# OpenTallas memory compiler (tools/mem_compiler), ASAP7 abstract view
VERSION 5.7 ;
BUSBITCHARS "[]" ;
DIVIDERCHAR "/" ;
PROPERTYDEFINITIONS
  MACRO width INTEGER ;
  MACRO depth INTEGER ;
  MACRO banks INTEGER ;
END PROPERTYDEFINITIONS
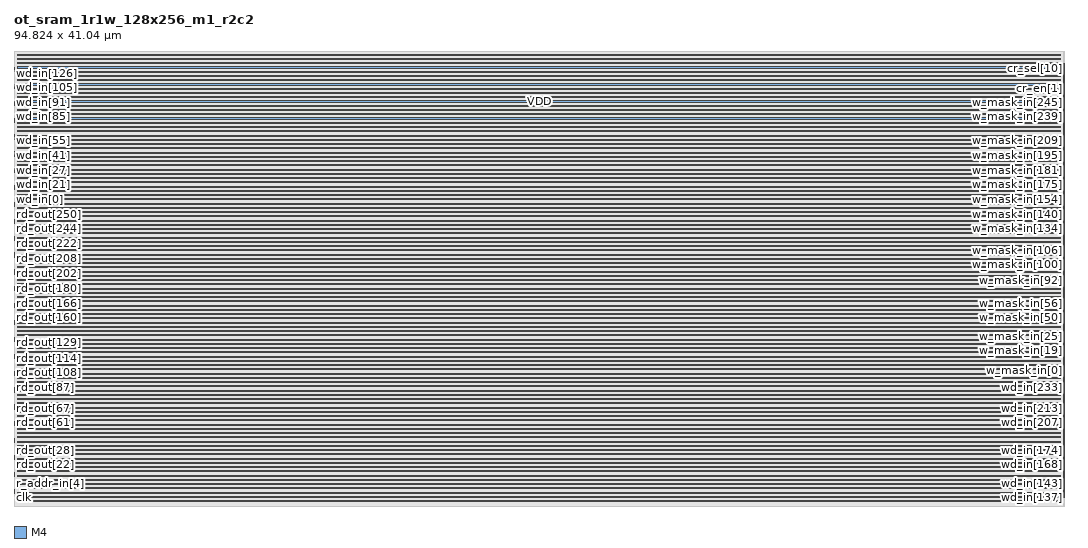
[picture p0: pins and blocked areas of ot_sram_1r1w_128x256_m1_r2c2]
MACRO ot_sram_1r1w_128x256_m1_r2c2
  PROPERTY width 256 ;
  PROPERTY depth 128 ;
  PROPERTY banks 1 ;
  FOREIGN ot_sram_1r1w_128x256_m1_r2c2 0 0 ;
  SYMMETRY X Y R90 ;
  SIZE 94.824 BY 41.040 ;
  CLASS BLOCK ;
  PIN clk
    DIRECTION INPUT ;
    USE CLOCK ;
    SHAPE ABUTMENT ;
    PORT
      LAYER M4 ;
      RECT 0.000 0.768 0.024 0.792 ;
    END
  END clk
  PIN r_ce_in
    DIRECTION INPUT ;
    USE SIGNAL ;
    SHAPE ABUTMENT ;
    PORT
      LAYER M4 ;
      RECT 0.000 0.864 0.024 0.888 ;
    END
  END r_ce_in
  PIN r_addr_in[0]
    DIRECTION INPUT ;
    USE SIGNAL ;
    SHAPE ABUTMENT ;
    PORT
      LAYER M4 ;
      RECT 0.000 0.960 0.024 0.984 ;
    END
  END r_addr_in[0]
  PIN r_addr_in[1]
    DIRECTION INPUT ;
    USE SIGNAL ;
    SHAPE ABUTMENT ;
    PORT
      LAYER M4 ;
      RECT 0.000 1.056 0.024 1.080 ;
    END
  END r_addr_in[1]
  PIN r_addr_in[2]
    DIRECTION INPUT ;
    USE SIGNAL ;
    SHAPE ABUTMENT ;
    PORT
      LAYER M4 ;
      RECT 0.000 1.152 0.024 1.176 ;
    END
  END r_addr_in[2]
  PIN r_addr_in[3]
    DIRECTION INPUT ;
    USE SIGNAL ;
    SHAPE ABUTMENT ;
    PORT
      LAYER M4 ;
      RECT 0.000 1.248 0.024 1.272 ;
    END
  END r_addr_in[3]
  PIN r_addr_in[4]
    DIRECTION INPUT ;
    USE SIGNAL ;
    SHAPE ABUTMENT ;
    PORT
      LAYER M4 ;
      RECT 0.000 1.344 0.024 1.368 ;
    END
  END r_addr_in[4]
  PIN r_addr_in[5]
    DIRECTION INPUT ;
    USE SIGNAL ;
    SHAPE ABUTMENT ;
    PORT
      LAYER M4 ;
      RECT 0.000 1.440 0.024 1.464 ;
    END
  END r_addr_in[5]
  PIN r_addr_in[6]
    DIRECTION INPUT ;
    USE SIGNAL ;
    SHAPE ABUTMENT ;
    PORT
      LAYER M4 ;
      RECT 0.000 1.536 0.024 1.560 ;
    END
  END r_addr_in[6]
  PIN rd_out[0]
    DIRECTION OUTPUT ;
    USE SIGNAL ;
    SHAPE ABUTMENT ;
    PORT
      LAYER M4 ;
      RECT 0.000 1.632 0.024 1.656 ;
    END
  END rd_out[0]
  PIN rd_out[1]
    DIRECTION OUTPUT ;
    USE SIGNAL ;
    SHAPE ABUTMENT ;
    PORT
      LAYER M4 ;
      RECT 0.000 1.728 0.024 1.752 ;
    END
  END rd_out[1]
  PIN rd_out[2]
    DIRECTION OUTPUT ;
    USE SIGNAL ;
    SHAPE ABUTMENT ;
    PORT
      LAYER M4 ;
      RECT 0.000 1.824 0.024 1.848 ;
    END
  END rd_out[2]
  PIN rd_out[3]
    DIRECTION OUTPUT ;
    USE SIGNAL ;
    SHAPE ABUTMENT ;
    PORT
      LAYER M4 ;
      RECT 0.000 1.920 0.024 1.944 ;
    END
  END rd_out[3]
  PIN rd_out[4]
    DIRECTION OUTPUT ;
    USE SIGNAL ;
    SHAPE ABUTMENT ;
    PORT
      LAYER M4 ;
      RECT 0.000 2.016 0.024 2.040 ;
    END
  END rd_out[4]
  PIN rd_out[5]
    DIRECTION OUTPUT ;
    USE SIGNAL ;
    SHAPE ABUTMENT ;
    PORT
      LAYER M4 ;
      RECT 0.000 2.112 0.024 2.136 ;
    END
  END rd_out[5]
  PIN rd_out[6]
    DIRECTION OUTPUT ;
    USE SIGNAL ;
    SHAPE ABUTMENT ;
    PORT
      LAYER M4 ;
      RECT 0.000 2.208 0.024 2.232 ;
    END
  END rd_out[6]
  PIN rd_out[7]
    DIRECTION OUTPUT ;
    USE SIGNAL ;
    SHAPE ABUTMENT ;
    PORT
      LAYER M4 ;
      RECT 0.000 2.304 0.024 2.328 ;
    END
  END rd_out[7]
  PIN rd_out[8]
    DIRECTION OUTPUT ;
    USE SIGNAL ;
    SHAPE ABUTMENT ;
    PORT
      LAYER M4 ;
      RECT 0.000 2.400 0.024 2.424 ;
    END
  END rd_out[8]
  PIN rd_out[9]
    DIRECTION OUTPUT ;
    USE SIGNAL ;
    SHAPE ABUTMENT ;
    PORT
      LAYER M4 ;
      RECT 0.000 2.496 0.024 2.520 ;
    END
  END rd_out[9]
  PIN rd_out[10]
    DIRECTION OUTPUT ;
    USE SIGNAL ;
    SHAPE ABUTMENT ;
    PORT
      LAYER M4 ;
      RECT 0.000 2.592 0.024 2.616 ;
    END
  END rd_out[10]
  PIN rd_out[11]
    DIRECTION OUTPUT ;
    USE SIGNAL ;
    SHAPE ABUTMENT ;
    PORT
      LAYER M4 ;
      RECT 0.000 2.688 0.024 2.712 ;
    END
  END rd_out[11]
  PIN rd_out[12]
    DIRECTION OUTPUT ;
    USE SIGNAL ;
    SHAPE ABUTMENT ;
    PORT
      LAYER M4 ;
      RECT 0.000 2.784 0.024 2.808 ;
    END
  END rd_out[12]
  PIN rd_out[13]
    DIRECTION OUTPUT ;
    USE SIGNAL ;
    SHAPE ABUTMENT ;
    PORT
      LAYER M4 ;
      RECT 0.000 2.880 0.024 2.904 ;
    END
  END rd_out[13]
  PIN rd_out[14]
    DIRECTION OUTPUT ;
    USE SIGNAL ;
    SHAPE ABUTMENT ;
    PORT
      LAYER M4 ;
      RECT 0.000 2.976 0.024 3.000 ;
    END
  END rd_out[14]
  PIN rd_out[15]
    DIRECTION OUTPUT ;
    USE SIGNAL ;
    SHAPE ABUTMENT ;
    PORT
      LAYER M4 ;
      RECT 0.000 3.072 0.024 3.096 ;
    END
  END rd_out[15]
  PIN rd_out[16]
    DIRECTION OUTPUT ;
    USE SIGNAL ;
    SHAPE ABUTMENT ;
    PORT
      LAYER M4 ;
      RECT 0.000 3.168 0.024 3.192 ;
    END
  END rd_out[16]
  PIN rd_out[17]
    DIRECTION OUTPUT ;
    USE SIGNAL ;
    SHAPE ABUTMENT ;
    PORT
      LAYER M4 ;
      RECT 0.000 3.264 0.024 3.288 ;
    END
  END rd_out[17]
  PIN rd_out[18]
    DIRECTION OUTPUT ;
    USE SIGNAL ;
    SHAPE ABUTMENT ;
    PORT
      LAYER M4 ;
      RECT 0.000 3.360 0.024 3.384 ;
    END
  END rd_out[18]
  PIN rd_out[19]
    DIRECTION OUTPUT ;
    USE SIGNAL ;
    SHAPE ABUTMENT ;
    PORT
      LAYER M4 ;
      RECT 0.000 3.456 0.024 3.480 ;
    END
  END rd_out[19]
  PIN rd_out[20]
    DIRECTION OUTPUT ;
    USE SIGNAL ;
    SHAPE ABUTMENT ;
    PORT
      LAYER M4 ;
      RECT 0.000 3.552 0.024 3.576 ;
    END
  END rd_out[20]
  PIN rd_out[21]
    DIRECTION OUTPUT ;
    USE SIGNAL ;
    SHAPE ABUTMENT ;
    PORT
      LAYER M4 ;
      RECT 0.000 3.648 0.024 3.672 ;
    END
  END rd_out[21]
  PIN rd_out[22]
    DIRECTION OUTPUT ;
    USE SIGNAL ;
    SHAPE ABUTMENT ;
    PORT
      LAYER M4 ;
      RECT 0.000 3.744 0.024 3.768 ;
    END
  END rd_out[22]
  PIN rd_out[23]
    DIRECTION OUTPUT ;
    USE SIGNAL ;
    SHAPE ABUTMENT ;
    PORT
      LAYER M4 ;
      RECT 0.000 3.840 0.024 3.864 ;
    END
  END rd_out[23]
  PIN rd_out[24]
    DIRECTION OUTPUT ;
    USE SIGNAL ;
    SHAPE ABUTMENT ;
    PORT
      LAYER M4 ;
      RECT 0.000 3.936 0.024 3.960 ;
    END
  END rd_out[24]
  PIN rd_out[25]
    DIRECTION OUTPUT ;
    USE SIGNAL ;
    SHAPE ABUTMENT ;
    PORT
      LAYER M4 ;
      RECT 0.000 4.032 0.024 4.056 ;
    END
  END rd_out[25]
  PIN rd_out[26]
    DIRECTION OUTPUT ;
    USE SIGNAL ;
    SHAPE ABUTMENT ;
    PORT
      LAYER M4 ;
      RECT 0.000 4.128 0.024 4.152 ;
    END
  END rd_out[26]
  PIN rd_out[27]
    DIRECTION OUTPUT ;
    USE SIGNAL ;
    SHAPE ABUTMENT ;
    PORT
      LAYER M4 ;
      RECT 0.000 4.224 0.024 4.248 ;
    END
  END rd_out[27]
  PIN rd_out[28]
    DIRECTION OUTPUT ;
    USE SIGNAL ;
    SHAPE ABUTMENT ;
    PORT
      LAYER M4 ;
      RECT 0.000 4.320 0.024 4.344 ;
    END
  END rd_out[28]
  PIN rd_out[29]
    DIRECTION OUTPUT ;
    USE SIGNAL ;
    SHAPE ABUTMENT ;
    PORT
      LAYER M4 ;
      RECT 0.000 4.416 0.024 4.440 ;
    END
  END rd_out[29]
  PIN rd_out[30]
    DIRECTION OUTPUT ;
    USE SIGNAL ;
    SHAPE ABUTMENT ;
    PORT
      LAYER M4 ;
      RECT 0.000 4.512 0.024 4.536 ;
    END
  END rd_out[30]
  PIN rd_out[31]
    DIRECTION OUTPUT ;
    USE SIGNAL ;
    SHAPE ABUTMENT ;
    PORT
      LAYER M4 ;
      RECT 0.000 4.608 0.024 4.632 ;
    END
  END rd_out[31]
  PIN rd_out[32]
    DIRECTION OUTPUT ;
    USE SIGNAL ;
    SHAPE ABUTMENT ;
    PORT
      LAYER M4 ;
      RECT 0.000 4.704 0.024 4.728 ;
    END
  END rd_out[32]
  PIN rd_out[33]
    DIRECTION OUTPUT ;
    USE SIGNAL ;
    SHAPE ABUTMENT ;
    PORT
      LAYER M4 ;
      RECT 0.000 4.800 0.024 4.824 ;
    END
  END rd_out[33]
  PIN rd_out[34]
    DIRECTION OUTPUT ;
    USE SIGNAL ;
    SHAPE ABUTMENT ;
    PORT
      LAYER M4 ;
      RECT 0.000 4.896 0.024 4.920 ;
    END
  END rd_out[34]
  PIN rd_out[35]
    DIRECTION OUTPUT ;
    USE SIGNAL ;
    SHAPE ABUTMENT ;
    PORT
      LAYER M4 ;
      RECT 0.000 4.992 0.024 5.016 ;
    END
  END rd_out[35]
  PIN rd_out[36]
    DIRECTION OUTPUT ;
    USE SIGNAL ;
    SHAPE ABUTMENT ;
    PORT
      LAYER M4 ;
      RECT 0.000 5.088 0.024 5.112 ;
    END
  END rd_out[36]
  PIN rd_out[37]
    DIRECTION OUTPUT ;
    USE SIGNAL ;
    SHAPE ABUTMENT ;
    PORT
      LAYER M4 ;
      RECT 0.000 5.184 0.024 5.208 ;
    END
  END rd_out[37]
  PIN rd_out[38]
    DIRECTION OUTPUT ;
    USE SIGNAL ;
    SHAPE ABUTMENT ;
    PORT
      LAYER M4 ;
      RECT 0.000 5.280 0.024 5.304 ;
    END
  END rd_out[38]
  PIN rd_out[39]
    DIRECTION OUTPUT ;
    USE SIGNAL ;
    SHAPE ABUTMENT ;
    PORT
      LAYER M4 ;
      RECT 0.000 5.376 0.024 5.400 ;
    END
  END rd_out[39]
  PIN rd_out[40]
    DIRECTION OUTPUT ;
    USE SIGNAL ;
    SHAPE ABUTMENT ;
    PORT
      LAYER M4 ;
      RECT 0.000 5.472 0.024 5.496 ;
    END
  END rd_out[40]
  PIN rd_out[41]
    DIRECTION OUTPUT ;
    USE SIGNAL ;
    SHAPE ABUTMENT ;
    PORT
      LAYER M4 ;
      RECT 0.000 5.568 0.024 5.592 ;
    END
  END rd_out[41]
  PIN rd_out[42]
    DIRECTION OUTPUT ;
    USE SIGNAL ;
    SHAPE ABUTMENT ;
    PORT
      LAYER M4 ;
      RECT 0.000 5.664 0.024 5.688 ;
    END
  END rd_out[42]
  PIN rd_out[43]
    DIRECTION OUTPUT ;
    USE SIGNAL ;
    SHAPE ABUTMENT ;
    PORT
      LAYER M4 ;
      RECT 0.000 5.760 0.024 5.784 ;
    END
  END rd_out[43]
  PIN rd_out[44]
    DIRECTION OUTPUT ;
    USE SIGNAL ;
    SHAPE ABUTMENT ;
    PORT
      LAYER M4 ;
      RECT 0.000 5.856 0.024 5.880 ;
    END
  END rd_out[44]
  PIN rd_out[45]
    DIRECTION OUTPUT ;
    USE SIGNAL ;
    SHAPE ABUTMENT ;
    PORT
      LAYER M4 ;
      RECT 0.000 5.952 0.024 5.976 ;
    END
  END rd_out[45]
  PIN rd_out[46]
    DIRECTION OUTPUT ;
    USE SIGNAL ;
    SHAPE ABUTMENT ;
    PORT
      LAYER M4 ;
      RECT 0.000 6.048 0.024 6.072 ;
    END
  END rd_out[46]
  PIN rd_out[47]
    DIRECTION OUTPUT ;
    USE SIGNAL ;
    SHAPE ABUTMENT ;
    PORT
      LAYER M4 ;
      RECT 0.000 6.144 0.024 6.168 ;
    END
  END rd_out[47]
  PIN rd_out[48]
    DIRECTION OUTPUT ;
    USE SIGNAL ;
    SHAPE ABUTMENT ;
    PORT
      LAYER M4 ;
      RECT 0.000 6.240 0.024 6.264 ;
    END
  END rd_out[48]
  PIN rd_out[49]
    DIRECTION OUTPUT ;
    USE SIGNAL ;
    SHAPE ABUTMENT ;
    PORT
      LAYER M4 ;
      RECT 0.000 6.336 0.024 6.360 ;
    END
  END rd_out[49]
  PIN rd_out[50]
    DIRECTION OUTPUT ;
    USE SIGNAL ;
    SHAPE ABUTMENT ;
    PORT
      LAYER M4 ;
      RECT 0.000 6.432 0.024 6.456 ;
    END
  END rd_out[50]
  PIN rd_out[51]
    DIRECTION OUTPUT ;
    USE SIGNAL ;
    SHAPE ABUTMENT ;
    PORT
      LAYER M4 ;
      RECT 0.000 6.528 0.024 6.552 ;
    END
  END rd_out[51]
  PIN rd_out[52]
    DIRECTION OUTPUT ;
    USE SIGNAL ;
    SHAPE ABUTMENT ;
    PORT
      LAYER M4 ;
      RECT 0.000 6.624 0.024 6.648 ;
    END
  END rd_out[52]
  PIN rd_out[53]
    DIRECTION OUTPUT ;
    USE SIGNAL ;
    SHAPE ABUTMENT ;
    PORT
      LAYER M4 ;
      RECT 0.000 6.720 0.024 6.744 ;
    END
  END rd_out[53]
  PIN rd_out[54]
    DIRECTION OUTPUT ;
    USE SIGNAL ;
    SHAPE ABUTMENT ;
    PORT
      LAYER M4 ;
      RECT 0.000 6.816 0.024 6.840 ;
    END
  END rd_out[54]
  PIN rd_out[55]
    DIRECTION OUTPUT ;
    USE SIGNAL ;
    SHAPE ABUTMENT ;
    PORT
      LAYER M4 ;
      RECT 0.000 6.912 0.024 6.936 ;
    END
  END rd_out[55]
  PIN rd_out[56]
    DIRECTION OUTPUT ;
    USE SIGNAL ;
    SHAPE ABUTMENT ;
    PORT
      LAYER M4 ;
      RECT 0.000 7.008 0.024 7.032 ;
    END
  END rd_out[56]
  PIN rd_out[57]
    DIRECTION OUTPUT ;
    USE SIGNAL ;
    SHAPE ABUTMENT ;
    PORT
      LAYER M4 ;
      RECT 0.000 7.104 0.024 7.128 ;
    END
  END rd_out[57]
  PIN rd_out[58]
    DIRECTION OUTPUT ;
    USE SIGNAL ;
    SHAPE ABUTMENT ;
    PORT
      LAYER M4 ;
      RECT 0.000 7.200 0.024 7.224 ;
    END
  END rd_out[58]
  PIN rd_out[59]
    DIRECTION OUTPUT ;
    USE SIGNAL ;
    SHAPE ABUTMENT ;
    PORT
      LAYER M4 ;
      RECT 0.000 7.296 0.024 7.320 ;
    END
  END rd_out[59]
  PIN rd_out[60]
    DIRECTION OUTPUT ;
    USE SIGNAL ;
    SHAPE ABUTMENT ;
    PORT
      LAYER M4 ;
      RECT 0.000 7.392 0.024 7.416 ;
    END
  END rd_out[60]
  PIN rd_out[61]
    DIRECTION OUTPUT ;
    USE SIGNAL ;
    SHAPE ABUTMENT ;
    PORT
      LAYER M4 ;
      RECT 0.000 7.488 0.024 7.512 ;
    END
  END rd_out[61]
  PIN rd_out[62]
    DIRECTION OUTPUT ;
    USE SIGNAL ;
    SHAPE ABUTMENT ;
    PORT
      LAYER M4 ;
      RECT 0.000 7.584 0.024 7.608 ;
    END
  END rd_out[62]
  PIN rd_out[63]
    DIRECTION OUTPUT ;
    USE SIGNAL ;
    SHAPE ABUTMENT ;
    PORT
      LAYER M4 ;
      RECT 0.000 7.680 0.024 7.704 ;
    END
  END rd_out[63]
  PIN rd_out[64]
    DIRECTION OUTPUT ;
    USE SIGNAL ;
    SHAPE ABUTMENT ;
    PORT
      LAYER M4 ;
      RECT 0.000 7.776 0.024 7.800 ;
    END
  END rd_out[64]
  PIN rd_out[65]
    DIRECTION OUTPUT ;
    USE SIGNAL ;
    SHAPE ABUTMENT ;
    PORT
      LAYER M4 ;
      RECT 0.000 7.872 0.024 7.896 ;
    END
  END rd_out[65]
  PIN rd_out[66]
    DIRECTION OUTPUT ;
    USE SIGNAL ;
    SHAPE ABUTMENT ;
    PORT
      LAYER M4 ;
      RECT 0.000 7.968 0.024 7.992 ;
    END
  END rd_out[66]
  PIN rd_out[67]
    DIRECTION OUTPUT ;
    USE SIGNAL ;
    SHAPE ABUTMENT ;
    PORT
      LAYER M4 ;
      RECT 0.000 8.064 0.024 8.088 ;
    END
  END rd_out[67]
  PIN rd_out[68]
    DIRECTION OUTPUT ;
    USE SIGNAL ;
    SHAPE ABUTMENT ;
    PORT
      LAYER M4 ;
      RECT 0.000 8.160 0.024 8.184 ;
    END
  END rd_out[68]
  PIN rd_out[69]
    DIRECTION OUTPUT ;
    USE SIGNAL ;
    SHAPE ABUTMENT ;
    PORT
      LAYER M4 ;
      RECT 0.000 8.256 0.024 8.280 ;
    END
  END rd_out[69]
  PIN rd_out[70]
    DIRECTION OUTPUT ;
    USE SIGNAL ;
    SHAPE ABUTMENT ;
    PORT
      LAYER M4 ;
      RECT 0.000 8.352 0.024 8.376 ;
    END
  END rd_out[70]
  PIN rd_out[71]
    DIRECTION OUTPUT ;
    USE SIGNAL ;
    SHAPE ABUTMENT ;
    PORT
      LAYER M4 ;
      RECT 0.000 8.448 0.024 8.472 ;
    END
  END rd_out[71]
  PIN rd_out[72]
    DIRECTION OUTPUT ;
    USE SIGNAL ;
    SHAPE ABUTMENT ;
    PORT
      LAYER M4 ;
      RECT 0.000 8.544 0.024 8.568 ;
    END
  END rd_out[72]
  PIN rd_out[73]
    DIRECTION OUTPUT ;
    USE SIGNAL ;
    SHAPE ABUTMENT ;
    PORT
      LAYER M4 ;
      RECT 0.000 8.640 0.024 8.664 ;
    END
  END rd_out[73]
  PIN rd_out[74]
    DIRECTION OUTPUT ;
    USE SIGNAL ;
    SHAPE ABUTMENT ;
    PORT
      LAYER M4 ;
      RECT 0.000 8.736 0.024 8.760 ;
    END
  END rd_out[74]
  PIN rd_out[75]
    DIRECTION OUTPUT ;
    USE SIGNAL ;
    SHAPE ABUTMENT ;
    PORT
      LAYER M4 ;
      RECT 0.000 8.832 0.024 8.856 ;
    END
  END rd_out[75]
  PIN rd_out[76]
    DIRECTION OUTPUT ;
    USE SIGNAL ;
    SHAPE ABUTMENT ;
    PORT
      LAYER M4 ;
      RECT 0.000 8.928 0.024 8.952 ;
    END
  END rd_out[76]
  PIN rd_out[77]
    DIRECTION OUTPUT ;
    USE SIGNAL ;
    SHAPE ABUTMENT ;
    PORT
      LAYER M4 ;
      RECT 0.000 9.024 0.024 9.048 ;
    END
  END rd_out[77]
  PIN rd_out[78]
    DIRECTION OUTPUT ;
    USE SIGNAL ;
    SHAPE ABUTMENT ;
    PORT
      LAYER M4 ;
      RECT 0.000 9.120 0.024 9.144 ;
    END
  END rd_out[78]
  PIN rd_out[79]
    DIRECTION OUTPUT ;
    USE SIGNAL ;
    SHAPE ABUTMENT ;
    PORT
      LAYER M4 ;
      RECT 0.000 9.216 0.024 9.240 ;
    END
  END rd_out[79]
  PIN rd_out[80]
    DIRECTION OUTPUT ;
    USE SIGNAL ;
    SHAPE ABUTMENT ;
    PORT
      LAYER M4 ;
      RECT 0.000 9.312 0.024 9.336 ;
    END
  END rd_out[80]
  PIN rd_out[81]
    DIRECTION OUTPUT ;
    USE SIGNAL ;
    SHAPE ABUTMENT ;
    PORT
      LAYER M4 ;
      RECT 0.000 9.408 0.024 9.432 ;
    END
  END rd_out[81]
  PIN rd_out[82]
    DIRECTION OUTPUT ;
    USE SIGNAL ;
    SHAPE ABUTMENT ;
    PORT
      LAYER M4 ;
      RECT 0.000 9.504 0.024 9.528 ;
    END
  END rd_out[82]
  PIN rd_out[83]
    DIRECTION OUTPUT ;
    USE SIGNAL ;
    SHAPE ABUTMENT ;
    PORT
      LAYER M4 ;
      RECT 0.000 9.600 0.024 9.624 ;
    END
  END rd_out[83]
  PIN rd_out[84]
    DIRECTION OUTPUT ;
    USE SIGNAL ;
    SHAPE ABUTMENT ;
    PORT
      LAYER M4 ;
      RECT 0.000 9.696 0.024 9.720 ;
    END
  END rd_out[84]
  PIN rd_out[85]
    DIRECTION OUTPUT ;
    USE SIGNAL ;
    SHAPE ABUTMENT ;
    PORT
      LAYER M4 ;
      RECT 0.000 9.792 0.024 9.816 ;
    END
  END rd_out[85]
  PIN rd_out[86]
    DIRECTION OUTPUT ;
    USE SIGNAL ;
    SHAPE ABUTMENT ;
    PORT
      LAYER M4 ;
      RECT 0.000 9.888 0.024 9.912 ;
    END
  END rd_out[86]
  PIN rd_out[87]
    DIRECTION OUTPUT ;
    USE SIGNAL ;
    SHAPE ABUTMENT ;
    PORT
      LAYER M4 ;
      RECT 0.000 9.984 0.024 10.008 ;
    END
  END rd_out[87]
  PIN rd_out[88]
    DIRECTION OUTPUT ;
    USE SIGNAL ;
    SHAPE ABUTMENT ;
    PORT
      LAYER M4 ;
      RECT 0.000 10.080 0.024 10.104 ;
    END
  END rd_out[88]
  PIN rd_out[89]
    DIRECTION OUTPUT ;
    USE SIGNAL ;
    SHAPE ABUTMENT ;
    PORT
      LAYER M4 ;
      RECT 0.000 10.176 0.024 10.200 ;
    END
  END rd_out[89]
  PIN rd_out[90]
    DIRECTION OUTPUT ;
    USE SIGNAL ;
    SHAPE ABUTMENT ;
    PORT
      LAYER M4 ;
      RECT 0.000 10.272 0.024 10.296 ;
    END
  END rd_out[90]
  PIN rd_out[91]
    DIRECTION OUTPUT ;
    USE SIGNAL ;
    SHAPE ABUTMENT ;
    PORT
      LAYER M4 ;
      RECT 0.000 10.368 0.024 10.392 ;
    END
  END rd_out[91]
  PIN rd_out[92]
    DIRECTION OUTPUT ;
    USE SIGNAL ;
    SHAPE ABUTMENT ;
    PORT
      LAYER M4 ;
      RECT 0.000 10.464 0.024 10.488 ;
    END
  END rd_out[92]
  PIN rd_out[93]
    DIRECTION OUTPUT ;
    USE SIGNAL ;
    SHAPE ABUTMENT ;
    PORT
      LAYER M4 ;
      RECT 0.000 10.560 0.024 10.584 ;
    END
  END rd_out[93]
  PIN rd_out[94]
    DIRECTION OUTPUT ;
    USE SIGNAL ;
    SHAPE ABUTMENT ;
    PORT
      LAYER M4 ;
      RECT 0.000 10.656 0.024 10.680 ;
    END
  END rd_out[94]
  PIN rd_out[95]
    DIRECTION OUTPUT ;
    USE SIGNAL ;
    SHAPE ABUTMENT ;
    PORT
      LAYER M4 ;
      RECT 0.000 10.752 0.024 10.776 ;
    END
  END rd_out[95]
  PIN rd_out[96]
    DIRECTION OUTPUT ;
    USE SIGNAL ;
    SHAPE ABUTMENT ;
    PORT
      LAYER M4 ;
      RECT 0.000 10.848 0.024 10.872 ;
    END
  END rd_out[96]
  PIN rd_out[97]
    DIRECTION OUTPUT ;
    USE SIGNAL ;
    SHAPE ABUTMENT ;
    PORT
      LAYER M4 ;
      RECT 0.000 10.944 0.024 10.968 ;
    END
  END rd_out[97]
  PIN rd_out[98]
    DIRECTION OUTPUT ;
    USE SIGNAL ;
    SHAPE ABUTMENT ;
    PORT
      LAYER M4 ;
      RECT 0.000 11.040 0.024 11.064 ;
    END
  END rd_out[98]
  PIN rd_out[99]
    DIRECTION OUTPUT ;
    USE SIGNAL ;
    SHAPE ABUTMENT ;
    PORT
      LAYER M4 ;
      RECT 0.000 11.136 0.024 11.160 ;
    END
  END rd_out[99]
  PIN rd_out[100]
    DIRECTION OUTPUT ;
    USE SIGNAL ;
    SHAPE ABUTMENT ;
    PORT
      LAYER M4 ;
      RECT 0.000 11.232 0.024 11.256 ;
    END
  END rd_out[100]
  PIN rd_out[101]
    DIRECTION OUTPUT ;
    USE SIGNAL ;
    SHAPE ABUTMENT ;
    PORT
      LAYER M4 ;
      RECT 0.000 11.328 0.024 11.352 ;
    END
  END rd_out[101]
  PIN rd_out[102]
    DIRECTION OUTPUT ;
    USE SIGNAL ;
    SHAPE ABUTMENT ;
    PORT
      LAYER M4 ;
      RECT 0.000 11.424 0.024 11.448 ;
    END
  END rd_out[102]
  PIN rd_out[103]
    DIRECTION OUTPUT ;
    USE SIGNAL ;
    SHAPE ABUTMENT ;
    PORT
      LAYER M4 ;
      RECT 0.000 11.520 0.024 11.544 ;
    END
  END rd_out[103]
  PIN rd_out[104]
    DIRECTION OUTPUT ;
    USE SIGNAL ;
    SHAPE ABUTMENT ;
    PORT
      LAYER M4 ;
      RECT 0.000 11.616 0.024 11.640 ;
    END
  END rd_out[104]
  PIN rd_out[105]
    DIRECTION OUTPUT ;
    USE SIGNAL ;
    SHAPE ABUTMENT ;
    PORT
      LAYER M4 ;
      RECT 0.000 11.712 0.024 11.736 ;
    END
  END rd_out[105]
  PIN rd_out[106]
    DIRECTION OUTPUT ;
    USE SIGNAL ;
    SHAPE ABUTMENT ;
    PORT
      LAYER M4 ;
      RECT 0.000 11.808 0.024 11.832 ;
    END
  END rd_out[106]
  PIN rd_out[107]
    DIRECTION OUTPUT ;
    USE SIGNAL ;
    SHAPE ABUTMENT ;
    PORT
      LAYER M4 ;
      RECT 0.000 11.904 0.024 11.928 ;
    END
  END rd_out[107]
  PIN rd_out[108]
    DIRECTION OUTPUT ;
    USE SIGNAL ;
    SHAPE ABUTMENT ;
    PORT
      LAYER M4 ;
      RECT 0.000 12.000 0.024 12.024 ;
    END
  END rd_out[108]
  PIN rd_out[109]
    DIRECTION OUTPUT ;
    USE SIGNAL ;
    SHAPE ABUTMENT ;
    PORT
      LAYER M4 ;
      RECT 0.000 12.096 0.024 12.120 ;
    END
  END rd_out[109]
  PIN rd_out[110]
    DIRECTION OUTPUT ;
    USE SIGNAL ;
    SHAPE ABUTMENT ;
    PORT
      LAYER M4 ;
      RECT 0.000 12.192 0.024 12.216 ;
    END
  END rd_out[110]
  PIN rd_out[111]
    DIRECTION OUTPUT ;
    USE SIGNAL ;
    SHAPE ABUTMENT ;
    PORT
      LAYER M4 ;
      RECT 0.000 12.288 0.024 12.312 ;
    END
  END rd_out[111]
  PIN rd_out[112]
    DIRECTION OUTPUT ;
    USE SIGNAL ;
    SHAPE ABUTMENT ;
    PORT
      LAYER M4 ;
      RECT 0.000 12.384 0.024 12.408 ;
    END
  END rd_out[112]
  PIN rd_out[113]
    DIRECTION OUTPUT ;
    USE SIGNAL ;
    SHAPE ABUTMENT ;
    PORT
      LAYER M4 ;
      RECT 0.000 12.480 0.024 12.504 ;
    END
  END rd_out[113]
  PIN rd_out[114]
    DIRECTION OUTPUT ;
    USE SIGNAL ;
    SHAPE ABUTMENT ;
    PORT
      LAYER M4 ;
      RECT 0.000 12.576 0.024 12.600 ;
    END
  END rd_out[114]
  PIN rd_out[115]
    DIRECTION OUTPUT ;
    USE SIGNAL ;
    SHAPE ABUTMENT ;
    PORT
      LAYER M4 ;
      RECT 0.000 12.672 0.024 12.696 ;
    END
  END rd_out[115]
  PIN rd_out[116]
    DIRECTION OUTPUT ;
    USE SIGNAL ;
    SHAPE ABUTMENT ;
    PORT
      LAYER M4 ;
      RECT 0.000 12.768 0.024 12.792 ;
    END
  END rd_out[116]
  PIN rd_out[117]
    DIRECTION OUTPUT ;
    USE SIGNAL ;
    SHAPE ABUTMENT ;
    PORT
      LAYER M4 ;
      RECT 0.000 12.864 0.024 12.888 ;
    END
  END rd_out[117]
  PIN rd_out[118]
    DIRECTION OUTPUT ;
    USE SIGNAL ;
    SHAPE ABUTMENT ;
    PORT
      LAYER M4 ;
      RECT 0.000 12.960 0.024 12.984 ;
    END
  END rd_out[118]
  PIN rd_out[119]
    DIRECTION OUTPUT ;
    USE SIGNAL ;
    SHAPE ABUTMENT ;
    PORT
      LAYER M4 ;
      RECT 0.000 13.056 0.024 13.080 ;
    END
  END rd_out[119]
  PIN rd_out[120]
    DIRECTION OUTPUT ;
    USE SIGNAL ;
    SHAPE ABUTMENT ;
    PORT
      LAYER M4 ;
      RECT 0.000 13.152 0.024 13.176 ;
    END
  END rd_out[120]
  PIN rd_out[121]
    DIRECTION OUTPUT ;
    USE SIGNAL ;
    SHAPE ABUTMENT ;
    PORT
      LAYER M4 ;
      RECT 0.000 13.248 0.024 13.272 ;
    END
  END rd_out[121]
  PIN rd_out[122]
    DIRECTION OUTPUT ;
    USE SIGNAL ;
    SHAPE ABUTMENT ;
    PORT
      LAYER M4 ;
      RECT 0.000 13.344 0.024 13.368 ;
    END
  END rd_out[122]
  PIN rd_out[123]
    DIRECTION OUTPUT ;
    USE SIGNAL ;
    SHAPE ABUTMENT ;
    PORT
      LAYER M4 ;
      RECT 0.000 13.440 0.024 13.464 ;
    END
  END rd_out[123]
  PIN rd_out[124]
    DIRECTION OUTPUT ;
    USE SIGNAL ;
    SHAPE ABUTMENT ;
    PORT
      LAYER M4 ;
      RECT 0.000 13.536 0.024 13.560 ;
    END
  END rd_out[124]
  PIN rd_out[125]
    DIRECTION OUTPUT ;
    USE SIGNAL ;
    SHAPE ABUTMENT ;
    PORT
      LAYER M4 ;
      RECT 0.000 13.632 0.024 13.656 ;
    END
  END rd_out[125]
  PIN rd_out[126]
    DIRECTION OUTPUT ;
    USE SIGNAL ;
    SHAPE ABUTMENT ;
    PORT
      LAYER M4 ;
      RECT 0.000 13.728 0.024 13.752 ;
    END
  END rd_out[126]
  PIN rd_out[127]
    DIRECTION OUTPUT ;
    USE SIGNAL ;
    SHAPE ABUTMENT ;
    PORT
      LAYER M4 ;
      RECT 0.000 13.824 0.024 13.848 ;
    END
  END rd_out[127]
  PIN rd_out[128]
    DIRECTION OUTPUT ;
    USE SIGNAL ;
    SHAPE ABUTMENT ;
    PORT
      LAYER M4 ;
      RECT 0.000 13.920 0.024 13.944 ;
    END
  END rd_out[128]
  PIN rd_out[129]
    DIRECTION OUTPUT ;
    USE SIGNAL ;
    SHAPE ABUTMENT ;
    PORT
      LAYER M4 ;
      RECT 0.000 14.016 0.024 14.040 ;
    END
  END rd_out[129]
  PIN rd_out[130]
    DIRECTION OUTPUT ;
    USE SIGNAL ;
    SHAPE ABUTMENT ;
    PORT
      LAYER M4 ;
      RECT 0.000 14.112 0.024 14.136 ;
    END
  END rd_out[130]
  PIN rd_out[131]
    DIRECTION OUTPUT ;
    USE SIGNAL ;
    SHAPE ABUTMENT ;
    PORT
      LAYER M4 ;
      RECT 0.000 14.208 0.024 14.232 ;
    END
  END rd_out[131]
  PIN rd_out[132]
    DIRECTION OUTPUT ;
    USE SIGNAL ;
    SHAPE ABUTMENT ;
    PORT
      LAYER M4 ;
      RECT 0.000 14.304 0.024 14.328 ;
    END
  END rd_out[132]
  PIN rd_out[133]
    DIRECTION OUTPUT ;
    USE SIGNAL ;
    SHAPE ABUTMENT ;
    PORT
      LAYER M4 ;
      RECT 0.000 14.400 0.024 14.424 ;
    END
  END rd_out[133]
  PIN rd_out[134]
    DIRECTION OUTPUT ;
    USE SIGNAL ;
    SHAPE ABUTMENT ;
    PORT
      LAYER M4 ;
      RECT 0.000 14.496 0.024 14.520 ;
    END
  END rd_out[134]
  PIN rd_out[135]
    DIRECTION OUTPUT ;
    USE SIGNAL ;
    SHAPE ABUTMENT ;
    PORT
      LAYER M4 ;
      RECT 0.000 14.592 0.024 14.616 ;
    END
  END rd_out[135]
  PIN rd_out[136]
    DIRECTION OUTPUT ;
    USE SIGNAL ;
    SHAPE ABUTMENT ;
    PORT
      LAYER M4 ;
      RECT 0.000 14.688 0.024 14.712 ;
    END
  END rd_out[136]
  PIN rd_out[137]
    DIRECTION OUTPUT ;
    USE SIGNAL ;
    SHAPE ABUTMENT ;
    PORT
      LAYER M4 ;
      RECT 0.000 14.784 0.024 14.808 ;
    END
  END rd_out[137]
  PIN rd_out[138]
    DIRECTION OUTPUT ;
    USE SIGNAL ;
    SHAPE ABUTMENT ;
    PORT
      LAYER M4 ;
      RECT 0.000 14.880 0.024 14.904 ;
    END
  END rd_out[138]
  PIN rd_out[139]
    DIRECTION OUTPUT ;
    USE SIGNAL ;
    SHAPE ABUTMENT ;
    PORT
      LAYER M4 ;
      RECT 0.000 14.976 0.024 15.000 ;
    END
  END rd_out[139]
  PIN rd_out[140]
    DIRECTION OUTPUT ;
    USE SIGNAL ;
    SHAPE ABUTMENT ;
    PORT
      LAYER M4 ;
      RECT 0.000 15.072 0.024 15.096 ;
    END
  END rd_out[140]
  PIN rd_out[141]
    DIRECTION OUTPUT ;
    USE SIGNAL ;
    SHAPE ABUTMENT ;
    PORT
      LAYER M4 ;
      RECT 0.000 15.168 0.024 15.192 ;
    END
  END rd_out[141]
  PIN rd_out[142]
    DIRECTION OUTPUT ;
    USE SIGNAL ;
    SHAPE ABUTMENT ;
    PORT
      LAYER M4 ;
      RECT 0.000 15.264 0.024 15.288 ;
    END
  END rd_out[142]
  PIN rd_out[143]
    DIRECTION OUTPUT ;
    USE SIGNAL ;
    SHAPE ABUTMENT ;
    PORT
      LAYER M4 ;
      RECT 0.000 15.360 0.024 15.384 ;
    END
  END rd_out[143]
  PIN rd_out[144]
    DIRECTION OUTPUT ;
    USE SIGNAL ;
    SHAPE ABUTMENT ;
    PORT
      LAYER M4 ;
      RECT 0.000 15.456 0.024 15.480 ;
    END
  END rd_out[144]
  PIN rd_out[145]
    DIRECTION OUTPUT ;
    USE SIGNAL ;
    SHAPE ABUTMENT ;
    PORT
      LAYER M4 ;
      RECT 0.000 15.552 0.024 15.576 ;
    END
  END rd_out[145]
  PIN rd_out[146]
    DIRECTION OUTPUT ;
    USE SIGNAL ;
    SHAPE ABUTMENT ;
    PORT
      LAYER M4 ;
      RECT 0.000 15.648 0.024 15.672 ;
    END
  END rd_out[146]
  PIN rd_out[147]
    DIRECTION OUTPUT ;
    USE SIGNAL ;
    SHAPE ABUTMENT ;
    PORT
      LAYER M4 ;
      RECT 0.000 15.744 0.024 15.768 ;
    END
  END rd_out[147]
  PIN rd_out[148]
    DIRECTION OUTPUT ;
    USE SIGNAL ;
    SHAPE ABUTMENT ;
    PORT
      LAYER M4 ;
      RECT 0.000 15.840 0.024 15.864 ;
    END
  END rd_out[148]
  PIN rd_out[149]
    DIRECTION OUTPUT ;
    USE SIGNAL ;
    SHAPE ABUTMENT ;
    PORT
      LAYER M4 ;
      RECT 0.000 15.936 0.024 15.960 ;
    END
  END rd_out[149]
  PIN rd_out[150]
    DIRECTION OUTPUT ;
    USE SIGNAL ;
    SHAPE ABUTMENT ;
    PORT
      LAYER M4 ;
      RECT 0.000 16.032 0.024 16.056 ;
    END
  END rd_out[150]
  PIN rd_out[151]
    DIRECTION OUTPUT ;
    USE SIGNAL ;
    SHAPE ABUTMENT ;
    PORT
      LAYER M4 ;
      RECT 0.000 16.128 0.024 16.152 ;
    END
  END rd_out[151]
  PIN rd_out[152]
    DIRECTION OUTPUT ;
    USE SIGNAL ;
    SHAPE ABUTMENT ;
    PORT
      LAYER M4 ;
      RECT 0.000 16.224 0.024 16.248 ;
    END
  END rd_out[152]
  PIN rd_out[153]
    DIRECTION OUTPUT ;
    USE SIGNAL ;
    SHAPE ABUTMENT ;
    PORT
      LAYER M4 ;
      RECT 0.000 16.320 0.024 16.344 ;
    END
  END rd_out[153]
  PIN rd_out[154]
    DIRECTION OUTPUT ;
    USE SIGNAL ;
    SHAPE ABUTMENT ;
    PORT
      LAYER M4 ;
      RECT 0.000 16.416 0.024 16.440 ;
    END
  END rd_out[154]
  PIN rd_out[155]
    DIRECTION OUTPUT ;
    USE SIGNAL ;
    SHAPE ABUTMENT ;
    PORT
      LAYER M4 ;
      RECT 0.000 16.512 0.024 16.536 ;
    END
  END rd_out[155]
  PIN rd_out[156]
    DIRECTION OUTPUT ;
    USE SIGNAL ;
    SHAPE ABUTMENT ;
    PORT
      LAYER M4 ;
      RECT 0.000 16.608 0.024 16.632 ;
    END
  END rd_out[156]
  PIN rd_out[157]
    DIRECTION OUTPUT ;
    USE SIGNAL ;
    SHAPE ABUTMENT ;
    PORT
      LAYER M4 ;
      RECT 0.000 16.704 0.024 16.728 ;
    END
  END rd_out[157]
  PIN rd_out[158]
    DIRECTION OUTPUT ;
    USE SIGNAL ;
    SHAPE ABUTMENT ;
    PORT
      LAYER M4 ;
      RECT 0.000 16.800 0.024 16.824 ;
    END
  END rd_out[158]
  PIN rd_out[159]
    DIRECTION OUTPUT ;
    USE SIGNAL ;
    SHAPE ABUTMENT ;
    PORT
      LAYER M4 ;
      RECT 0.000 16.896 0.024 16.920 ;
    END
  END rd_out[159]
  PIN rd_out[160]
    DIRECTION OUTPUT ;
    USE SIGNAL ;
    SHAPE ABUTMENT ;
    PORT
      LAYER M4 ;
      RECT 0.000 16.992 0.024 17.016 ;
    END
  END rd_out[160]
  PIN rd_out[161]
    DIRECTION OUTPUT ;
    USE SIGNAL ;
    SHAPE ABUTMENT ;
    PORT
      LAYER M4 ;
      RECT 0.000 17.088 0.024 17.112 ;
    END
  END rd_out[161]
  PIN rd_out[162]
    DIRECTION OUTPUT ;
    USE SIGNAL ;
    SHAPE ABUTMENT ;
    PORT
      LAYER M4 ;
      RECT 0.000 17.184 0.024 17.208 ;
    END
  END rd_out[162]
  PIN rd_out[163]
    DIRECTION OUTPUT ;
    USE SIGNAL ;
    SHAPE ABUTMENT ;
    PORT
      LAYER M4 ;
      RECT 0.000 17.280 0.024 17.304 ;
    END
  END rd_out[163]
  PIN rd_out[164]
    DIRECTION OUTPUT ;
    USE SIGNAL ;
    SHAPE ABUTMENT ;
    PORT
      LAYER M4 ;
      RECT 0.000 17.376 0.024 17.400 ;
    END
  END rd_out[164]
  PIN rd_out[165]
    DIRECTION OUTPUT ;
    USE SIGNAL ;
    SHAPE ABUTMENT ;
    PORT
      LAYER M4 ;
      RECT 0.000 17.472 0.024 17.496 ;
    END
  END rd_out[165]
  PIN rd_out[166]
    DIRECTION OUTPUT ;
    USE SIGNAL ;
    SHAPE ABUTMENT ;
    PORT
      LAYER M4 ;
      RECT 0.000 17.568 0.024 17.592 ;
    END
  END rd_out[166]
  PIN rd_out[167]
    DIRECTION OUTPUT ;
    USE SIGNAL ;
    SHAPE ABUTMENT ;
    PORT
      LAYER M4 ;
      RECT 0.000 17.664 0.024 17.688 ;
    END
  END rd_out[167]
  PIN rd_out[168]
    DIRECTION OUTPUT ;
    USE SIGNAL ;
    SHAPE ABUTMENT ;
    PORT
      LAYER M4 ;
      RECT 0.000 17.760 0.024 17.784 ;
    END
  END rd_out[168]
  PIN rd_out[169]
    DIRECTION OUTPUT ;
    USE SIGNAL ;
    SHAPE ABUTMENT ;
    PORT
      LAYER M4 ;
      RECT 0.000 17.856 0.024 17.880 ;
    END
  END rd_out[169]
  PIN rd_out[170]
    DIRECTION OUTPUT ;
    USE SIGNAL ;
    SHAPE ABUTMENT ;
    PORT
      LAYER M4 ;
      RECT 0.000 17.952 0.024 17.976 ;
    END
  END rd_out[170]
  PIN rd_out[171]
    DIRECTION OUTPUT ;
    USE SIGNAL ;
    SHAPE ABUTMENT ;
    PORT
      LAYER M4 ;
      RECT 0.000 18.048 0.024 18.072 ;
    END
  END rd_out[171]
  PIN rd_out[172]
    DIRECTION OUTPUT ;
    USE SIGNAL ;
    SHAPE ABUTMENT ;
    PORT
      LAYER M4 ;
      RECT 0.000 18.144 0.024 18.168 ;
    END
  END rd_out[172]
  PIN rd_out[173]
    DIRECTION OUTPUT ;
    USE SIGNAL ;
    SHAPE ABUTMENT ;
    PORT
      LAYER M4 ;
      RECT 0.000 18.240 0.024 18.264 ;
    END
  END rd_out[173]
  PIN rd_out[174]
    DIRECTION OUTPUT ;
    USE SIGNAL ;
    SHAPE ABUTMENT ;
    PORT
      LAYER M4 ;
      RECT 0.000 18.336 0.024 18.360 ;
    END
  END rd_out[174]
  PIN rd_out[175]
    DIRECTION OUTPUT ;
    USE SIGNAL ;
    SHAPE ABUTMENT ;
    PORT
      LAYER M4 ;
      RECT 0.000 18.432 0.024 18.456 ;
    END
  END rd_out[175]
  PIN rd_out[176]
    DIRECTION OUTPUT ;
    USE SIGNAL ;
    SHAPE ABUTMENT ;
    PORT
      LAYER M4 ;
      RECT 0.000 18.528 0.024 18.552 ;
    END
  END rd_out[176]
  PIN rd_out[177]
    DIRECTION OUTPUT ;
    USE SIGNAL ;
    SHAPE ABUTMENT ;
    PORT
      LAYER M4 ;
      RECT 0.000 18.624 0.024 18.648 ;
    END
  END rd_out[177]
  PIN rd_out[178]
    DIRECTION OUTPUT ;
    USE SIGNAL ;
    SHAPE ABUTMENT ;
    PORT
      LAYER M4 ;
      RECT 0.000 18.720 0.024 18.744 ;
    END
  END rd_out[178]
  PIN rd_out[179]
    DIRECTION OUTPUT ;
    USE SIGNAL ;
    SHAPE ABUTMENT ;
    PORT
      LAYER M4 ;
      RECT 0.000 18.816 0.024 18.840 ;
    END
  END rd_out[179]
  PIN rd_out[180]
    DIRECTION OUTPUT ;
    USE SIGNAL ;
    SHAPE ABUTMENT ;
    PORT
      LAYER M4 ;
      RECT 0.000 18.912 0.024 18.936 ;
    END
  END rd_out[180]
  PIN rd_out[181]
    DIRECTION OUTPUT ;
    USE SIGNAL ;
    SHAPE ABUTMENT ;
    PORT
      LAYER M4 ;
      RECT 0.000 19.008 0.024 19.032 ;
    END
  END rd_out[181]
  PIN rd_out[182]
    DIRECTION OUTPUT ;
    USE SIGNAL ;
    SHAPE ABUTMENT ;
    PORT
      LAYER M4 ;
      RECT 0.000 19.104 0.024 19.128 ;
    END
  END rd_out[182]
  PIN rd_out[183]
    DIRECTION OUTPUT ;
    USE SIGNAL ;
    SHAPE ABUTMENT ;
    PORT
      LAYER M4 ;
      RECT 0.000 19.200 0.024 19.224 ;
    END
  END rd_out[183]
  PIN rd_out[184]
    DIRECTION OUTPUT ;
    USE SIGNAL ;
    SHAPE ABUTMENT ;
    PORT
      LAYER M4 ;
      RECT 0.000 19.296 0.024 19.320 ;
    END
  END rd_out[184]
  PIN rd_out[185]
    DIRECTION OUTPUT ;
    USE SIGNAL ;
    SHAPE ABUTMENT ;
    PORT
      LAYER M4 ;
      RECT 0.000 19.392 0.024 19.416 ;
    END
  END rd_out[185]
  PIN rd_out[186]
    DIRECTION OUTPUT ;
    USE SIGNAL ;
    SHAPE ABUTMENT ;
    PORT
      LAYER M4 ;
      RECT 0.000 19.488 0.024 19.512 ;
    END
  END rd_out[186]
  PIN rd_out[187]
    DIRECTION OUTPUT ;
    USE SIGNAL ;
    SHAPE ABUTMENT ;
    PORT
      LAYER M4 ;
      RECT 0.000 19.584 0.024 19.608 ;
    END
  END rd_out[187]
  PIN rd_out[188]
    DIRECTION OUTPUT ;
    USE SIGNAL ;
    SHAPE ABUTMENT ;
    PORT
      LAYER M4 ;
      RECT 0.000 19.680 0.024 19.704 ;
    END
  END rd_out[188]
  PIN rd_out[189]
    DIRECTION OUTPUT ;
    USE SIGNAL ;
    SHAPE ABUTMENT ;
    PORT
      LAYER M4 ;
      RECT 0.000 19.776 0.024 19.800 ;
    END
  END rd_out[189]
  PIN rd_out[190]
    DIRECTION OUTPUT ;
    USE SIGNAL ;
    SHAPE ABUTMENT ;
    PORT
      LAYER M4 ;
      RECT 0.000 19.872 0.024 19.896 ;
    END
  END rd_out[190]
  PIN rd_out[191]
    DIRECTION OUTPUT ;
    USE SIGNAL ;
    SHAPE ABUTMENT ;
    PORT
      LAYER M4 ;
      RECT 0.000 19.968 0.024 19.992 ;
    END
  END rd_out[191]
  PIN rd_out[192]
    DIRECTION OUTPUT ;
    USE SIGNAL ;
    SHAPE ABUTMENT ;
    PORT
      LAYER M4 ;
      RECT 0.000 20.064 0.024 20.088 ;
    END
  END rd_out[192]
  PIN rd_out[193]
    DIRECTION OUTPUT ;
    USE SIGNAL ;
    SHAPE ABUTMENT ;
    PORT
      LAYER M4 ;
      RECT 0.000 20.160 0.024 20.184 ;
    END
  END rd_out[193]
  PIN rd_out[194]
    DIRECTION OUTPUT ;
    USE SIGNAL ;
    SHAPE ABUTMENT ;
    PORT
      LAYER M4 ;
      RECT 0.000 20.256 0.024 20.280 ;
    END
  END rd_out[194]
  PIN rd_out[195]
    DIRECTION OUTPUT ;
    USE SIGNAL ;
    SHAPE ABUTMENT ;
    PORT
      LAYER M4 ;
      RECT 0.000 20.352 0.024 20.376 ;
    END
  END rd_out[195]
  PIN rd_out[196]
    DIRECTION OUTPUT ;
    USE SIGNAL ;
    SHAPE ABUTMENT ;
    PORT
      LAYER M4 ;
      RECT 0.000 20.448 0.024 20.472 ;
    END
  END rd_out[196]
  PIN rd_out[197]
    DIRECTION OUTPUT ;
    USE SIGNAL ;
    SHAPE ABUTMENT ;
    PORT
      LAYER M4 ;
      RECT 0.000 20.544 0.024 20.568 ;
    END
  END rd_out[197]
  PIN rd_out[198]
    DIRECTION OUTPUT ;
    USE SIGNAL ;
    SHAPE ABUTMENT ;
    PORT
      LAYER M4 ;
      RECT 0.000 20.640 0.024 20.664 ;
    END
  END rd_out[198]
  PIN rd_out[199]
    DIRECTION OUTPUT ;
    USE SIGNAL ;
    SHAPE ABUTMENT ;
    PORT
      LAYER M4 ;
      RECT 0.000 20.736 0.024 20.760 ;
    END
  END rd_out[199]
  PIN rd_out[200]
    DIRECTION OUTPUT ;
    USE SIGNAL ;
    SHAPE ABUTMENT ;
    PORT
      LAYER M4 ;
      RECT 0.000 20.832 0.024 20.856 ;
    END
  END rd_out[200]
  PIN rd_out[201]
    DIRECTION OUTPUT ;
    USE SIGNAL ;
    SHAPE ABUTMENT ;
    PORT
      LAYER M4 ;
      RECT 0.000 20.928 0.024 20.952 ;
    END
  END rd_out[201]
  PIN rd_out[202]
    DIRECTION OUTPUT ;
    USE SIGNAL ;
    SHAPE ABUTMENT ;
    PORT
      LAYER M4 ;
      RECT 0.000 21.024 0.024 21.048 ;
    END
  END rd_out[202]
  PIN rd_out[203]
    DIRECTION OUTPUT ;
    USE SIGNAL ;
    SHAPE ABUTMENT ;
    PORT
      LAYER M4 ;
      RECT 0.000 21.120 0.024 21.144 ;
    END
  END rd_out[203]
  PIN rd_out[204]
    DIRECTION OUTPUT ;
    USE SIGNAL ;
    SHAPE ABUTMENT ;
    PORT
      LAYER M4 ;
      RECT 0.000 21.216 0.024 21.240 ;
    END
  END rd_out[204]
  PIN rd_out[205]
    DIRECTION OUTPUT ;
    USE SIGNAL ;
    SHAPE ABUTMENT ;
    PORT
      LAYER M4 ;
      RECT 0.000 21.312 0.024 21.336 ;
    END
  END rd_out[205]
  PIN rd_out[206]
    DIRECTION OUTPUT ;
    USE SIGNAL ;
    SHAPE ABUTMENT ;
    PORT
      LAYER M4 ;
      RECT 0.000 21.408 0.024 21.432 ;
    END
  END rd_out[206]
  PIN rd_out[207]
    DIRECTION OUTPUT ;
    USE SIGNAL ;
    SHAPE ABUTMENT ;
    PORT
      LAYER M4 ;
      RECT 0.000 21.504 0.024 21.528 ;
    END
  END rd_out[207]
  PIN rd_out[208]
    DIRECTION OUTPUT ;
    USE SIGNAL ;
    SHAPE ABUTMENT ;
    PORT
      LAYER M4 ;
      RECT 0.000 21.600 0.024 21.624 ;
    END
  END rd_out[208]
  PIN rd_out[209]
    DIRECTION OUTPUT ;
    USE SIGNAL ;
    SHAPE ABUTMENT ;
    PORT
      LAYER M4 ;
      RECT 0.000 21.696 0.024 21.720 ;
    END
  END rd_out[209]
  PIN rd_out[210]
    DIRECTION OUTPUT ;
    USE SIGNAL ;
    SHAPE ABUTMENT ;
    PORT
      LAYER M4 ;
      RECT 0.000 21.792 0.024 21.816 ;
    END
  END rd_out[210]
  PIN rd_out[211]
    DIRECTION OUTPUT ;
    USE SIGNAL ;
    SHAPE ABUTMENT ;
    PORT
      LAYER M4 ;
      RECT 0.000 21.888 0.024 21.912 ;
    END
  END rd_out[211]
  PIN rd_out[212]
    DIRECTION OUTPUT ;
    USE SIGNAL ;
    SHAPE ABUTMENT ;
    PORT
      LAYER M4 ;
      RECT 0.000 21.984 0.024 22.008 ;
    END
  END rd_out[212]
  PIN rd_out[213]
    DIRECTION OUTPUT ;
    USE SIGNAL ;
    SHAPE ABUTMENT ;
    PORT
      LAYER M4 ;
      RECT 0.000 22.080 0.024 22.104 ;
    END
  END rd_out[213]
  PIN rd_out[214]
    DIRECTION OUTPUT ;
    USE SIGNAL ;
    SHAPE ABUTMENT ;
    PORT
      LAYER M4 ;
      RECT 0.000 22.176 0.024 22.200 ;
    END
  END rd_out[214]
  PIN rd_out[215]
    DIRECTION OUTPUT ;
    USE SIGNAL ;
    SHAPE ABUTMENT ;
    PORT
      LAYER M4 ;
      RECT 0.000 22.272 0.024 22.296 ;
    END
  END rd_out[215]
  PIN rd_out[216]
    DIRECTION OUTPUT ;
    USE SIGNAL ;
    SHAPE ABUTMENT ;
    PORT
      LAYER M4 ;
      RECT 0.000 22.368 0.024 22.392 ;
    END
  END rd_out[216]
  PIN rd_out[217]
    DIRECTION OUTPUT ;
    USE SIGNAL ;
    SHAPE ABUTMENT ;
    PORT
      LAYER M4 ;
      RECT 0.000 22.464 0.024 22.488 ;
    END
  END rd_out[217]
  PIN rd_out[218]
    DIRECTION OUTPUT ;
    USE SIGNAL ;
    SHAPE ABUTMENT ;
    PORT
      LAYER M4 ;
      RECT 0.000 22.560 0.024 22.584 ;
    END
  END rd_out[218]
  PIN rd_out[219]
    DIRECTION OUTPUT ;
    USE SIGNAL ;
    SHAPE ABUTMENT ;
    PORT
      LAYER M4 ;
      RECT 0.000 22.656 0.024 22.680 ;
    END
  END rd_out[219]
  PIN rd_out[220]
    DIRECTION OUTPUT ;
    USE SIGNAL ;
    SHAPE ABUTMENT ;
    PORT
      LAYER M4 ;
      RECT 0.000 22.752 0.024 22.776 ;
    END
  END rd_out[220]
  PIN rd_out[221]
    DIRECTION OUTPUT ;
    USE SIGNAL ;
    SHAPE ABUTMENT ;
    PORT
      LAYER M4 ;
      RECT 0.000 22.848 0.024 22.872 ;
    END
  END rd_out[221]
  PIN rd_out[222]
    DIRECTION OUTPUT ;
    USE SIGNAL ;
    SHAPE ABUTMENT ;
    PORT
      LAYER M4 ;
      RECT 0.000 22.944 0.024 22.968 ;
    END
  END rd_out[222]
  PIN rd_out[223]
    DIRECTION OUTPUT ;
    USE SIGNAL ;
    SHAPE ABUTMENT ;
    PORT
      LAYER M4 ;
      RECT 0.000 23.040 0.024 23.064 ;
    END
  END rd_out[223]
  PIN rd_out[224]
    DIRECTION OUTPUT ;
    USE SIGNAL ;
    SHAPE ABUTMENT ;
    PORT
      LAYER M4 ;
      RECT 0.000 23.136 0.024 23.160 ;
    END
  END rd_out[224]
  PIN rd_out[225]
    DIRECTION OUTPUT ;
    USE SIGNAL ;
    SHAPE ABUTMENT ;
    PORT
      LAYER M4 ;
      RECT 0.000 23.232 0.024 23.256 ;
    END
  END rd_out[225]
  PIN rd_out[226]
    DIRECTION OUTPUT ;
    USE SIGNAL ;
    SHAPE ABUTMENT ;
    PORT
      LAYER M4 ;
      RECT 0.000 23.328 0.024 23.352 ;
    END
  END rd_out[226]
  PIN rd_out[227]
    DIRECTION OUTPUT ;
    USE SIGNAL ;
    SHAPE ABUTMENT ;
    PORT
      LAYER M4 ;
      RECT 0.000 23.424 0.024 23.448 ;
    END
  END rd_out[227]
  PIN rd_out[228]
    DIRECTION OUTPUT ;
    USE SIGNAL ;
    SHAPE ABUTMENT ;
    PORT
      LAYER M4 ;
      RECT 0.000 23.520 0.024 23.544 ;
    END
  END rd_out[228]
  PIN rd_out[229]
    DIRECTION OUTPUT ;
    USE SIGNAL ;
    SHAPE ABUTMENT ;
    PORT
      LAYER M4 ;
      RECT 0.000 23.616 0.024 23.640 ;
    END
  END rd_out[229]
  PIN rd_out[230]
    DIRECTION OUTPUT ;
    USE SIGNAL ;
    SHAPE ABUTMENT ;
    PORT
      LAYER M4 ;
      RECT 0.000 23.712 0.024 23.736 ;
    END
  END rd_out[230]
  PIN rd_out[231]
    DIRECTION OUTPUT ;
    USE SIGNAL ;
    SHAPE ABUTMENT ;
    PORT
      LAYER M4 ;
      RECT 0.000 23.808 0.024 23.832 ;
    END
  END rd_out[231]
  PIN rd_out[232]
    DIRECTION OUTPUT ;
    USE SIGNAL ;
    SHAPE ABUTMENT ;
    PORT
      LAYER M4 ;
      RECT 0.000 23.904 0.024 23.928 ;
    END
  END rd_out[232]
  PIN rd_out[233]
    DIRECTION OUTPUT ;
    USE SIGNAL ;
    SHAPE ABUTMENT ;
    PORT
      LAYER M4 ;
      RECT 0.000 24.000 0.024 24.024 ;
    END
  END rd_out[233]
  PIN rd_out[234]
    DIRECTION OUTPUT ;
    USE SIGNAL ;
    SHAPE ABUTMENT ;
    PORT
      LAYER M4 ;
      RECT 0.000 24.096 0.024 24.120 ;
    END
  END rd_out[234]
  PIN rd_out[235]
    DIRECTION OUTPUT ;
    USE SIGNAL ;
    SHAPE ABUTMENT ;
    PORT
      LAYER M4 ;
      RECT 0.000 24.192 0.024 24.216 ;
    END
  END rd_out[235]
  PIN rd_out[236]
    DIRECTION OUTPUT ;
    USE SIGNAL ;
    SHAPE ABUTMENT ;
    PORT
      LAYER M4 ;
      RECT 0.000 24.288 0.024 24.312 ;
    END
  END rd_out[236]
  PIN rd_out[237]
    DIRECTION OUTPUT ;
    USE SIGNAL ;
    SHAPE ABUTMENT ;
    PORT
      LAYER M4 ;
      RECT 0.000 24.384 0.024 24.408 ;
    END
  END rd_out[237]
  PIN rd_out[238]
    DIRECTION OUTPUT ;
    USE SIGNAL ;
    SHAPE ABUTMENT ;
    PORT
      LAYER M4 ;
      RECT 0.000 24.480 0.024 24.504 ;
    END
  END rd_out[238]
  PIN rd_out[239]
    DIRECTION OUTPUT ;
    USE SIGNAL ;
    SHAPE ABUTMENT ;
    PORT
      LAYER M4 ;
      RECT 0.000 24.576 0.024 24.600 ;
    END
  END rd_out[239]
  PIN rd_out[240]
    DIRECTION OUTPUT ;
    USE SIGNAL ;
    SHAPE ABUTMENT ;
    PORT
      LAYER M4 ;
      RECT 0.000 24.672 0.024 24.696 ;
    END
  END rd_out[240]
  PIN rd_out[241]
    DIRECTION OUTPUT ;
    USE SIGNAL ;
    SHAPE ABUTMENT ;
    PORT
      LAYER M4 ;
      RECT 0.000 24.768 0.024 24.792 ;
    END
  END rd_out[241]
  PIN rd_out[242]
    DIRECTION OUTPUT ;
    USE SIGNAL ;
    SHAPE ABUTMENT ;
    PORT
      LAYER M4 ;
      RECT 0.000 24.864 0.024 24.888 ;
    END
  END rd_out[242]
  PIN rd_out[243]
    DIRECTION OUTPUT ;
    USE SIGNAL ;
    SHAPE ABUTMENT ;
    PORT
      LAYER M4 ;
      RECT 0.000 24.960 0.024 24.984 ;
    END
  END rd_out[243]
  PIN rd_out[244]
    DIRECTION OUTPUT ;
    USE SIGNAL ;
    SHAPE ABUTMENT ;
    PORT
      LAYER M4 ;
      RECT 0.000 25.056 0.024 25.080 ;
    END
  END rd_out[244]
  PIN rd_out[245]
    DIRECTION OUTPUT ;
    USE SIGNAL ;
    SHAPE ABUTMENT ;
    PORT
      LAYER M4 ;
      RECT 0.000 25.152 0.024 25.176 ;
    END
  END rd_out[245]
  PIN rd_out[246]
    DIRECTION OUTPUT ;
    USE SIGNAL ;
    SHAPE ABUTMENT ;
    PORT
      LAYER M4 ;
      RECT 0.000 25.248 0.024 25.272 ;
    END
  END rd_out[246]
  PIN rd_out[247]
    DIRECTION OUTPUT ;
    USE SIGNAL ;
    SHAPE ABUTMENT ;
    PORT
      LAYER M4 ;
      RECT 0.000 25.344 0.024 25.368 ;
    END
  END rd_out[247]
  PIN rd_out[248]
    DIRECTION OUTPUT ;
    USE SIGNAL ;
    SHAPE ABUTMENT ;
    PORT
      LAYER M4 ;
      RECT 0.000 25.440 0.024 25.464 ;
    END
  END rd_out[248]
  PIN rd_out[249]
    DIRECTION OUTPUT ;
    USE SIGNAL ;
    SHAPE ABUTMENT ;
    PORT
      LAYER M4 ;
      RECT 0.000 25.536 0.024 25.560 ;
    END
  END rd_out[249]
  PIN rd_out[250]
    DIRECTION OUTPUT ;
    USE SIGNAL ;
    SHAPE ABUTMENT ;
    PORT
      LAYER M4 ;
      RECT 0.000 25.632 0.024 25.656 ;
    END
  END rd_out[250]
  PIN rd_out[251]
    DIRECTION OUTPUT ;
    USE SIGNAL ;
    SHAPE ABUTMENT ;
    PORT
      LAYER M4 ;
      RECT 0.000 25.728 0.024 25.752 ;
    END
  END rd_out[251]
  PIN rd_out[252]
    DIRECTION OUTPUT ;
    USE SIGNAL ;
    SHAPE ABUTMENT ;
    PORT
      LAYER M4 ;
      RECT 0.000 25.824 0.024 25.848 ;
    END
  END rd_out[252]
  PIN rd_out[253]
    DIRECTION OUTPUT ;
    USE SIGNAL ;
    SHAPE ABUTMENT ;
    PORT
      LAYER M4 ;
      RECT 0.000 25.920 0.024 25.944 ;
    END
  END rd_out[253]
  PIN rd_out[254]
    DIRECTION OUTPUT ;
    USE SIGNAL ;
    SHAPE ABUTMENT ;
    PORT
      LAYER M4 ;
      RECT 0.000 26.016 0.024 26.040 ;
    END
  END rd_out[254]
  PIN rd_out[255]
    DIRECTION OUTPUT ;
    USE SIGNAL ;
    SHAPE ABUTMENT ;
    PORT
      LAYER M4 ;
      RECT 0.000 26.112 0.024 26.136 ;
    END
  END rd_out[255]
  PIN w_ce_in
    DIRECTION INPUT ;
    USE SIGNAL ;
    SHAPE ABUTMENT ;
    PORT
      LAYER M4 ;
      RECT 0.000 26.208 0.024 26.232 ;
    END
  END w_ce_in
  PIN w_addr_in[0]
    DIRECTION INPUT ;
    USE SIGNAL ;
    SHAPE ABUTMENT ;
    PORT
      LAYER M4 ;
      RECT 0.000 26.304 0.024 26.328 ;
    END
  END w_addr_in[0]
  PIN w_addr_in[1]
    DIRECTION INPUT ;
    USE SIGNAL ;
    SHAPE ABUTMENT ;
    PORT
      LAYER M4 ;
      RECT 0.000 26.400 0.024 26.424 ;
    END
  END w_addr_in[1]
  PIN w_addr_in[2]
    DIRECTION INPUT ;
    USE SIGNAL ;
    SHAPE ABUTMENT ;
    PORT
      LAYER M4 ;
      RECT 0.000 26.496 0.024 26.520 ;
    END
  END w_addr_in[2]
  PIN w_addr_in[3]
    DIRECTION INPUT ;
    USE SIGNAL ;
    SHAPE ABUTMENT ;
    PORT
      LAYER M4 ;
      RECT 0.000 26.592 0.024 26.616 ;
    END
  END w_addr_in[3]
  PIN w_addr_in[4]
    DIRECTION INPUT ;
    USE SIGNAL ;
    SHAPE ABUTMENT ;
    PORT
      LAYER M4 ;
      RECT 0.000 26.688 0.024 26.712 ;
    END
  END w_addr_in[4]
  PIN w_addr_in[5]
    DIRECTION INPUT ;
    USE SIGNAL ;
    SHAPE ABUTMENT ;
    PORT
      LAYER M4 ;
      RECT 0.000 26.784 0.024 26.808 ;
    END
  END w_addr_in[5]
  PIN w_addr_in[6]
    DIRECTION INPUT ;
    USE SIGNAL ;
    SHAPE ABUTMENT ;
    PORT
      LAYER M4 ;
      RECT 0.000 26.880 0.024 26.904 ;
    END
  END w_addr_in[6]
  PIN wd_in[0]
    DIRECTION INPUT ;
    USE SIGNAL ;
    SHAPE ABUTMENT ;
    PORT
      LAYER M4 ;
      RECT 0.000 26.976 0.024 27.000 ;
    END
  END wd_in[0]
  PIN wd_in[1]
    DIRECTION INPUT ;
    USE SIGNAL ;
    SHAPE ABUTMENT ;
    PORT
      LAYER M4 ;
      RECT 0.000 27.072 0.024 27.096 ;
    END
  END wd_in[1]
  PIN wd_in[2]
    DIRECTION INPUT ;
    USE SIGNAL ;
    SHAPE ABUTMENT ;
    PORT
      LAYER M4 ;
      RECT 0.000 27.168 0.024 27.192 ;
    END
  END wd_in[2]
  PIN wd_in[3]
    DIRECTION INPUT ;
    USE SIGNAL ;
    SHAPE ABUTMENT ;
    PORT
      LAYER M4 ;
      RECT 0.000 27.264 0.024 27.288 ;
    END
  END wd_in[3]
  PIN wd_in[4]
    DIRECTION INPUT ;
    USE SIGNAL ;
    SHAPE ABUTMENT ;
    PORT
      LAYER M4 ;
      RECT 0.000 27.360 0.024 27.384 ;
    END
  END wd_in[4]
  PIN wd_in[5]
    DIRECTION INPUT ;
    USE SIGNAL ;
    SHAPE ABUTMENT ;
    PORT
      LAYER M4 ;
      RECT 0.000 27.456 0.024 27.480 ;
    END
  END wd_in[5]
  PIN wd_in[6]
    DIRECTION INPUT ;
    USE SIGNAL ;
    SHAPE ABUTMENT ;
    PORT
      LAYER M4 ;
      RECT 0.000 27.552 0.024 27.576 ;
    END
  END wd_in[6]
  PIN wd_in[7]
    DIRECTION INPUT ;
    USE SIGNAL ;
    SHAPE ABUTMENT ;
    PORT
      LAYER M4 ;
      RECT 0.000 27.648 0.024 27.672 ;
    END
  END wd_in[7]
  PIN wd_in[8]
    DIRECTION INPUT ;
    USE SIGNAL ;
    SHAPE ABUTMENT ;
    PORT
      LAYER M4 ;
      RECT 0.000 27.744 0.024 27.768 ;
    END
  END wd_in[8]
  PIN wd_in[9]
    DIRECTION INPUT ;
    USE SIGNAL ;
    SHAPE ABUTMENT ;
    PORT
      LAYER M4 ;
      RECT 0.000 27.840 0.024 27.864 ;
    END
  END wd_in[9]
  PIN wd_in[10]
    DIRECTION INPUT ;
    USE SIGNAL ;
    SHAPE ABUTMENT ;
    PORT
      LAYER M4 ;
      RECT 0.000 27.936 0.024 27.960 ;
    END
  END wd_in[10]
  PIN wd_in[11]
    DIRECTION INPUT ;
    USE SIGNAL ;
    SHAPE ABUTMENT ;
    PORT
      LAYER M4 ;
      RECT 0.000 28.032 0.024 28.056 ;
    END
  END wd_in[11]
  PIN wd_in[12]
    DIRECTION INPUT ;
    USE SIGNAL ;
    SHAPE ABUTMENT ;
    PORT
      LAYER M4 ;
      RECT 0.000 28.128 0.024 28.152 ;
    END
  END wd_in[12]
  PIN wd_in[13]
    DIRECTION INPUT ;
    USE SIGNAL ;
    SHAPE ABUTMENT ;
    PORT
      LAYER M4 ;
      RECT 0.000 28.224 0.024 28.248 ;
    END
  END wd_in[13]
  PIN wd_in[14]
    DIRECTION INPUT ;
    USE SIGNAL ;
    SHAPE ABUTMENT ;
    PORT
      LAYER M4 ;
      RECT 0.000 28.320 0.024 28.344 ;
    END
  END wd_in[14]
  PIN wd_in[15]
    DIRECTION INPUT ;
    USE SIGNAL ;
    SHAPE ABUTMENT ;
    PORT
      LAYER M4 ;
      RECT 0.000 28.416 0.024 28.440 ;
    END
  END wd_in[15]
  PIN wd_in[16]
    DIRECTION INPUT ;
    USE SIGNAL ;
    SHAPE ABUTMENT ;
    PORT
      LAYER M4 ;
      RECT 0.000 28.512 0.024 28.536 ;
    END
  END wd_in[16]
  PIN wd_in[17]
    DIRECTION INPUT ;
    USE SIGNAL ;
    SHAPE ABUTMENT ;
    PORT
      LAYER M4 ;
      RECT 0.000 28.608 0.024 28.632 ;
    END
  END wd_in[17]
  PIN wd_in[18]
    DIRECTION INPUT ;
    USE SIGNAL ;
    SHAPE ABUTMENT ;
    PORT
      LAYER M4 ;
      RECT 0.000 28.704 0.024 28.728 ;
    END
  END wd_in[18]
  PIN wd_in[19]
    DIRECTION INPUT ;
    USE SIGNAL ;
    SHAPE ABUTMENT ;
    PORT
      LAYER M4 ;
      RECT 0.000 28.800 0.024 28.824 ;
    END
  END wd_in[19]
  PIN wd_in[20]
    DIRECTION INPUT ;
    USE SIGNAL ;
    SHAPE ABUTMENT ;
    PORT
      LAYER M4 ;
      RECT 0.000 28.896 0.024 28.920 ;
    END
  END wd_in[20]
  PIN wd_in[21]
    DIRECTION INPUT ;
    USE SIGNAL ;
    SHAPE ABUTMENT ;
    PORT
      LAYER M4 ;
      RECT 0.000 28.992 0.024 29.016 ;
    END
  END wd_in[21]
  PIN wd_in[22]
    DIRECTION INPUT ;
    USE SIGNAL ;
    SHAPE ABUTMENT ;
    PORT
      LAYER M4 ;
      RECT 0.000 29.088 0.024 29.112 ;
    END
  END wd_in[22]
  PIN wd_in[23]
    DIRECTION INPUT ;
    USE SIGNAL ;
    SHAPE ABUTMENT ;
    PORT
      LAYER M4 ;
      RECT 0.000 29.184 0.024 29.208 ;
    END
  END wd_in[23]
  PIN wd_in[24]
    DIRECTION INPUT ;
    USE SIGNAL ;
    SHAPE ABUTMENT ;
    PORT
      LAYER M4 ;
      RECT 0.000 29.280 0.024 29.304 ;
    END
  END wd_in[24]
  PIN wd_in[25]
    DIRECTION INPUT ;
    USE SIGNAL ;
    SHAPE ABUTMENT ;
    PORT
      LAYER M4 ;
      RECT 0.000 29.376 0.024 29.400 ;
    END
  END wd_in[25]
  PIN wd_in[26]
    DIRECTION INPUT ;
    USE SIGNAL ;
    SHAPE ABUTMENT ;
    PORT
      LAYER M4 ;
      RECT 0.000 29.472 0.024 29.496 ;
    END
  END wd_in[26]
  PIN wd_in[27]
    DIRECTION INPUT ;
    USE SIGNAL ;
    SHAPE ABUTMENT ;
    PORT
      LAYER M4 ;
      RECT 0.000 29.568 0.024 29.592 ;
    END
  END wd_in[27]
  PIN wd_in[28]
    DIRECTION INPUT ;
    USE SIGNAL ;
    SHAPE ABUTMENT ;
    PORT
      LAYER M4 ;
      RECT 0.000 29.664 0.024 29.688 ;
    END
  END wd_in[28]
  PIN wd_in[29]
    DIRECTION INPUT ;
    USE SIGNAL ;
    SHAPE ABUTMENT ;
    PORT
      LAYER M4 ;
      RECT 0.000 29.760 0.024 29.784 ;
    END
  END wd_in[29]
  PIN wd_in[30]
    DIRECTION INPUT ;
    USE SIGNAL ;
    SHAPE ABUTMENT ;
    PORT
      LAYER M4 ;
      RECT 0.000 29.856 0.024 29.880 ;
    END
  END wd_in[30]
  PIN wd_in[31]
    DIRECTION INPUT ;
    USE SIGNAL ;
    SHAPE ABUTMENT ;
    PORT
      LAYER M4 ;
      RECT 0.000 29.952 0.024 29.976 ;
    END
  END wd_in[31]
  PIN wd_in[32]
    DIRECTION INPUT ;
    USE SIGNAL ;
    SHAPE ABUTMENT ;
    PORT
      LAYER M4 ;
      RECT 0.000 30.048 0.024 30.072 ;
    END
  END wd_in[32]
  PIN wd_in[33]
    DIRECTION INPUT ;
    USE SIGNAL ;
    SHAPE ABUTMENT ;
    PORT
      LAYER M4 ;
      RECT 0.000 30.144 0.024 30.168 ;
    END
  END wd_in[33]
  PIN wd_in[34]
    DIRECTION INPUT ;
    USE SIGNAL ;
    SHAPE ABUTMENT ;
    PORT
      LAYER M4 ;
      RECT 0.000 30.240 0.024 30.264 ;
    END
  END wd_in[34]
  PIN wd_in[35]
    DIRECTION INPUT ;
    USE SIGNAL ;
    SHAPE ABUTMENT ;
    PORT
      LAYER M4 ;
      RECT 0.000 30.336 0.024 30.360 ;
    END
  END wd_in[35]
  PIN wd_in[36]
    DIRECTION INPUT ;
    USE SIGNAL ;
    SHAPE ABUTMENT ;
    PORT
      LAYER M4 ;
      RECT 0.000 30.432 0.024 30.456 ;
    END
  END wd_in[36]
  PIN wd_in[37]
    DIRECTION INPUT ;
    USE SIGNAL ;
    SHAPE ABUTMENT ;
    PORT
      LAYER M4 ;
      RECT 0.000 30.528 0.024 30.552 ;
    END
  END wd_in[37]
  PIN wd_in[38]
    DIRECTION INPUT ;
    USE SIGNAL ;
    SHAPE ABUTMENT ;
    PORT
      LAYER M4 ;
      RECT 0.000 30.624 0.024 30.648 ;
    END
  END wd_in[38]
  PIN wd_in[39]
    DIRECTION INPUT ;
    USE SIGNAL ;
    SHAPE ABUTMENT ;
    PORT
      LAYER M4 ;
      RECT 0.000 30.720 0.024 30.744 ;
    END
  END wd_in[39]
  PIN wd_in[40]
    DIRECTION INPUT ;
    USE SIGNAL ;
    SHAPE ABUTMENT ;
    PORT
      LAYER M4 ;
      RECT 0.000 30.816 0.024 30.840 ;
    END
  END wd_in[40]
  PIN wd_in[41]
    DIRECTION INPUT ;
    USE SIGNAL ;
    SHAPE ABUTMENT ;
    PORT
      LAYER M4 ;
      RECT 0.000 30.912 0.024 30.936 ;
    END
  END wd_in[41]
  PIN wd_in[42]
    DIRECTION INPUT ;
    USE SIGNAL ;
    SHAPE ABUTMENT ;
    PORT
      LAYER M4 ;
      RECT 0.000 31.008 0.024 31.032 ;
    END
  END wd_in[42]
  PIN wd_in[43]
    DIRECTION INPUT ;
    USE SIGNAL ;
    SHAPE ABUTMENT ;
    PORT
      LAYER M4 ;
      RECT 0.000 31.104 0.024 31.128 ;
    END
  END wd_in[43]
  PIN wd_in[44]
    DIRECTION INPUT ;
    USE SIGNAL ;
    SHAPE ABUTMENT ;
    PORT
      LAYER M4 ;
      RECT 0.000 31.200 0.024 31.224 ;
    END
  END wd_in[44]
  PIN wd_in[45]
    DIRECTION INPUT ;
    USE SIGNAL ;
    SHAPE ABUTMENT ;
    PORT
      LAYER M4 ;
      RECT 0.000 31.296 0.024 31.320 ;
    END
  END wd_in[45]
  PIN wd_in[46]
    DIRECTION INPUT ;
    USE SIGNAL ;
    SHAPE ABUTMENT ;
    PORT
      LAYER M4 ;
      RECT 0.000 31.392 0.024 31.416 ;
    END
  END wd_in[46]
  PIN wd_in[47]
    DIRECTION INPUT ;
    USE SIGNAL ;
    SHAPE ABUTMENT ;
    PORT
      LAYER M4 ;
      RECT 0.000 31.488 0.024 31.512 ;
    END
  END wd_in[47]
  PIN wd_in[48]
    DIRECTION INPUT ;
    USE SIGNAL ;
    SHAPE ABUTMENT ;
    PORT
      LAYER M4 ;
      RECT 0.000 31.584 0.024 31.608 ;
    END
  END wd_in[48]
  PIN wd_in[49]
    DIRECTION INPUT ;
    USE SIGNAL ;
    SHAPE ABUTMENT ;
    PORT
      LAYER M4 ;
      RECT 0.000 31.680 0.024 31.704 ;
    END
  END wd_in[49]
  PIN wd_in[50]
    DIRECTION INPUT ;
    USE SIGNAL ;
    SHAPE ABUTMENT ;
    PORT
      LAYER M4 ;
      RECT 0.000 31.776 0.024 31.800 ;
    END
  END wd_in[50]
  PIN wd_in[51]
    DIRECTION INPUT ;
    USE SIGNAL ;
    SHAPE ABUTMENT ;
    PORT
      LAYER M4 ;
      RECT 0.000 31.872 0.024 31.896 ;
    END
  END wd_in[51]
  PIN wd_in[52]
    DIRECTION INPUT ;
    USE SIGNAL ;
    SHAPE ABUTMENT ;
    PORT
      LAYER M4 ;
      RECT 0.000 31.968 0.024 31.992 ;
    END
  END wd_in[52]
  PIN wd_in[53]
    DIRECTION INPUT ;
    USE SIGNAL ;
    SHAPE ABUTMENT ;
    PORT
      LAYER M4 ;
      RECT 0.000 32.064 0.024 32.088 ;
    END
  END wd_in[53]
  PIN wd_in[54]
    DIRECTION INPUT ;
    USE SIGNAL ;
    SHAPE ABUTMENT ;
    PORT
      LAYER M4 ;
      RECT 0.000 32.160 0.024 32.184 ;
    END
  END wd_in[54]
  PIN wd_in[55]
    DIRECTION INPUT ;
    USE SIGNAL ;
    SHAPE ABUTMENT ;
    PORT
      LAYER M4 ;
      RECT 0.000 32.256 0.024 32.280 ;
    END
  END wd_in[55]
  PIN wd_in[56]
    DIRECTION INPUT ;
    USE SIGNAL ;
    SHAPE ABUTMENT ;
    PORT
      LAYER M4 ;
      RECT 0.000 32.352 0.024 32.376 ;
    END
  END wd_in[56]
  PIN wd_in[57]
    DIRECTION INPUT ;
    USE SIGNAL ;
    SHAPE ABUTMENT ;
    PORT
      LAYER M4 ;
      RECT 0.000 32.448 0.024 32.472 ;
    END
  END wd_in[57]
  PIN wd_in[58]
    DIRECTION INPUT ;
    USE SIGNAL ;
    SHAPE ABUTMENT ;
    PORT
      LAYER M4 ;
      RECT 0.000 32.544 0.024 32.568 ;
    END
  END wd_in[58]
  PIN wd_in[59]
    DIRECTION INPUT ;
    USE SIGNAL ;
    SHAPE ABUTMENT ;
    PORT
      LAYER M4 ;
      RECT 0.000 32.640 0.024 32.664 ;
    END
  END wd_in[59]
  PIN wd_in[60]
    DIRECTION INPUT ;
    USE SIGNAL ;
    SHAPE ABUTMENT ;
    PORT
      LAYER M4 ;
      RECT 0.000 32.736 0.024 32.760 ;
    END
  END wd_in[60]
  PIN wd_in[61]
    DIRECTION INPUT ;
    USE SIGNAL ;
    SHAPE ABUTMENT ;
    PORT
      LAYER M4 ;
      RECT 0.000 32.832 0.024 32.856 ;
    END
  END wd_in[61]
  PIN wd_in[62]
    DIRECTION INPUT ;
    USE SIGNAL ;
    SHAPE ABUTMENT ;
    PORT
      LAYER M4 ;
      RECT 0.000 32.928 0.024 32.952 ;
    END
  END wd_in[62]
  PIN wd_in[63]
    DIRECTION INPUT ;
    USE SIGNAL ;
    SHAPE ABUTMENT ;
    PORT
      LAYER M4 ;
      RECT 0.000 33.024 0.024 33.048 ;
    END
  END wd_in[63]
  PIN wd_in[64]
    DIRECTION INPUT ;
    USE SIGNAL ;
    SHAPE ABUTMENT ;
    PORT
      LAYER M4 ;
      RECT 0.000 33.120 0.024 33.144 ;
    END
  END wd_in[64]
  PIN wd_in[65]
    DIRECTION INPUT ;
    USE SIGNAL ;
    SHAPE ABUTMENT ;
    PORT
      LAYER M4 ;
      RECT 0.000 33.216 0.024 33.240 ;
    END
  END wd_in[65]
  PIN wd_in[66]
    DIRECTION INPUT ;
    USE SIGNAL ;
    SHAPE ABUTMENT ;
    PORT
      LAYER M4 ;
      RECT 0.000 33.312 0.024 33.336 ;
    END
  END wd_in[66]
  PIN wd_in[67]
    DIRECTION INPUT ;
    USE SIGNAL ;
    SHAPE ABUTMENT ;
    PORT
      LAYER M4 ;
      RECT 0.000 33.408 0.024 33.432 ;
    END
  END wd_in[67]
  PIN wd_in[68]
    DIRECTION INPUT ;
    USE SIGNAL ;
    SHAPE ABUTMENT ;
    PORT
      LAYER M4 ;
      RECT 0.000 33.504 0.024 33.528 ;
    END
  END wd_in[68]
  PIN wd_in[69]
    DIRECTION INPUT ;
    USE SIGNAL ;
    SHAPE ABUTMENT ;
    PORT
      LAYER M4 ;
      RECT 0.000 33.600 0.024 33.624 ;
    END
  END wd_in[69]
  PIN wd_in[70]
    DIRECTION INPUT ;
    USE SIGNAL ;
    SHAPE ABUTMENT ;
    PORT
      LAYER M4 ;
      RECT 0.000 33.696 0.024 33.720 ;
    END
  END wd_in[70]
  PIN wd_in[71]
    DIRECTION INPUT ;
    USE SIGNAL ;
    SHAPE ABUTMENT ;
    PORT
      LAYER M4 ;
      RECT 0.000 33.792 0.024 33.816 ;
    END
  END wd_in[71]
  PIN wd_in[72]
    DIRECTION INPUT ;
    USE SIGNAL ;
    SHAPE ABUTMENT ;
    PORT
      LAYER M4 ;
      RECT 0.000 33.888 0.024 33.912 ;
    END
  END wd_in[72]
  PIN wd_in[73]
    DIRECTION INPUT ;
    USE SIGNAL ;
    SHAPE ABUTMENT ;
    PORT
      LAYER M4 ;
      RECT 0.000 33.984 0.024 34.008 ;
    END
  END wd_in[73]
  PIN wd_in[74]
    DIRECTION INPUT ;
    USE SIGNAL ;
    SHAPE ABUTMENT ;
    PORT
      LAYER M4 ;
      RECT 0.000 34.080 0.024 34.104 ;
    END
  END wd_in[74]
  PIN wd_in[75]
    DIRECTION INPUT ;
    USE SIGNAL ;
    SHAPE ABUTMENT ;
    PORT
      LAYER M4 ;
      RECT 0.000 34.176 0.024 34.200 ;
    END
  END wd_in[75]
  PIN wd_in[76]
    DIRECTION INPUT ;
    USE SIGNAL ;
    SHAPE ABUTMENT ;
    PORT
      LAYER M4 ;
      RECT 0.000 34.272 0.024 34.296 ;
    END
  END wd_in[76]
  PIN wd_in[77]
    DIRECTION INPUT ;
    USE SIGNAL ;
    SHAPE ABUTMENT ;
    PORT
      LAYER M4 ;
      RECT 0.000 34.368 0.024 34.392 ;
    END
  END wd_in[77]
  PIN wd_in[78]
    DIRECTION INPUT ;
    USE SIGNAL ;
    SHAPE ABUTMENT ;
    PORT
      LAYER M4 ;
      RECT 0.000 34.464 0.024 34.488 ;
    END
  END wd_in[78]
  PIN wd_in[79]
    DIRECTION INPUT ;
    USE SIGNAL ;
    SHAPE ABUTMENT ;
    PORT
      LAYER M4 ;
      RECT 0.000 34.560 0.024 34.584 ;
    END
  END wd_in[79]
  PIN wd_in[80]
    DIRECTION INPUT ;
    USE SIGNAL ;
    SHAPE ABUTMENT ;
    PORT
      LAYER M4 ;
      RECT 0.000 34.656 0.024 34.680 ;
    END
  END wd_in[80]
  PIN wd_in[81]
    DIRECTION INPUT ;
    USE SIGNAL ;
    SHAPE ABUTMENT ;
    PORT
      LAYER M4 ;
      RECT 0.000 34.752 0.024 34.776 ;
    END
  END wd_in[81]
  PIN wd_in[82]
    DIRECTION INPUT ;
    USE SIGNAL ;
    SHAPE ABUTMENT ;
    PORT
      LAYER M4 ;
      RECT 0.000 34.848 0.024 34.872 ;
    END
  END wd_in[82]
  PIN wd_in[83]
    DIRECTION INPUT ;
    USE SIGNAL ;
    SHAPE ABUTMENT ;
    PORT
      LAYER M4 ;
      RECT 0.000 34.944 0.024 34.968 ;
    END
  END wd_in[83]
  PIN wd_in[84]
    DIRECTION INPUT ;
    USE SIGNAL ;
    SHAPE ABUTMENT ;
    PORT
      LAYER M4 ;
      RECT 0.000 35.040 0.024 35.064 ;
    END
  END wd_in[84]
  PIN wd_in[85]
    DIRECTION INPUT ;
    USE SIGNAL ;
    SHAPE ABUTMENT ;
    PORT
      LAYER M4 ;
      RECT 0.000 35.136 0.024 35.160 ;
    END
  END wd_in[85]
  PIN wd_in[86]
    DIRECTION INPUT ;
    USE SIGNAL ;
    SHAPE ABUTMENT ;
    PORT
      LAYER M4 ;
      RECT 0.000 35.232 0.024 35.256 ;
    END
  END wd_in[86]
  PIN wd_in[87]
    DIRECTION INPUT ;
    USE SIGNAL ;
    SHAPE ABUTMENT ;
    PORT
      LAYER M4 ;
      RECT 0.000 35.328 0.024 35.352 ;
    END
  END wd_in[87]
  PIN wd_in[88]
    DIRECTION INPUT ;
    USE SIGNAL ;
    SHAPE ABUTMENT ;
    PORT
      LAYER M4 ;
      RECT 0.000 35.424 0.024 35.448 ;
    END
  END wd_in[88]
  PIN wd_in[89]
    DIRECTION INPUT ;
    USE SIGNAL ;
    SHAPE ABUTMENT ;
    PORT
      LAYER M4 ;
      RECT 0.000 35.520 0.024 35.544 ;
    END
  END wd_in[89]
  PIN wd_in[90]
    DIRECTION INPUT ;
    USE SIGNAL ;
    SHAPE ABUTMENT ;
    PORT
      LAYER M4 ;
      RECT 0.000 35.616 0.024 35.640 ;
    END
  END wd_in[90]
  PIN wd_in[91]
    DIRECTION INPUT ;
    USE SIGNAL ;
    SHAPE ABUTMENT ;
    PORT
      LAYER M4 ;
      RECT 0.000 35.712 0.024 35.736 ;
    END
  END wd_in[91]
  PIN wd_in[92]
    DIRECTION INPUT ;
    USE SIGNAL ;
    SHAPE ABUTMENT ;
    PORT
      LAYER M4 ;
      RECT 0.000 35.808 0.024 35.832 ;
    END
  END wd_in[92]
  PIN wd_in[93]
    DIRECTION INPUT ;
    USE SIGNAL ;
    SHAPE ABUTMENT ;
    PORT
      LAYER M4 ;
      RECT 0.000 35.904 0.024 35.928 ;
    END
  END wd_in[93]
  PIN wd_in[94]
    DIRECTION INPUT ;
    USE SIGNAL ;
    SHAPE ABUTMENT ;
    PORT
      LAYER M4 ;
      RECT 0.000 36.000 0.024 36.024 ;
    END
  END wd_in[94]
  PIN wd_in[95]
    DIRECTION INPUT ;
    USE SIGNAL ;
    SHAPE ABUTMENT ;
    PORT
      LAYER M4 ;
      RECT 0.000 36.096 0.024 36.120 ;
    END
  END wd_in[95]
  PIN wd_in[96]
    DIRECTION INPUT ;
    USE SIGNAL ;
    SHAPE ABUTMENT ;
    PORT
      LAYER M4 ;
      RECT 0.000 36.192 0.024 36.216 ;
    END
  END wd_in[96]
  PIN wd_in[97]
    DIRECTION INPUT ;
    USE SIGNAL ;
    SHAPE ABUTMENT ;
    PORT
      LAYER M4 ;
      RECT 0.000 36.288 0.024 36.312 ;
    END
  END wd_in[97]
  PIN wd_in[98]
    DIRECTION INPUT ;
    USE SIGNAL ;
    SHAPE ABUTMENT ;
    PORT
      LAYER M4 ;
      RECT 0.000 36.384 0.024 36.408 ;
    END
  END wd_in[98]
  PIN wd_in[99]
    DIRECTION INPUT ;
    USE SIGNAL ;
    SHAPE ABUTMENT ;
    PORT
      LAYER M4 ;
      RECT 0.000 36.480 0.024 36.504 ;
    END
  END wd_in[99]
  PIN wd_in[100]
    DIRECTION INPUT ;
    USE SIGNAL ;
    SHAPE ABUTMENT ;
    PORT
      LAYER M4 ;
      RECT 0.000 36.576 0.024 36.600 ;
    END
  END wd_in[100]
  PIN wd_in[101]
    DIRECTION INPUT ;
    USE SIGNAL ;
    SHAPE ABUTMENT ;
    PORT
      LAYER M4 ;
      RECT 0.000 36.672 0.024 36.696 ;
    END
  END wd_in[101]
  PIN wd_in[102]
    DIRECTION INPUT ;
    USE SIGNAL ;
    SHAPE ABUTMENT ;
    PORT
      LAYER M4 ;
      RECT 0.000 36.768 0.024 36.792 ;
    END
  END wd_in[102]
  PIN wd_in[103]
    DIRECTION INPUT ;
    USE SIGNAL ;
    SHAPE ABUTMENT ;
    PORT
      LAYER M4 ;
      RECT 0.000 36.864 0.024 36.888 ;
    END
  END wd_in[103]
  PIN wd_in[104]
    DIRECTION INPUT ;
    USE SIGNAL ;
    SHAPE ABUTMENT ;
    PORT
      LAYER M4 ;
      RECT 0.000 36.960 0.024 36.984 ;
    END
  END wd_in[104]
  PIN wd_in[105]
    DIRECTION INPUT ;
    USE SIGNAL ;
    SHAPE ABUTMENT ;
    PORT
      LAYER M4 ;
      RECT 0.000 37.056 0.024 37.080 ;
    END
  END wd_in[105]
  PIN wd_in[106]
    DIRECTION INPUT ;
    USE SIGNAL ;
    SHAPE ABUTMENT ;
    PORT
      LAYER M4 ;
      RECT 0.000 37.152 0.024 37.176 ;
    END
  END wd_in[106]
  PIN wd_in[107]
    DIRECTION INPUT ;
    USE SIGNAL ;
    SHAPE ABUTMENT ;
    PORT
      LAYER M4 ;
      RECT 0.000 37.248 0.024 37.272 ;
    END
  END wd_in[107]
  PIN wd_in[108]
    DIRECTION INPUT ;
    USE SIGNAL ;
    SHAPE ABUTMENT ;
    PORT
      LAYER M4 ;
      RECT 0.000 37.344 0.024 37.368 ;
    END
  END wd_in[108]
  PIN wd_in[109]
    DIRECTION INPUT ;
    USE SIGNAL ;
    SHAPE ABUTMENT ;
    PORT
      LAYER M4 ;
      RECT 0.000 37.440 0.024 37.464 ;
    END
  END wd_in[109]
  PIN wd_in[110]
    DIRECTION INPUT ;
    USE SIGNAL ;
    SHAPE ABUTMENT ;
    PORT
      LAYER M4 ;
      RECT 0.000 37.536 0.024 37.560 ;
    END
  END wd_in[110]
  PIN wd_in[111]
    DIRECTION INPUT ;
    USE SIGNAL ;
    SHAPE ABUTMENT ;
    PORT
      LAYER M4 ;
      RECT 0.000 37.632 0.024 37.656 ;
    END
  END wd_in[111]
  PIN wd_in[112]
    DIRECTION INPUT ;
    USE SIGNAL ;
    SHAPE ABUTMENT ;
    PORT
      LAYER M4 ;
      RECT 0.000 37.728 0.024 37.752 ;
    END
  END wd_in[112]
  PIN wd_in[113]
    DIRECTION INPUT ;
    USE SIGNAL ;
    SHAPE ABUTMENT ;
    PORT
      LAYER M4 ;
      RECT 0.000 37.824 0.024 37.848 ;
    END
  END wd_in[113]
  PIN wd_in[114]
    DIRECTION INPUT ;
    USE SIGNAL ;
    SHAPE ABUTMENT ;
    PORT
      LAYER M4 ;
      RECT 0.000 37.920 0.024 37.944 ;
    END
  END wd_in[114]
  PIN wd_in[115]
    DIRECTION INPUT ;
    USE SIGNAL ;
    SHAPE ABUTMENT ;
    PORT
      LAYER M4 ;
      RECT 0.000 38.016 0.024 38.040 ;
    END
  END wd_in[115]
  PIN wd_in[116]
    DIRECTION INPUT ;
    USE SIGNAL ;
    SHAPE ABUTMENT ;
    PORT
      LAYER M4 ;
      RECT 0.000 38.112 0.024 38.136 ;
    END
  END wd_in[116]
  PIN wd_in[117]
    DIRECTION INPUT ;
    USE SIGNAL ;
    SHAPE ABUTMENT ;
    PORT
      LAYER M4 ;
      RECT 0.000 38.208 0.024 38.232 ;
    END
  END wd_in[117]
  PIN wd_in[118]
    DIRECTION INPUT ;
    USE SIGNAL ;
    SHAPE ABUTMENT ;
    PORT
      LAYER M4 ;
      RECT 0.000 38.304 0.024 38.328 ;
    END
  END wd_in[118]
  PIN wd_in[119]
    DIRECTION INPUT ;
    USE SIGNAL ;
    SHAPE ABUTMENT ;
    PORT
      LAYER M4 ;
      RECT 0.000 38.400 0.024 38.424 ;
    END
  END wd_in[119]
  PIN wd_in[120]
    DIRECTION INPUT ;
    USE SIGNAL ;
    SHAPE ABUTMENT ;
    PORT
      LAYER M4 ;
      RECT 0.000 38.496 0.024 38.520 ;
    END
  END wd_in[120]
  PIN wd_in[121]
    DIRECTION INPUT ;
    USE SIGNAL ;
    SHAPE ABUTMENT ;
    PORT
      LAYER M4 ;
      RECT 0.000 38.592 0.024 38.616 ;
    END
  END wd_in[121]
  PIN wd_in[122]
    DIRECTION INPUT ;
    USE SIGNAL ;
    SHAPE ABUTMENT ;
    PORT
      LAYER M4 ;
      RECT 0.000 38.688 0.024 38.712 ;
    END
  END wd_in[122]
  PIN wd_in[123]
    DIRECTION INPUT ;
    USE SIGNAL ;
    SHAPE ABUTMENT ;
    PORT
      LAYER M4 ;
      RECT 0.000 38.784 0.024 38.808 ;
    END
  END wd_in[123]
  PIN wd_in[124]
    DIRECTION INPUT ;
    USE SIGNAL ;
    SHAPE ABUTMENT ;
    PORT
      LAYER M4 ;
      RECT 0.000 38.880 0.024 38.904 ;
    END
  END wd_in[124]
  PIN wd_in[125]
    DIRECTION INPUT ;
    USE SIGNAL ;
    SHAPE ABUTMENT ;
    PORT
      LAYER M4 ;
      RECT 0.000 38.976 0.024 39.000 ;
    END
  END wd_in[125]
  PIN wd_in[126]
    DIRECTION INPUT ;
    USE SIGNAL ;
    SHAPE ABUTMENT ;
    PORT
      LAYER M4 ;
      RECT 0.000 39.072 0.024 39.096 ;
    END
  END wd_in[126]
  PIN wd_in[127]
    DIRECTION INPUT ;
    USE SIGNAL ;
    SHAPE ABUTMENT ;
    PORT
      LAYER M4 ;
      RECT 0.000 39.168 0.024 39.192 ;
    END
  END wd_in[127]
  PIN wd_in[128]
    DIRECTION INPUT ;
    USE SIGNAL ;
    SHAPE ABUTMENT ;
    PORT
      LAYER M4 ;
      RECT 0.000 39.264 0.024 39.288 ;
    END
  END wd_in[128]
  PIN wd_in[129]
    DIRECTION INPUT ;
    USE SIGNAL ;
    SHAPE ABUTMENT ;
    PORT
      LAYER M4 ;
      RECT 0.000 39.360 0.024 39.384 ;
    END
  END wd_in[129]
  PIN wd_in[130]
    DIRECTION INPUT ;
    USE SIGNAL ;
    SHAPE ABUTMENT ;
    PORT
      LAYER M4 ;
      RECT 0.000 39.456 0.024 39.480 ;
    END
  END wd_in[130]
  PIN wd_in[131]
    DIRECTION INPUT ;
    USE SIGNAL ;
    SHAPE ABUTMENT ;
    PORT
      LAYER M4 ;
      RECT 0.000 39.552 0.024 39.576 ;
    END
  END wd_in[131]
  PIN wd_in[132]
    DIRECTION INPUT ;
    USE SIGNAL ;
    SHAPE ABUTMENT ;
    PORT
      LAYER M4 ;
      RECT 0.000 39.648 0.024 39.672 ;
    END
  END wd_in[132]
  PIN wd_in[133]
    DIRECTION INPUT ;
    USE SIGNAL ;
    SHAPE ABUTMENT ;
    PORT
      LAYER M4 ;
      RECT 0.000 39.744 0.024 39.768 ;
    END
  END wd_in[133]
  PIN wd_in[134]
    DIRECTION INPUT ;
    USE SIGNAL ;
    SHAPE ABUTMENT ;
    PORT
      LAYER M4 ;
      RECT 0.000 39.840 0.024 39.864 ;
    END
  END wd_in[134]
  PIN wd_in[135]
    DIRECTION INPUT ;
    USE SIGNAL ;
    SHAPE ABUTMENT ;
    PORT
      LAYER M4 ;
      RECT 0.000 39.936 0.024 39.960 ;
    END
  END wd_in[135]
  PIN wd_in[136]
    DIRECTION INPUT ;
    USE SIGNAL ;
    SHAPE ABUTMENT ;
    PORT
      LAYER M4 ;
      RECT 0.000 40.032 0.024 40.056 ;
    END
  END wd_in[136]
  PIN wd_in[137]
    DIRECTION INPUT ;
    USE SIGNAL ;
    SHAPE ABUTMENT ;
    PORT
      LAYER M4 ;
      RECT 94.800 0.768 94.824 0.792 ;
    END
  END wd_in[137]
  PIN wd_in[138]
    DIRECTION INPUT ;
    USE SIGNAL ;
    SHAPE ABUTMENT ;
    PORT
      LAYER M4 ;
      RECT 94.800 0.864 94.824 0.888 ;
    END
  END wd_in[138]
  PIN wd_in[139]
    DIRECTION INPUT ;
    USE SIGNAL ;
    SHAPE ABUTMENT ;
    PORT
      LAYER M4 ;
      RECT 94.800 0.960 94.824 0.984 ;
    END
  END wd_in[139]
  PIN wd_in[140]
    DIRECTION INPUT ;
    USE SIGNAL ;
    SHAPE ABUTMENT ;
    PORT
      LAYER M4 ;
      RECT 94.800 1.056 94.824 1.080 ;
    END
  END wd_in[140]
  PIN wd_in[141]
    DIRECTION INPUT ;
    USE SIGNAL ;
    SHAPE ABUTMENT ;
    PORT
      LAYER M4 ;
      RECT 94.800 1.152 94.824 1.176 ;
    END
  END wd_in[141]
  PIN wd_in[142]
    DIRECTION INPUT ;
    USE SIGNAL ;
    SHAPE ABUTMENT ;
    PORT
      LAYER M4 ;
      RECT 94.800 1.248 94.824 1.272 ;
    END
  END wd_in[142]
  PIN wd_in[143]
    DIRECTION INPUT ;
    USE SIGNAL ;
    SHAPE ABUTMENT ;
    PORT
      LAYER M4 ;
      RECT 94.800 1.344 94.824 1.368 ;
    END
  END wd_in[143]
  PIN wd_in[144]
    DIRECTION INPUT ;
    USE SIGNAL ;
    SHAPE ABUTMENT ;
    PORT
      LAYER M4 ;
      RECT 94.800 1.440 94.824 1.464 ;
    END
  END wd_in[144]
  PIN wd_in[145]
    DIRECTION INPUT ;
    USE SIGNAL ;
    SHAPE ABUTMENT ;
    PORT
      LAYER M4 ;
      RECT 94.800 1.536 94.824 1.560 ;
    END
  END wd_in[145]
  PIN wd_in[146]
    DIRECTION INPUT ;
    USE SIGNAL ;
    SHAPE ABUTMENT ;
    PORT
      LAYER M4 ;
      RECT 94.800 1.632 94.824 1.656 ;
    END
  END wd_in[146]
  PIN wd_in[147]
    DIRECTION INPUT ;
    USE SIGNAL ;
    SHAPE ABUTMENT ;
    PORT
      LAYER M4 ;
      RECT 94.800 1.728 94.824 1.752 ;
    END
  END wd_in[147]
  PIN wd_in[148]
    DIRECTION INPUT ;
    USE SIGNAL ;
    SHAPE ABUTMENT ;
    PORT
      LAYER M4 ;
      RECT 94.800 1.824 94.824 1.848 ;
    END
  END wd_in[148]
  PIN wd_in[149]
    DIRECTION INPUT ;
    USE SIGNAL ;
    SHAPE ABUTMENT ;
    PORT
      LAYER M4 ;
      RECT 94.800 1.920 94.824 1.944 ;
    END
  END wd_in[149]
  PIN wd_in[150]
    DIRECTION INPUT ;
    USE SIGNAL ;
    SHAPE ABUTMENT ;
    PORT
      LAYER M4 ;
      RECT 94.800 2.016 94.824 2.040 ;
    END
  END wd_in[150]
  PIN wd_in[151]
    DIRECTION INPUT ;
    USE SIGNAL ;
    SHAPE ABUTMENT ;
    PORT
      LAYER M4 ;
      RECT 94.800 2.112 94.824 2.136 ;
    END
  END wd_in[151]
  PIN wd_in[152]
    DIRECTION INPUT ;
    USE SIGNAL ;
    SHAPE ABUTMENT ;
    PORT
      LAYER M4 ;
      RECT 94.800 2.208 94.824 2.232 ;
    END
  END wd_in[152]
  PIN wd_in[153]
    DIRECTION INPUT ;
    USE SIGNAL ;
    SHAPE ABUTMENT ;
    PORT
      LAYER M4 ;
      RECT 94.800 2.304 94.824 2.328 ;
    END
  END wd_in[153]
  PIN wd_in[154]
    DIRECTION INPUT ;
    USE SIGNAL ;
    SHAPE ABUTMENT ;
    PORT
      LAYER M4 ;
      RECT 94.800 2.400 94.824 2.424 ;
    END
  END wd_in[154]
  PIN wd_in[155]
    DIRECTION INPUT ;
    USE SIGNAL ;
    SHAPE ABUTMENT ;
    PORT
      LAYER M4 ;
      RECT 94.800 2.496 94.824 2.520 ;
    END
  END wd_in[155]
  PIN wd_in[156]
    DIRECTION INPUT ;
    USE SIGNAL ;
    SHAPE ABUTMENT ;
    PORT
      LAYER M4 ;
      RECT 94.800 2.592 94.824 2.616 ;
    END
  END wd_in[156]
  PIN wd_in[157]
    DIRECTION INPUT ;
    USE SIGNAL ;
    SHAPE ABUTMENT ;
    PORT
      LAYER M4 ;
      RECT 94.800 2.688 94.824 2.712 ;
    END
  END wd_in[157]
  PIN wd_in[158]
    DIRECTION INPUT ;
    USE SIGNAL ;
    SHAPE ABUTMENT ;
    PORT
      LAYER M4 ;
      RECT 94.800 2.784 94.824 2.808 ;
    END
  END wd_in[158]
  PIN wd_in[159]
    DIRECTION INPUT ;
    USE SIGNAL ;
    SHAPE ABUTMENT ;
    PORT
      LAYER M4 ;
      RECT 94.800 2.880 94.824 2.904 ;
    END
  END wd_in[159]
  PIN wd_in[160]
    DIRECTION INPUT ;
    USE SIGNAL ;
    SHAPE ABUTMENT ;
    PORT
      LAYER M4 ;
      RECT 94.800 2.976 94.824 3.000 ;
    END
  END wd_in[160]
  PIN wd_in[161]
    DIRECTION INPUT ;
    USE SIGNAL ;
    SHAPE ABUTMENT ;
    PORT
      LAYER M4 ;
      RECT 94.800 3.072 94.824 3.096 ;
    END
  END wd_in[161]
  PIN wd_in[162]
    DIRECTION INPUT ;
    USE SIGNAL ;
    SHAPE ABUTMENT ;
    PORT
      LAYER M4 ;
      RECT 94.800 3.168 94.824 3.192 ;
    END
  END wd_in[162]
  PIN wd_in[163]
    DIRECTION INPUT ;
    USE SIGNAL ;
    SHAPE ABUTMENT ;
    PORT
      LAYER M4 ;
      RECT 94.800 3.264 94.824 3.288 ;
    END
  END wd_in[163]
  PIN wd_in[164]
    DIRECTION INPUT ;
    USE SIGNAL ;
    SHAPE ABUTMENT ;
    PORT
      LAYER M4 ;
      RECT 94.800 3.360 94.824 3.384 ;
    END
  END wd_in[164]
  PIN wd_in[165]
    DIRECTION INPUT ;
    USE SIGNAL ;
    SHAPE ABUTMENT ;
    PORT
      LAYER M4 ;
      RECT 94.800 3.456 94.824 3.480 ;
    END
  END wd_in[165]
  PIN wd_in[166]
    DIRECTION INPUT ;
    USE SIGNAL ;
    SHAPE ABUTMENT ;
    PORT
      LAYER M4 ;
      RECT 94.800 3.552 94.824 3.576 ;
    END
  END wd_in[166]
  PIN wd_in[167]
    DIRECTION INPUT ;
    USE SIGNAL ;
    SHAPE ABUTMENT ;
    PORT
      LAYER M4 ;
      RECT 94.800 3.648 94.824 3.672 ;
    END
  END wd_in[167]
  PIN wd_in[168]
    DIRECTION INPUT ;
    USE SIGNAL ;
    SHAPE ABUTMENT ;
    PORT
      LAYER M4 ;
      RECT 94.800 3.744 94.824 3.768 ;
    END
  END wd_in[168]
  PIN wd_in[169]
    DIRECTION INPUT ;
    USE SIGNAL ;
    SHAPE ABUTMENT ;
    PORT
      LAYER M4 ;
      RECT 94.800 3.840 94.824 3.864 ;
    END
  END wd_in[169]
  PIN wd_in[170]
    DIRECTION INPUT ;
    USE SIGNAL ;
    SHAPE ABUTMENT ;
    PORT
      LAYER M4 ;
      RECT 94.800 3.936 94.824 3.960 ;
    END
  END wd_in[170]
  PIN wd_in[171]
    DIRECTION INPUT ;
    USE SIGNAL ;
    SHAPE ABUTMENT ;
    PORT
      LAYER M4 ;
      RECT 94.800 4.032 94.824 4.056 ;
    END
  END wd_in[171]
  PIN wd_in[172]
    DIRECTION INPUT ;
    USE SIGNAL ;
    SHAPE ABUTMENT ;
    PORT
      LAYER M4 ;
      RECT 94.800 4.128 94.824 4.152 ;
    END
  END wd_in[172]
  PIN wd_in[173]
    DIRECTION INPUT ;
    USE SIGNAL ;
    SHAPE ABUTMENT ;
    PORT
      LAYER M4 ;
      RECT 94.800 4.224 94.824 4.248 ;
    END
  END wd_in[173]
  PIN wd_in[174]
    DIRECTION INPUT ;
    USE SIGNAL ;
    SHAPE ABUTMENT ;
    PORT
      LAYER M4 ;
      RECT 94.800 4.320 94.824 4.344 ;
    END
  END wd_in[174]
  PIN wd_in[175]
    DIRECTION INPUT ;
    USE SIGNAL ;
    SHAPE ABUTMENT ;
    PORT
      LAYER M4 ;
      RECT 94.800 4.416 94.824 4.440 ;
    END
  END wd_in[175]
  PIN wd_in[176]
    DIRECTION INPUT ;
    USE SIGNAL ;
    SHAPE ABUTMENT ;
    PORT
      LAYER M4 ;
      RECT 94.800 4.512 94.824 4.536 ;
    END
  END wd_in[176]
  PIN wd_in[177]
    DIRECTION INPUT ;
    USE SIGNAL ;
    SHAPE ABUTMENT ;
    PORT
      LAYER M4 ;
      RECT 94.800 4.608 94.824 4.632 ;
    END
  END wd_in[177]
  PIN wd_in[178]
    DIRECTION INPUT ;
    USE SIGNAL ;
    SHAPE ABUTMENT ;
    PORT
      LAYER M4 ;
      RECT 94.800 4.704 94.824 4.728 ;
    END
  END wd_in[178]
  PIN wd_in[179]
    DIRECTION INPUT ;
    USE SIGNAL ;
    SHAPE ABUTMENT ;
    PORT
      LAYER M4 ;
      RECT 94.800 4.800 94.824 4.824 ;
    END
  END wd_in[179]
  PIN wd_in[180]
    DIRECTION INPUT ;
    USE SIGNAL ;
    SHAPE ABUTMENT ;
    PORT
      LAYER M4 ;
      RECT 94.800 4.896 94.824 4.920 ;
    END
  END wd_in[180]
  PIN wd_in[181]
    DIRECTION INPUT ;
    USE SIGNAL ;
    SHAPE ABUTMENT ;
    PORT
      LAYER M4 ;
      RECT 94.800 4.992 94.824 5.016 ;
    END
  END wd_in[181]
  PIN wd_in[182]
    DIRECTION INPUT ;
    USE SIGNAL ;
    SHAPE ABUTMENT ;
    PORT
      LAYER M4 ;
      RECT 94.800 5.088 94.824 5.112 ;
    END
  END wd_in[182]
  PIN wd_in[183]
    DIRECTION INPUT ;
    USE SIGNAL ;
    SHAPE ABUTMENT ;
    PORT
      LAYER M4 ;
      RECT 94.800 5.184 94.824 5.208 ;
    END
  END wd_in[183]
  PIN wd_in[184]
    DIRECTION INPUT ;
    USE SIGNAL ;
    SHAPE ABUTMENT ;
    PORT
      LAYER M4 ;
      RECT 94.800 5.280 94.824 5.304 ;
    END
  END wd_in[184]
  PIN wd_in[185]
    DIRECTION INPUT ;
    USE SIGNAL ;
    SHAPE ABUTMENT ;
    PORT
      LAYER M4 ;
      RECT 94.800 5.376 94.824 5.400 ;
    END
  END wd_in[185]
  PIN wd_in[186]
    DIRECTION INPUT ;
    USE SIGNAL ;
    SHAPE ABUTMENT ;
    PORT
      LAYER M4 ;
      RECT 94.800 5.472 94.824 5.496 ;
    END
  END wd_in[186]
  PIN wd_in[187]
    DIRECTION INPUT ;
    USE SIGNAL ;
    SHAPE ABUTMENT ;
    PORT
      LAYER M4 ;
      RECT 94.800 5.568 94.824 5.592 ;
    END
  END wd_in[187]
  PIN wd_in[188]
    DIRECTION INPUT ;
    USE SIGNAL ;
    SHAPE ABUTMENT ;
    PORT
      LAYER M4 ;
      RECT 94.800 5.664 94.824 5.688 ;
    END
  END wd_in[188]
  PIN wd_in[189]
    DIRECTION INPUT ;
    USE SIGNAL ;
    SHAPE ABUTMENT ;
    PORT
      LAYER M4 ;
      RECT 94.800 5.760 94.824 5.784 ;
    END
  END wd_in[189]
  PIN wd_in[190]
    DIRECTION INPUT ;
    USE SIGNAL ;
    SHAPE ABUTMENT ;
    PORT
      LAYER M4 ;
      RECT 94.800 5.856 94.824 5.880 ;
    END
  END wd_in[190]
  PIN wd_in[191]
    DIRECTION INPUT ;
    USE SIGNAL ;
    SHAPE ABUTMENT ;
    PORT
      LAYER M4 ;
      RECT 94.800 5.952 94.824 5.976 ;
    END
  END wd_in[191]
  PIN wd_in[192]
    DIRECTION INPUT ;
    USE SIGNAL ;
    SHAPE ABUTMENT ;
    PORT
      LAYER M4 ;
      RECT 94.800 6.048 94.824 6.072 ;
    END
  END wd_in[192]
  PIN wd_in[193]
    DIRECTION INPUT ;
    USE SIGNAL ;
    SHAPE ABUTMENT ;
    PORT
      LAYER M4 ;
      RECT 94.800 6.144 94.824 6.168 ;
    END
  END wd_in[193]
  PIN wd_in[194]
    DIRECTION INPUT ;
    USE SIGNAL ;
    SHAPE ABUTMENT ;
    PORT
      LAYER M4 ;
      RECT 94.800 6.240 94.824 6.264 ;
    END
  END wd_in[194]
  PIN wd_in[195]
    DIRECTION INPUT ;
    USE SIGNAL ;
    SHAPE ABUTMENT ;
    PORT
      LAYER M4 ;
      RECT 94.800 6.336 94.824 6.360 ;
    END
  END wd_in[195]
  PIN wd_in[196]
    DIRECTION INPUT ;
    USE SIGNAL ;
    SHAPE ABUTMENT ;
    PORT
      LAYER M4 ;
      RECT 94.800 6.432 94.824 6.456 ;
    END
  END wd_in[196]
  PIN wd_in[197]
    DIRECTION INPUT ;
    USE SIGNAL ;
    SHAPE ABUTMENT ;
    PORT
      LAYER M4 ;
      RECT 94.800 6.528 94.824 6.552 ;
    END
  END wd_in[197]
  PIN wd_in[198]
    DIRECTION INPUT ;
    USE SIGNAL ;
    SHAPE ABUTMENT ;
    PORT
      LAYER M4 ;
      RECT 94.800 6.624 94.824 6.648 ;
    END
  END wd_in[198]
  PIN wd_in[199]
    DIRECTION INPUT ;
    USE SIGNAL ;
    SHAPE ABUTMENT ;
    PORT
      LAYER M4 ;
      RECT 94.800 6.720 94.824 6.744 ;
    END
  END wd_in[199]
  PIN wd_in[200]
    DIRECTION INPUT ;
    USE SIGNAL ;
    SHAPE ABUTMENT ;
    PORT
      LAYER M4 ;
      RECT 94.800 6.816 94.824 6.840 ;
    END
  END wd_in[200]
  PIN wd_in[201]
    DIRECTION INPUT ;
    USE SIGNAL ;
    SHAPE ABUTMENT ;
    PORT
      LAYER M4 ;
      RECT 94.800 6.912 94.824 6.936 ;
    END
  END wd_in[201]
  PIN wd_in[202]
    DIRECTION INPUT ;
    USE SIGNAL ;
    SHAPE ABUTMENT ;
    PORT
      LAYER M4 ;
      RECT 94.800 7.008 94.824 7.032 ;
    END
  END wd_in[202]
  PIN wd_in[203]
    DIRECTION INPUT ;
    USE SIGNAL ;
    SHAPE ABUTMENT ;
    PORT
      LAYER M4 ;
      RECT 94.800 7.104 94.824 7.128 ;
    END
  END wd_in[203]
  PIN wd_in[204]
    DIRECTION INPUT ;
    USE SIGNAL ;
    SHAPE ABUTMENT ;
    PORT
      LAYER M4 ;
      RECT 94.800 7.200 94.824 7.224 ;
    END
  END wd_in[204]
  PIN wd_in[205]
    DIRECTION INPUT ;
    USE SIGNAL ;
    SHAPE ABUTMENT ;
    PORT
      LAYER M4 ;
      RECT 94.800 7.296 94.824 7.320 ;
    END
  END wd_in[205]
  PIN wd_in[206]
    DIRECTION INPUT ;
    USE SIGNAL ;
    SHAPE ABUTMENT ;
    PORT
      LAYER M4 ;
      RECT 94.800 7.392 94.824 7.416 ;
    END
  END wd_in[206]
  PIN wd_in[207]
    DIRECTION INPUT ;
    USE SIGNAL ;
    SHAPE ABUTMENT ;
    PORT
      LAYER M4 ;
      RECT 94.800 7.488 94.824 7.512 ;
    END
  END wd_in[207]
  PIN wd_in[208]
    DIRECTION INPUT ;
    USE SIGNAL ;
    SHAPE ABUTMENT ;
    PORT
      LAYER M4 ;
      RECT 94.800 7.584 94.824 7.608 ;
    END
  END wd_in[208]
  PIN wd_in[209]
    DIRECTION INPUT ;
    USE SIGNAL ;
    SHAPE ABUTMENT ;
    PORT
      LAYER M4 ;
      RECT 94.800 7.680 94.824 7.704 ;
    END
  END wd_in[209]
  PIN wd_in[210]
    DIRECTION INPUT ;
    USE SIGNAL ;
    SHAPE ABUTMENT ;
    PORT
      LAYER M4 ;
      RECT 94.800 7.776 94.824 7.800 ;
    END
  END wd_in[210]
  PIN wd_in[211]
    DIRECTION INPUT ;
    USE SIGNAL ;
    SHAPE ABUTMENT ;
    PORT
      LAYER M4 ;
      RECT 94.800 7.872 94.824 7.896 ;
    END
  END wd_in[211]
  PIN wd_in[212]
    DIRECTION INPUT ;
    USE SIGNAL ;
    SHAPE ABUTMENT ;
    PORT
      LAYER M4 ;
      RECT 94.800 7.968 94.824 7.992 ;
    END
  END wd_in[212]
  PIN wd_in[213]
    DIRECTION INPUT ;
    USE SIGNAL ;
    SHAPE ABUTMENT ;
    PORT
      LAYER M4 ;
      RECT 94.800 8.064 94.824 8.088 ;
    END
  END wd_in[213]
  PIN wd_in[214]
    DIRECTION INPUT ;
    USE SIGNAL ;
    SHAPE ABUTMENT ;
    PORT
      LAYER M4 ;
      RECT 94.800 8.160 94.824 8.184 ;
    END
  END wd_in[214]
  PIN wd_in[215]
    DIRECTION INPUT ;
    USE SIGNAL ;
    SHAPE ABUTMENT ;
    PORT
      LAYER M4 ;
      RECT 94.800 8.256 94.824 8.280 ;
    END
  END wd_in[215]
  PIN wd_in[216]
    DIRECTION INPUT ;
    USE SIGNAL ;
    SHAPE ABUTMENT ;
    PORT
      LAYER M4 ;
      RECT 94.800 8.352 94.824 8.376 ;
    END
  END wd_in[216]
  PIN wd_in[217]
    DIRECTION INPUT ;
    USE SIGNAL ;
    SHAPE ABUTMENT ;
    PORT
      LAYER M4 ;
      RECT 94.800 8.448 94.824 8.472 ;
    END
  END wd_in[217]
  PIN wd_in[218]
    DIRECTION INPUT ;
    USE SIGNAL ;
    SHAPE ABUTMENT ;
    PORT
      LAYER M4 ;
      RECT 94.800 8.544 94.824 8.568 ;
    END
  END wd_in[218]
  PIN wd_in[219]
    DIRECTION INPUT ;
    USE SIGNAL ;
    SHAPE ABUTMENT ;
    PORT
      LAYER M4 ;
      RECT 94.800 8.640 94.824 8.664 ;
    END
  END wd_in[219]
  PIN wd_in[220]
    DIRECTION INPUT ;
    USE SIGNAL ;
    SHAPE ABUTMENT ;
    PORT
      LAYER M4 ;
      RECT 94.800 8.736 94.824 8.760 ;
    END
  END wd_in[220]
  PIN wd_in[221]
    DIRECTION INPUT ;
    USE SIGNAL ;
    SHAPE ABUTMENT ;
    PORT
      LAYER M4 ;
      RECT 94.800 8.832 94.824 8.856 ;
    END
  END wd_in[221]
  PIN wd_in[222]
    DIRECTION INPUT ;
    USE SIGNAL ;
    SHAPE ABUTMENT ;
    PORT
      LAYER M4 ;
      RECT 94.800 8.928 94.824 8.952 ;
    END
  END wd_in[222]
  PIN wd_in[223]
    DIRECTION INPUT ;
    USE SIGNAL ;
    SHAPE ABUTMENT ;
    PORT
      LAYER M4 ;
      RECT 94.800 9.024 94.824 9.048 ;
    END
  END wd_in[223]
  PIN wd_in[224]
    DIRECTION INPUT ;
    USE SIGNAL ;
    SHAPE ABUTMENT ;
    PORT
      LAYER M4 ;
      RECT 94.800 9.120 94.824 9.144 ;
    END
  END wd_in[224]
  PIN wd_in[225]
    DIRECTION INPUT ;
    USE SIGNAL ;
    SHAPE ABUTMENT ;
    PORT
      LAYER M4 ;
      RECT 94.800 9.216 94.824 9.240 ;
    END
  END wd_in[225]
  PIN wd_in[226]
    DIRECTION INPUT ;
    USE SIGNAL ;
    SHAPE ABUTMENT ;
    PORT
      LAYER M4 ;
      RECT 94.800 9.312 94.824 9.336 ;
    END
  END wd_in[226]
  PIN wd_in[227]
    DIRECTION INPUT ;
    USE SIGNAL ;
    SHAPE ABUTMENT ;
    PORT
      LAYER M4 ;
      RECT 94.800 9.408 94.824 9.432 ;
    END
  END wd_in[227]
  PIN wd_in[228]
    DIRECTION INPUT ;
    USE SIGNAL ;
    SHAPE ABUTMENT ;
    PORT
      LAYER M4 ;
      RECT 94.800 9.504 94.824 9.528 ;
    END
  END wd_in[228]
  PIN wd_in[229]
    DIRECTION INPUT ;
    USE SIGNAL ;
    SHAPE ABUTMENT ;
    PORT
      LAYER M4 ;
      RECT 94.800 9.600 94.824 9.624 ;
    END
  END wd_in[229]
  PIN wd_in[230]
    DIRECTION INPUT ;
    USE SIGNAL ;
    SHAPE ABUTMENT ;
    PORT
      LAYER M4 ;
      RECT 94.800 9.696 94.824 9.720 ;
    END
  END wd_in[230]
  PIN wd_in[231]
    DIRECTION INPUT ;
    USE SIGNAL ;
    SHAPE ABUTMENT ;
    PORT
      LAYER M4 ;
      RECT 94.800 9.792 94.824 9.816 ;
    END
  END wd_in[231]
  PIN wd_in[232]
    DIRECTION INPUT ;
    USE SIGNAL ;
    SHAPE ABUTMENT ;
    PORT
      LAYER M4 ;
      RECT 94.800 9.888 94.824 9.912 ;
    END
  END wd_in[232]
  PIN wd_in[233]
    DIRECTION INPUT ;
    USE SIGNAL ;
    SHAPE ABUTMENT ;
    PORT
      LAYER M4 ;
      RECT 94.800 9.984 94.824 10.008 ;
    END
  END wd_in[233]
  PIN wd_in[234]
    DIRECTION INPUT ;
    USE SIGNAL ;
    SHAPE ABUTMENT ;
    PORT
      LAYER M4 ;
      RECT 94.800 10.080 94.824 10.104 ;
    END
  END wd_in[234]
  PIN wd_in[235]
    DIRECTION INPUT ;
    USE SIGNAL ;
    SHAPE ABUTMENT ;
    PORT
      LAYER M4 ;
      RECT 94.800 10.176 94.824 10.200 ;
    END
  END wd_in[235]
  PIN wd_in[236]
    DIRECTION INPUT ;
    USE SIGNAL ;
    SHAPE ABUTMENT ;
    PORT
      LAYER M4 ;
      RECT 94.800 10.272 94.824 10.296 ;
    END
  END wd_in[236]
  PIN wd_in[237]
    DIRECTION INPUT ;
    USE SIGNAL ;
    SHAPE ABUTMENT ;
    PORT
      LAYER M4 ;
      RECT 94.800 10.368 94.824 10.392 ;
    END
  END wd_in[237]
  PIN wd_in[238]
    DIRECTION INPUT ;
    USE SIGNAL ;
    SHAPE ABUTMENT ;
    PORT
      LAYER M4 ;
      RECT 94.800 10.464 94.824 10.488 ;
    END
  END wd_in[238]
  PIN wd_in[239]
    DIRECTION INPUT ;
    USE SIGNAL ;
    SHAPE ABUTMENT ;
    PORT
      LAYER M4 ;
      RECT 94.800 10.560 94.824 10.584 ;
    END
  END wd_in[239]
  PIN wd_in[240]
    DIRECTION INPUT ;
    USE SIGNAL ;
    SHAPE ABUTMENT ;
    PORT
      LAYER M4 ;
      RECT 94.800 10.656 94.824 10.680 ;
    END
  END wd_in[240]
  PIN wd_in[241]
    DIRECTION INPUT ;
    USE SIGNAL ;
    SHAPE ABUTMENT ;
    PORT
      LAYER M4 ;
      RECT 94.800 10.752 94.824 10.776 ;
    END
  END wd_in[241]
  PIN wd_in[242]
    DIRECTION INPUT ;
    USE SIGNAL ;
    SHAPE ABUTMENT ;
    PORT
      LAYER M4 ;
      RECT 94.800 10.848 94.824 10.872 ;
    END
  END wd_in[242]
  PIN wd_in[243]
    DIRECTION INPUT ;
    USE SIGNAL ;
    SHAPE ABUTMENT ;
    PORT
      LAYER M4 ;
      RECT 94.800 10.944 94.824 10.968 ;
    END
  END wd_in[243]
  PIN wd_in[244]
    DIRECTION INPUT ;
    USE SIGNAL ;
    SHAPE ABUTMENT ;
    PORT
      LAYER M4 ;
      RECT 94.800 11.040 94.824 11.064 ;
    END
  END wd_in[244]
  PIN wd_in[245]
    DIRECTION INPUT ;
    USE SIGNAL ;
    SHAPE ABUTMENT ;
    PORT
      LAYER M4 ;
      RECT 94.800 11.136 94.824 11.160 ;
    END
  END wd_in[245]
  PIN wd_in[246]
    DIRECTION INPUT ;
    USE SIGNAL ;
    SHAPE ABUTMENT ;
    PORT
      LAYER M4 ;
      RECT 94.800 11.232 94.824 11.256 ;
    END
  END wd_in[246]
  PIN wd_in[247]
    DIRECTION INPUT ;
    USE SIGNAL ;
    SHAPE ABUTMENT ;
    PORT
      LAYER M4 ;
      RECT 94.800 11.328 94.824 11.352 ;
    END
  END wd_in[247]
  PIN wd_in[248]
    DIRECTION INPUT ;
    USE SIGNAL ;
    SHAPE ABUTMENT ;
    PORT
      LAYER M4 ;
      RECT 94.800 11.424 94.824 11.448 ;
    END
  END wd_in[248]
  PIN wd_in[249]
    DIRECTION INPUT ;
    USE SIGNAL ;
    SHAPE ABUTMENT ;
    PORT
      LAYER M4 ;
      RECT 94.800 11.520 94.824 11.544 ;
    END
  END wd_in[249]
  PIN wd_in[250]
    DIRECTION INPUT ;
    USE SIGNAL ;
    SHAPE ABUTMENT ;
    PORT
      LAYER M4 ;
      RECT 94.800 11.616 94.824 11.640 ;
    END
  END wd_in[250]
  PIN wd_in[251]
    DIRECTION INPUT ;
    USE SIGNAL ;
    SHAPE ABUTMENT ;
    PORT
      LAYER M4 ;
      RECT 94.800 11.712 94.824 11.736 ;
    END
  END wd_in[251]
  PIN wd_in[252]
    DIRECTION INPUT ;
    USE SIGNAL ;
    SHAPE ABUTMENT ;
    PORT
      LAYER M4 ;
      RECT 94.800 11.808 94.824 11.832 ;
    END
  END wd_in[252]
  PIN wd_in[253]
    DIRECTION INPUT ;
    USE SIGNAL ;
    SHAPE ABUTMENT ;
    PORT
      LAYER M4 ;
      RECT 94.800 11.904 94.824 11.928 ;
    END
  END wd_in[253]
  PIN wd_in[254]
    DIRECTION INPUT ;
    USE SIGNAL ;
    SHAPE ABUTMENT ;
    PORT
      LAYER M4 ;
      RECT 94.800 12.000 94.824 12.024 ;
    END
  END wd_in[254]
  PIN wd_in[255]
    DIRECTION INPUT ;
    USE SIGNAL ;
    SHAPE ABUTMENT ;
    PORT
      LAYER M4 ;
      RECT 94.800 12.096 94.824 12.120 ;
    END
  END wd_in[255]
  PIN w_mask_in[0]
    DIRECTION INPUT ;
    USE SIGNAL ;
    SHAPE ABUTMENT ;
    PORT
      LAYER M4 ;
      RECT 94.800 12.192 94.824 12.216 ;
    END
  END w_mask_in[0]
  PIN w_mask_in[1]
    DIRECTION INPUT ;
    USE SIGNAL ;
    SHAPE ABUTMENT ;
    PORT
      LAYER M4 ;
      RECT 94.800 12.288 94.824 12.312 ;
    END
  END w_mask_in[1]
  PIN w_mask_in[2]
    DIRECTION INPUT ;
    USE SIGNAL ;
    SHAPE ABUTMENT ;
    PORT
      LAYER M4 ;
      RECT 94.800 12.384 94.824 12.408 ;
    END
  END w_mask_in[2]
  PIN w_mask_in[3]
    DIRECTION INPUT ;
    USE SIGNAL ;
    SHAPE ABUTMENT ;
    PORT
      LAYER M4 ;
      RECT 94.800 12.480 94.824 12.504 ;
    END
  END w_mask_in[3]
  PIN w_mask_in[4]
    DIRECTION INPUT ;
    USE SIGNAL ;
    SHAPE ABUTMENT ;
    PORT
      LAYER M4 ;
      RECT 94.800 12.576 94.824 12.600 ;
    END
  END w_mask_in[4]
  PIN w_mask_in[5]
    DIRECTION INPUT ;
    USE SIGNAL ;
    SHAPE ABUTMENT ;
    PORT
      LAYER M4 ;
      RECT 94.800 12.672 94.824 12.696 ;
    END
  END w_mask_in[5]
  PIN w_mask_in[6]
    DIRECTION INPUT ;
    USE SIGNAL ;
    SHAPE ABUTMENT ;
    PORT
      LAYER M4 ;
      RECT 94.800 12.768 94.824 12.792 ;
    END
  END w_mask_in[6]
  PIN w_mask_in[7]
    DIRECTION INPUT ;
    USE SIGNAL ;
    SHAPE ABUTMENT ;
    PORT
      LAYER M4 ;
      RECT 94.800 12.864 94.824 12.888 ;
    END
  END w_mask_in[7]
  PIN w_mask_in[8]
    DIRECTION INPUT ;
    USE SIGNAL ;
    SHAPE ABUTMENT ;
    PORT
      LAYER M4 ;
      RECT 94.800 12.960 94.824 12.984 ;
    END
  END w_mask_in[8]
  PIN w_mask_in[9]
    DIRECTION INPUT ;
    USE SIGNAL ;
    SHAPE ABUTMENT ;
    PORT
      LAYER M4 ;
      RECT 94.800 13.056 94.824 13.080 ;
    END
  END w_mask_in[9]
  PIN w_mask_in[10]
    DIRECTION INPUT ;
    USE SIGNAL ;
    SHAPE ABUTMENT ;
    PORT
      LAYER M4 ;
      RECT 94.800 13.152 94.824 13.176 ;
    END
  END w_mask_in[10]
  PIN w_mask_in[11]
    DIRECTION INPUT ;
    USE SIGNAL ;
    SHAPE ABUTMENT ;
    PORT
      LAYER M4 ;
      RECT 94.800 13.248 94.824 13.272 ;
    END
  END w_mask_in[11]
  PIN w_mask_in[12]
    DIRECTION INPUT ;
    USE SIGNAL ;
    SHAPE ABUTMENT ;
    PORT
      LAYER M4 ;
      RECT 94.800 13.344 94.824 13.368 ;
    END
  END w_mask_in[12]
  PIN w_mask_in[13]
    DIRECTION INPUT ;
    USE SIGNAL ;
    SHAPE ABUTMENT ;
    PORT
      LAYER M4 ;
      RECT 94.800 13.440 94.824 13.464 ;
    END
  END w_mask_in[13]
  PIN w_mask_in[14]
    DIRECTION INPUT ;
    USE SIGNAL ;
    SHAPE ABUTMENT ;
    PORT
      LAYER M4 ;
      RECT 94.800 13.536 94.824 13.560 ;
    END
  END w_mask_in[14]
  PIN w_mask_in[15]
    DIRECTION INPUT ;
    USE SIGNAL ;
    SHAPE ABUTMENT ;
    PORT
      LAYER M4 ;
      RECT 94.800 13.632 94.824 13.656 ;
    END
  END w_mask_in[15]
  PIN w_mask_in[16]
    DIRECTION INPUT ;
    USE SIGNAL ;
    SHAPE ABUTMENT ;
    PORT
      LAYER M4 ;
      RECT 94.800 13.728 94.824 13.752 ;
    END
  END w_mask_in[16]
  PIN w_mask_in[17]
    DIRECTION INPUT ;
    USE SIGNAL ;
    SHAPE ABUTMENT ;
    PORT
      LAYER M4 ;
      RECT 94.800 13.824 94.824 13.848 ;
    END
  END w_mask_in[17]
  PIN w_mask_in[18]
    DIRECTION INPUT ;
    USE SIGNAL ;
    SHAPE ABUTMENT ;
    PORT
      LAYER M4 ;
      RECT 94.800 13.920 94.824 13.944 ;
    END
  END w_mask_in[18]
  PIN w_mask_in[19]
    DIRECTION INPUT ;
    USE SIGNAL ;
    SHAPE ABUTMENT ;
    PORT
      LAYER M4 ;
      RECT 94.800 14.016 94.824 14.040 ;
    END
  END w_mask_in[19]
  PIN w_mask_in[20]
    DIRECTION INPUT ;
    USE SIGNAL ;
    SHAPE ABUTMENT ;
    PORT
      LAYER M4 ;
      RECT 94.800 14.112 94.824 14.136 ;
    END
  END w_mask_in[20]
  PIN w_mask_in[21]
    DIRECTION INPUT ;
    USE SIGNAL ;
    SHAPE ABUTMENT ;
    PORT
      LAYER M4 ;
      RECT 94.800 14.208 94.824 14.232 ;
    END
  END w_mask_in[21]
  PIN w_mask_in[22]
    DIRECTION INPUT ;
    USE SIGNAL ;
    SHAPE ABUTMENT ;
    PORT
      LAYER M4 ;
      RECT 94.800 14.304 94.824 14.328 ;
    END
  END w_mask_in[22]
  PIN w_mask_in[23]
    DIRECTION INPUT ;
    USE SIGNAL ;
    SHAPE ABUTMENT ;
    PORT
      LAYER M4 ;
      RECT 94.800 14.400 94.824 14.424 ;
    END
  END w_mask_in[23]
  PIN w_mask_in[24]
    DIRECTION INPUT ;
    USE SIGNAL ;
    SHAPE ABUTMENT ;
    PORT
      LAYER M4 ;
      RECT 94.800 14.496 94.824 14.520 ;
    END
  END w_mask_in[24]
  PIN w_mask_in[25]
    DIRECTION INPUT ;
    USE SIGNAL ;
    SHAPE ABUTMENT ;
    PORT
      LAYER M4 ;
      RECT 94.800 14.592 94.824 14.616 ;
    END
  END w_mask_in[25]
  PIN w_mask_in[26]
    DIRECTION INPUT ;
    USE SIGNAL ;
    SHAPE ABUTMENT ;
    PORT
      LAYER M4 ;
      RECT 94.800 14.688 94.824 14.712 ;
    END
  END w_mask_in[26]
  PIN w_mask_in[27]
    DIRECTION INPUT ;
    USE SIGNAL ;
    SHAPE ABUTMENT ;
    PORT
      LAYER M4 ;
      RECT 94.800 14.784 94.824 14.808 ;
    END
  END w_mask_in[27]
  PIN w_mask_in[28]
    DIRECTION INPUT ;
    USE SIGNAL ;
    SHAPE ABUTMENT ;
    PORT
      LAYER M4 ;
      RECT 94.800 14.880 94.824 14.904 ;
    END
  END w_mask_in[28]
  PIN w_mask_in[29]
    DIRECTION INPUT ;
    USE SIGNAL ;
    SHAPE ABUTMENT ;
    PORT
      LAYER M4 ;
      RECT 94.800 14.976 94.824 15.000 ;
    END
  END w_mask_in[29]
  PIN w_mask_in[30]
    DIRECTION INPUT ;
    USE SIGNAL ;
    SHAPE ABUTMENT ;
    PORT
      LAYER M4 ;
      RECT 94.800 15.072 94.824 15.096 ;
    END
  END w_mask_in[30]
  PIN w_mask_in[31]
    DIRECTION INPUT ;
    USE SIGNAL ;
    SHAPE ABUTMENT ;
    PORT
      LAYER M4 ;
      RECT 94.800 15.168 94.824 15.192 ;
    END
  END w_mask_in[31]
  PIN w_mask_in[32]
    DIRECTION INPUT ;
    USE SIGNAL ;
    SHAPE ABUTMENT ;
    PORT
      LAYER M4 ;
      RECT 94.800 15.264 94.824 15.288 ;
    END
  END w_mask_in[32]
  PIN w_mask_in[33]
    DIRECTION INPUT ;
    USE SIGNAL ;
    SHAPE ABUTMENT ;
    PORT
      LAYER M4 ;
      RECT 94.800 15.360 94.824 15.384 ;
    END
  END w_mask_in[33]
  PIN w_mask_in[34]
    DIRECTION INPUT ;
    USE SIGNAL ;
    SHAPE ABUTMENT ;
    PORT
      LAYER M4 ;
      RECT 94.800 15.456 94.824 15.480 ;
    END
  END w_mask_in[34]
  PIN w_mask_in[35]
    DIRECTION INPUT ;
    USE SIGNAL ;
    SHAPE ABUTMENT ;
    PORT
      LAYER M4 ;
      RECT 94.800 15.552 94.824 15.576 ;
    END
  END w_mask_in[35]
  PIN w_mask_in[36]
    DIRECTION INPUT ;
    USE SIGNAL ;
    SHAPE ABUTMENT ;
    PORT
      LAYER M4 ;
      RECT 94.800 15.648 94.824 15.672 ;
    END
  END w_mask_in[36]
  PIN w_mask_in[37]
    DIRECTION INPUT ;
    USE SIGNAL ;
    SHAPE ABUTMENT ;
    PORT
      LAYER M4 ;
      RECT 94.800 15.744 94.824 15.768 ;
    END
  END w_mask_in[37]
  PIN w_mask_in[38]
    DIRECTION INPUT ;
    USE SIGNAL ;
    SHAPE ABUTMENT ;
    PORT
      LAYER M4 ;
      RECT 94.800 15.840 94.824 15.864 ;
    END
  END w_mask_in[38]
  PIN w_mask_in[39]
    DIRECTION INPUT ;
    USE SIGNAL ;
    SHAPE ABUTMENT ;
    PORT
      LAYER M4 ;
      RECT 94.800 15.936 94.824 15.960 ;
    END
  END w_mask_in[39]
  PIN w_mask_in[40]
    DIRECTION INPUT ;
    USE SIGNAL ;
    SHAPE ABUTMENT ;
    PORT
      LAYER M4 ;
      RECT 94.800 16.032 94.824 16.056 ;
    END
  END w_mask_in[40]
  PIN w_mask_in[41]
    DIRECTION INPUT ;
    USE SIGNAL ;
    SHAPE ABUTMENT ;
    PORT
      LAYER M4 ;
      RECT 94.800 16.128 94.824 16.152 ;
    END
  END w_mask_in[41]
  PIN w_mask_in[42]
    DIRECTION INPUT ;
    USE SIGNAL ;
    SHAPE ABUTMENT ;
    PORT
      LAYER M4 ;
      RECT 94.800 16.224 94.824 16.248 ;
    END
  END w_mask_in[42]
  PIN w_mask_in[43]
    DIRECTION INPUT ;
    USE SIGNAL ;
    SHAPE ABUTMENT ;
    PORT
      LAYER M4 ;
      RECT 94.800 16.320 94.824 16.344 ;
    END
  END w_mask_in[43]
  PIN w_mask_in[44]
    DIRECTION INPUT ;
    USE SIGNAL ;
    SHAPE ABUTMENT ;
    PORT
      LAYER M4 ;
      RECT 94.800 16.416 94.824 16.440 ;
    END
  END w_mask_in[44]
  PIN w_mask_in[45]
    DIRECTION INPUT ;
    USE SIGNAL ;
    SHAPE ABUTMENT ;
    PORT
      LAYER M4 ;
      RECT 94.800 16.512 94.824 16.536 ;
    END
  END w_mask_in[45]
  PIN w_mask_in[46]
    DIRECTION INPUT ;
    USE SIGNAL ;
    SHAPE ABUTMENT ;
    PORT
      LAYER M4 ;
      RECT 94.800 16.608 94.824 16.632 ;
    END
  END w_mask_in[46]
  PIN w_mask_in[47]
    DIRECTION INPUT ;
    USE SIGNAL ;
    SHAPE ABUTMENT ;
    PORT
      LAYER M4 ;
      RECT 94.800 16.704 94.824 16.728 ;
    END
  END w_mask_in[47]
  PIN w_mask_in[48]
    DIRECTION INPUT ;
    USE SIGNAL ;
    SHAPE ABUTMENT ;
    PORT
      LAYER M4 ;
      RECT 94.800 16.800 94.824 16.824 ;
    END
  END w_mask_in[48]
  PIN w_mask_in[49]
    DIRECTION INPUT ;
    USE SIGNAL ;
    SHAPE ABUTMENT ;
    PORT
      LAYER M4 ;
      RECT 94.800 16.896 94.824 16.920 ;
    END
  END w_mask_in[49]
  PIN w_mask_in[50]
    DIRECTION INPUT ;
    USE SIGNAL ;
    SHAPE ABUTMENT ;
    PORT
      LAYER M4 ;
      RECT 94.800 16.992 94.824 17.016 ;
    END
  END w_mask_in[50]
  PIN w_mask_in[51]
    DIRECTION INPUT ;
    USE SIGNAL ;
    SHAPE ABUTMENT ;
    PORT
      LAYER M4 ;
      RECT 94.800 17.088 94.824 17.112 ;
    END
  END w_mask_in[51]
  PIN w_mask_in[52]
    DIRECTION INPUT ;
    USE SIGNAL ;
    SHAPE ABUTMENT ;
    PORT
      LAYER M4 ;
      RECT 94.800 17.184 94.824 17.208 ;
    END
  END w_mask_in[52]
  PIN w_mask_in[53]
    DIRECTION INPUT ;
    USE SIGNAL ;
    SHAPE ABUTMENT ;
    PORT
      LAYER M4 ;
      RECT 94.800 17.280 94.824 17.304 ;
    END
  END w_mask_in[53]
  PIN w_mask_in[54]
    DIRECTION INPUT ;
    USE SIGNAL ;
    SHAPE ABUTMENT ;
    PORT
      LAYER M4 ;
      RECT 94.800 17.376 94.824 17.400 ;
    END
  END w_mask_in[54]
  PIN w_mask_in[55]
    DIRECTION INPUT ;
    USE SIGNAL ;
    SHAPE ABUTMENT ;
    PORT
      LAYER M4 ;
      RECT 94.800 17.472 94.824 17.496 ;
    END
  END w_mask_in[55]
  PIN w_mask_in[56]
    DIRECTION INPUT ;
    USE SIGNAL ;
    SHAPE ABUTMENT ;
    PORT
      LAYER M4 ;
      RECT 94.800 17.568 94.824 17.592 ;
    END
  END w_mask_in[56]
  PIN w_mask_in[57]
    DIRECTION INPUT ;
    USE SIGNAL ;
    SHAPE ABUTMENT ;
    PORT
      LAYER M4 ;
      RECT 94.800 17.664 94.824 17.688 ;
    END
  END w_mask_in[57]
  PIN w_mask_in[58]
    DIRECTION INPUT ;
    USE SIGNAL ;
    SHAPE ABUTMENT ;
    PORT
      LAYER M4 ;
      RECT 94.800 17.760 94.824 17.784 ;
    END
  END w_mask_in[58]
  PIN w_mask_in[59]
    DIRECTION INPUT ;
    USE SIGNAL ;
    SHAPE ABUTMENT ;
    PORT
      LAYER M4 ;
      RECT 94.800 17.856 94.824 17.880 ;
    END
  END w_mask_in[59]
  PIN w_mask_in[60]
    DIRECTION INPUT ;
    USE SIGNAL ;
    SHAPE ABUTMENT ;
    PORT
      LAYER M4 ;
      RECT 94.800 17.952 94.824 17.976 ;
    END
  END w_mask_in[60]
  PIN w_mask_in[61]
    DIRECTION INPUT ;
    USE SIGNAL ;
    SHAPE ABUTMENT ;
    PORT
      LAYER M4 ;
      RECT 94.800 18.048 94.824 18.072 ;
    END
  END w_mask_in[61]
  PIN w_mask_in[62]
    DIRECTION INPUT ;
    USE SIGNAL ;
    SHAPE ABUTMENT ;
    PORT
      LAYER M4 ;
      RECT 94.800 18.144 94.824 18.168 ;
    END
  END w_mask_in[62]
  PIN w_mask_in[63]
    DIRECTION INPUT ;
    USE SIGNAL ;
    SHAPE ABUTMENT ;
    PORT
      LAYER M4 ;
      RECT 94.800 18.240 94.824 18.264 ;
    END
  END w_mask_in[63]
  PIN w_mask_in[64]
    DIRECTION INPUT ;
    USE SIGNAL ;
    SHAPE ABUTMENT ;
    PORT
      LAYER M4 ;
      RECT 94.800 18.336 94.824 18.360 ;
    END
  END w_mask_in[64]
  PIN w_mask_in[65]
    DIRECTION INPUT ;
    USE SIGNAL ;
    SHAPE ABUTMENT ;
    PORT
      LAYER M4 ;
      RECT 94.800 18.432 94.824 18.456 ;
    END
  END w_mask_in[65]
  PIN w_mask_in[66]
    DIRECTION INPUT ;
    USE SIGNAL ;
    SHAPE ABUTMENT ;
    PORT
      LAYER M4 ;
      RECT 94.800 18.528 94.824 18.552 ;
    END
  END w_mask_in[66]
  PIN w_mask_in[67]
    DIRECTION INPUT ;
    USE SIGNAL ;
    SHAPE ABUTMENT ;
    PORT
      LAYER M4 ;
      RECT 94.800 18.624 94.824 18.648 ;
    END
  END w_mask_in[67]
  PIN w_mask_in[68]
    DIRECTION INPUT ;
    USE SIGNAL ;
    SHAPE ABUTMENT ;
    PORT
      LAYER M4 ;
      RECT 94.800 18.720 94.824 18.744 ;
    END
  END w_mask_in[68]
  PIN w_mask_in[69]
    DIRECTION INPUT ;
    USE SIGNAL ;
    SHAPE ABUTMENT ;
    PORT
      LAYER M4 ;
      RECT 94.800 18.816 94.824 18.840 ;
    END
  END w_mask_in[69]
  PIN w_mask_in[70]
    DIRECTION INPUT ;
    USE SIGNAL ;
    SHAPE ABUTMENT ;
    PORT
      LAYER M4 ;
      RECT 94.800 18.912 94.824 18.936 ;
    END
  END w_mask_in[70]
  PIN w_mask_in[71]
    DIRECTION INPUT ;
    USE SIGNAL ;
    SHAPE ABUTMENT ;
    PORT
      LAYER M4 ;
      RECT 94.800 19.008 94.824 19.032 ;
    END
  END w_mask_in[71]
  PIN w_mask_in[72]
    DIRECTION INPUT ;
    USE SIGNAL ;
    SHAPE ABUTMENT ;
    PORT
      LAYER M4 ;
      RECT 94.800 19.104 94.824 19.128 ;
    END
  END w_mask_in[72]
  PIN w_mask_in[73]
    DIRECTION INPUT ;
    USE SIGNAL ;
    SHAPE ABUTMENT ;
    PORT
      LAYER M4 ;
      RECT 94.800 19.200 94.824 19.224 ;
    END
  END w_mask_in[73]
  PIN w_mask_in[74]
    DIRECTION INPUT ;
    USE SIGNAL ;
    SHAPE ABUTMENT ;
    PORT
      LAYER M4 ;
      RECT 94.800 19.296 94.824 19.320 ;
    END
  END w_mask_in[74]
  PIN w_mask_in[75]
    DIRECTION INPUT ;
    USE SIGNAL ;
    SHAPE ABUTMENT ;
    PORT
      LAYER M4 ;
      RECT 94.800 19.392 94.824 19.416 ;
    END
  END w_mask_in[75]
  PIN w_mask_in[76]
    DIRECTION INPUT ;
    USE SIGNAL ;
    SHAPE ABUTMENT ;
    PORT
      LAYER M4 ;
      RECT 94.800 19.488 94.824 19.512 ;
    END
  END w_mask_in[76]
  PIN w_mask_in[77]
    DIRECTION INPUT ;
    USE SIGNAL ;
    SHAPE ABUTMENT ;
    PORT
      LAYER M4 ;
      RECT 94.800 19.584 94.824 19.608 ;
    END
  END w_mask_in[77]
  PIN w_mask_in[78]
    DIRECTION INPUT ;
    USE SIGNAL ;
    SHAPE ABUTMENT ;
    PORT
      LAYER M4 ;
      RECT 94.800 19.680 94.824 19.704 ;
    END
  END w_mask_in[78]
  PIN w_mask_in[79]
    DIRECTION INPUT ;
    USE SIGNAL ;
    SHAPE ABUTMENT ;
    PORT
      LAYER M4 ;
      RECT 94.800 19.776 94.824 19.800 ;
    END
  END w_mask_in[79]
  PIN w_mask_in[80]
    DIRECTION INPUT ;
    USE SIGNAL ;
    SHAPE ABUTMENT ;
    PORT
      LAYER M4 ;
      RECT 94.800 19.872 94.824 19.896 ;
    END
  END w_mask_in[80]
  PIN w_mask_in[81]
    DIRECTION INPUT ;
    USE SIGNAL ;
    SHAPE ABUTMENT ;
    PORT
      LAYER M4 ;
      RECT 94.800 19.968 94.824 19.992 ;
    END
  END w_mask_in[81]
  PIN w_mask_in[82]
    DIRECTION INPUT ;
    USE SIGNAL ;
    SHAPE ABUTMENT ;
    PORT
      LAYER M4 ;
      RECT 94.800 20.064 94.824 20.088 ;
    END
  END w_mask_in[82]
  PIN w_mask_in[83]
    DIRECTION INPUT ;
    USE SIGNAL ;
    SHAPE ABUTMENT ;
    PORT
      LAYER M4 ;
      RECT 94.800 20.160 94.824 20.184 ;
    END
  END w_mask_in[83]
  PIN w_mask_in[84]
    DIRECTION INPUT ;
    USE SIGNAL ;
    SHAPE ABUTMENT ;
    PORT
      LAYER M4 ;
      RECT 94.800 20.256 94.824 20.280 ;
    END
  END w_mask_in[84]
  PIN w_mask_in[85]
    DIRECTION INPUT ;
    USE SIGNAL ;
    SHAPE ABUTMENT ;
    PORT
      LAYER M4 ;
      RECT 94.800 20.352 94.824 20.376 ;
    END
  END w_mask_in[85]
  PIN w_mask_in[86]
    DIRECTION INPUT ;
    USE SIGNAL ;
    SHAPE ABUTMENT ;
    PORT
      LAYER M4 ;
      RECT 94.800 20.448 94.824 20.472 ;
    END
  END w_mask_in[86]
  PIN w_mask_in[87]
    DIRECTION INPUT ;
    USE SIGNAL ;
    SHAPE ABUTMENT ;
    PORT
      LAYER M4 ;
      RECT 94.800 20.544 94.824 20.568 ;
    END
  END w_mask_in[87]
  PIN w_mask_in[88]
    DIRECTION INPUT ;
    USE SIGNAL ;
    SHAPE ABUTMENT ;
    PORT
      LAYER M4 ;
      RECT 94.800 20.640 94.824 20.664 ;
    END
  END w_mask_in[88]
  PIN w_mask_in[89]
    DIRECTION INPUT ;
    USE SIGNAL ;
    SHAPE ABUTMENT ;
    PORT
      LAYER M4 ;
      RECT 94.800 20.736 94.824 20.760 ;
    END
  END w_mask_in[89]
  PIN w_mask_in[90]
    DIRECTION INPUT ;
    USE SIGNAL ;
    SHAPE ABUTMENT ;
    PORT
      LAYER M4 ;
      RECT 94.800 20.832 94.824 20.856 ;
    END
  END w_mask_in[90]
  PIN w_mask_in[91]
    DIRECTION INPUT ;
    USE SIGNAL ;
    SHAPE ABUTMENT ;
    PORT
      LAYER M4 ;
      RECT 94.800 20.928 94.824 20.952 ;
    END
  END w_mask_in[91]
  PIN w_mask_in[92]
    DIRECTION INPUT ;
    USE SIGNAL ;
    SHAPE ABUTMENT ;
    PORT
      LAYER M4 ;
      RECT 94.800 21.024 94.824 21.048 ;
    END
  END w_mask_in[92]
  PIN w_mask_in[93]
    DIRECTION INPUT ;
    USE SIGNAL ;
    SHAPE ABUTMENT ;
    PORT
      LAYER M4 ;
      RECT 94.800 21.120 94.824 21.144 ;
    END
  END w_mask_in[93]
  PIN w_mask_in[94]
    DIRECTION INPUT ;
    USE SIGNAL ;
    SHAPE ABUTMENT ;
    PORT
      LAYER M4 ;
      RECT 94.800 21.216 94.824 21.240 ;
    END
  END w_mask_in[94]
  PIN w_mask_in[95]
    DIRECTION INPUT ;
    USE SIGNAL ;
    SHAPE ABUTMENT ;
    PORT
      LAYER M4 ;
      RECT 94.800 21.312 94.824 21.336 ;
    END
  END w_mask_in[95]
  PIN w_mask_in[96]
    DIRECTION INPUT ;
    USE SIGNAL ;
    SHAPE ABUTMENT ;
    PORT
      LAYER M4 ;
      RECT 94.800 21.408 94.824 21.432 ;
    END
  END w_mask_in[96]
  PIN w_mask_in[97]
    DIRECTION INPUT ;
    USE SIGNAL ;
    SHAPE ABUTMENT ;
    PORT
      LAYER M4 ;
      RECT 94.800 21.504 94.824 21.528 ;
    END
  END w_mask_in[97]
  PIN w_mask_in[98]
    DIRECTION INPUT ;
    USE SIGNAL ;
    SHAPE ABUTMENT ;
    PORT
      LAYER M4 ;
      RECT 94.800 21.600 94.824 21.624 ;
    END
  END w_mask_in[98]
  PIN w_mask_in[99]
    DIRECTION INPUT ;
    USE SIGNAL ;
    SHAPE ABUTMENT ;
    PORT
      LAYER M4 ;
      RECT 94.800 21.696 94.824 21.720 ;
    END
  END w_mask_in[99]
  PIN w_mask_in[100]
    DIRECTION INPUT ;
    USE SIGNAL ;
    SHAPE ABUTMENT ;
    PORT
      LAYER M4 ;
      RECT 94.800 21.792 94.824 21.816 ;
    END
  END w_mask_in[100]
  PIN w_mask_in[101]
    DIRECTION INPUT ;
    USE SIGNAL ;
    SHAPE ABUTMENT ;
    PORT
      LAYER M4 ;
      RECT 94.800 21.888 94.824 21.912 ;
    END
  END w_mask_in[101]
  PIN w_mask_in[102]
    DIRECTION INPUT ;
    USE SIGNAL ;
    SHAPE ABUTMENT ;
    PORT
      LAYER M4 ;
      RECT 94.800 21.984 94.824 22.008 ;
    END
  END w_mask_in[102]
  PIN w_mask_in[103]
    DIRECTION INPUT ;
    USE SIGNAL ;
    SHAPE ABUTMENT ;
    PORT
      LAYER M4 ;
      RECT 94.800 22.080 94.824 22.104 ;
    END
  END w_mask_in[103]
  PIN w_mask_in[104]
    DIRECTION INPUT ;
    USE SIGNAL ;
    SHAPE ABUTMENT ;
    PORT
      LAYER M4 ;
      RECT 94.800 22.176 94.824 22.200 ;
    END
  END w_mask_in[104]
  PIN w_mask_in[105]
    DIRECTION INPUT ;
    USE SIGNAL ;
    SHAPE ABUTMENT ;
    PORT
      LAYER M4 ;
      RECT 94.800 22.272 94.824 22.296 ;
    END
  END w_mask_in[105]
  PIN w_mask_in[106]
    DIRECTION INPUT ;
    USE SIGNAL ;
    SHAPE ABUTMENT ;
    PORT
      LAYER M4 ;
      RECT 94.800 22.368 94.824 22.392 ;
    END
  END w_mask_in[106]
  PIN w_mask_in[107]
    DIRECTION INPUT ;
    USE SIGNAL ;
    SHAPE ABUTMENT ;
    PORT
      LAYER M4 ;
      RECT 94.800 22.464 94.824 22.488 ;
    END
  END w_mask_in[107]
  PIN w_mask_in[108]
    DIRECTION INPUT ;
    USE SIGNAL ;
    SHAPE ABUTMENT ;
    PORT
      LAYER M4 ;
      RECT 94.800 22.560 94.824 22.584 ;
    END
  END w_mask_in[108]
  PIN w_mask_in[109]
    DIRECTION INPUT ;
    USE SIGNAL ;
    SHAPE ABUTMENT ;
    PORT
      LAYER M4 ;
      RECT 94.800 22.656 94.824 22.680 ;
    END
  END w_mask_in[109]
  PIN w_mask_in[110]
    DIRECTION INPUT ;
    USE SIGNAL ;
    SHAPE ABUTMENT ;
    PORT
      LAYER M4 ;
      RECT 94.800 22.752 94.824 22.776 ;
    END
  END w_mask_in[110]
  PIN w_mask_in[111]
    DIRECTION INPUT ;
    USE SIGNAL ;
    SHAPE ABUTMENT ;
    PORT
      LAYER M4 ;
      RECT 94.800 22.848 94.824 22.872 ;
    END
  END w_mask_in[111]
  PIN w_mask_in[112]
    DIRECTION INPUT ;
    USE SIGNAL ;
    SHAPE ABUTMENT ;
    PORT
      LAYER M4 ;
      RECT 94.800 22.944 94.824 22.968 ;
    END
  END w_mask_in[112]
  PIN w_mask_in[113]
    DIRECTION INPUT ;
    USE SIGNAL ;
    SHAPE ABUTMENT ;
    PORT
      LAYER M4 ;
      RECT 94.800 23.040 94.824 23.064 ;
    END
  END w_mask_in[113]
  PIN w_mask_in[114]
    DIRECTION INPUT ;
    USE SIGNAL ;
    SHAPE ABUTMENT ;
    PORT
      LAYER M4 ;
      RECT 94.800 23.136 94.824 23.160 ;
    END
  END w_mask_in[114]
  PIN w_mask_in[115]
    DIRECTION INPUT ;
    USE SIGNAL ;
    SHAPE ABUTMENT ;
    PORT
      LAYER M4 ;
      RECT 94.800 23.232 94.824 23.256 ;
    END
  END w_mask_in[115]
  PIN w_mask_in[116]
    DIRECTION INPUT ;
    USE SIGNAL ;
    SHAPE ABUTMENT ;
    PORT
      LAYER M4 ;
      RECT 94.800 23.328 94.824 23.352 ;
    END
  END w_mask_in[116]
  PIN w_mask_in[117]
    DIRECTION INPUT ;
    USE SIGNAL ;
    SHAPE ABUTMENT ;
    PORT
      LAYER M4 ;
      RECT 94.800 23.424 94.824 23.448 ;
    END
  END w_mask_in[117]
  PIN w_mask_in[118]
    DIRECTION INPUT ;
    USE SIGNAL ;
    SHAPE ABUTMENT ;
    PORT
      LAYER M4 ;
      RECT 94.800 23.520 94.824 23.544 ;
    END
  END w_mask_in[118]
  PIN w_mask_in[119]
    DIRECTION INPUT ;
    USE SIGNAL ;
    SHAPE ABUTMENT ;
    PORT
      LAYER M4 ;
      RECT 94.800 23.616 94.824 23.640 ;
    END
  END w_mask_in[119]
  PIN w_mask_in[120]
    DIRECTION INPUT ;
    USE SIGNAL ;
    SHAPE ABUTMENT ;
    PORT
      LAYER M4 ;
      RECT 94.800 23.712 94.824 23.736 ;
    END
  END w_mask_in[120]
  PIN w_mask_in[121]
    DIRECTION INPUT ;
    USE SIGNAL ;
    SHAPE ABUTMENT ;
    PORT
      LAYER M4 ;
      RECT 94.800 23.808 94.824 23.832 ;
    END
  END w_mask_in[121]
  PIN w_mask_in[122]
    DIRECTION INPUT ;
    USE SIGNAL ;
    SHAPE ABUTMENT ;
    PORT
      LAYER M4 ;
      RECT 94.800 23.904 94.824 23.928 ;
    END
  END w_mask_in[122]
  PIN w_mask_in[123]
    DIRECTION INPUT ;
    USE SIGNAL ;
    SHAPE ABUTMENT ;
    PORT
      LAYER M4 ;
      RECT 94.800 24.000 94.824 24.024 ;
    END
  END w_mask_in[123]
  PIN w_mask_in[124]
    DIRECTION INPUT ;
    USE SIGNAL ;
    SHAPE ABUTMENT ;
    PORT
      LAYER M4 ;
      RECT 94.800 24.096 94.824 24.120 ;
    END
  END w_mask_in[124]
  PIN w_mask_in[125]
    DIRECTION INPUT ;
    USE SIGNAL ;
    SHAPE ABUTMENT ;
    PORT
      LAYER M4 ;
      RECT 94.800 24.192 94.824 24.216 ;
    END
  END w_mask_in[125]
  PIN w_mask_in[126]
    DIRECTION INPUT ;
    USE SIGNAL ;
    SHAPE ABUTMENT ;
    PORT
      LAYER M4 ;
      RECT 94.800 24.288 94.824 24.312 ;
    END
  END w_mask_in[126]
  PIN w_mask_in[127]
    DIRECTION INPUT ;
    USE SIGNAL ;
    SHAPE ABUTMENT ;
    PORT
      LAYER M4 ;
      RECT 94.800 24.384 94.824 24.408 ;
    END
  END w_mask_in[127]
  PIN w_mask_in[128]
    DIRECTION INPUT ;
    USE SIGNAL ;
    SHAPE ABUTMENT ;
    PORT
      LAYER M4 ;
      RECT 94.800 24.480 94.824 24.504 ;
    END
  END w_mask_in[128]
  PIN w_mask_in[129]
    DIRECTION INPUT ;
    USE SIGNAL ;
    SHAPE ABUTMENT ;
    PORT
      LAYER M4 ;
      RECT 94.800 24.576 94.824 24.600 ;
    END
  END w_mask_in[129]
  PIN w_mask_in[130]
    DIRECTION INPUT ;
    USE SIGNAL ;
    SHAPE ABUTMENT ;
    PORT
      LAYER M4 ;
      RECT 94.800 24.672 94.824 24.696 ;
    END
  END w_mask_in[130]
  PIN w_mask_in[131]
    DIRECTION INPUT ;
    USE SIGNAL ;
    SHAPE ABUTMENT ;
    PORT
      LAYER M4 ;
      RECT 94.800 24.768 94.824 24.792 ;
    END
  END w_mask_in[131]
  PIN w_mask_in[132]
    DIRECTION INPUT ;
    USE SIGNAL ;
    SHAPE ABUTMENT ;
    PORT
      LAYER M4 ;
      RECT 94.800 24.864 94.824 24.888 ;
    END
  END w_mask_in[132]
  PIN w_mask_in[133]
    DIRECTION INPUT ;
    USE SIGNAL ;
    SHAPE ABUTMENT ;
    PORT
      LAYER M4 ;
      RECT 94.800 24.960 94.824 24.984 ;
    END
  END w_mask_in[133]
  PIN w_mask_in[134]
    DIRECTION INPUT ;
    USE SIGNAL ;
    SHAPE ABUTMENT ;
    PORT
      LAYER M4 ;
      RECT 94.800 25.056 94.824 25.080 ;
    END
  END w_mask_in[134]
  PIN w_mask_in[135]
    DIRECTION INPUT ;
    USE SIGNAL ;
    SHAPE ABUTMENT ;
    PORT
      LAYER M4 ;
      RECT 94.800 25.152 94.824 25.176 ;
    END
  END w_mask_in[135]
  PIN w_mask_in[136]
    DIRECTION INPUT ;
    USE SIGNAL ;
    SHAPE ABUTMENT ;
    PORT
      LAYER M4 ;
      RECT 94.800 25.248 94.824 25.272 ;
    END
  END w_mask_in[136]
  PIN w_mask_in[137]
    DIRECTION INPUT ;
    USE SIGNAL ;
    SHAPE ABUTMENT ;
    PORT
      LAYER M4 ;
      RECT 94.800 25.344 94.824 25.368 ;
    END
  END w_mask_in[137]
  PIN w_mask_in[138]
    DIRECTION INPUT ;
    USE SIGNAL ;
    SHAPE ABUTMENT ;
    PORT
      LAYER M4 ;
      RECT 94.800 25.440 94.824 25.464 ;
    END
  END w_mask_in[138]
  PIN w_mask_in[139]
    DIRECTION INPUT ;
    USE SIGNAL ;
    SHAPE ABUTMENT ;
    PORT
      LAYER M4 ;
      RECT 94.800 25.536 94.824 25.560 ;
    END
  END w_mask_in[139]
  PIN w_mask_in[140]
    DIRECTION INPUT ;
    USE SIGNAL ;
    SHAPE ABUTMENT ;
    PORT
      LAYER M4 ;
      RECT 94.800 25.632 94.824 25.656 ;
    END
  END w_mask_in[140]
  PIN w_mask_in[141]
    DIRECTION INPUT ;
    USE SIGNAL ;
    SHAPE ABUTMENT ;
    PORT
      LAYER M4 ;
      RECT 94.800 25.728 94.824 25.752 ;
    END
  END w_mask_in[141]
  PIN w_mask_in[142]
    DIRECTION INPUT ;
    USE SIGNAL ;
    SHAPE ABUTMENT ;
    PORT
      LAYER M4 ;
      RECT 94.800 25.824 94.824 25.848 ;
    END
  END w_mask_in[142]
  PIN w_mask_in[143]
    DIRECTION INPUT ;
    USE SIGNAL ;
    SHAPE ABUTMENT ;
    PORT
      LAYER M4 ;
      RECT 94.800 25.920 94.824 25.944 ;
    END
  END w_mask_in[143]
  PIN w_mask_in[144]
    DIRECTION INPUT ;
    USE SIGNAL ;
    SHAPE ABUTMENT ;
    PORT
      LAYER M4 ;
      RECT 94.800 26.016 94.824 26.040 ;
    END
  END w_mask_in[144]
  PIN w_mask_in[145]
    DIRECTION INPUT ;
    USE SIGNAL ;
    SHAPE ABUTMENT ;
    PORT
      LAYER M4 ;
      RECT 94.800 26.112 94.824 26.136 ;
    END
  END w_mask_in[145]
  PIN w_mask_in[146]
    DIRECTION INPUT ;
    USE SIGNAL ;
    SHAPE ABUTMENT ;
    PORT
      LAYER M4 ;
      RECT 94.800 26.208 94.824 26.232 ;
    END
  END w_mask_in[146]
  PIN w_mask_in[147]
    DIRECTION INPUT ;
    USE SIGNAL ;
    SHAPE ABUTMENT ;
    PORT
      LAYER M4 ;
      RECT 94.800 26.304 94.824 26.328 ;
    END
  END w_mask_in[147]
  PIN w_mask_in[148]
    DIRECTION INPUT ;
    USE SIGNAL ;
    SHAPE ABUTMENT ;
    PORT
      LAYER M4 ;
      RECT 94.800 26.400 94.824 26.424 ;
    END
  END w_mask_in[148]
  PIN w_mask_in[149]
    DIRECTION INPUT ;
    USE SIGNAL ;
    SHAPE ABUTMENT ;
    PORT
      LAYER M4 ;
      RECT 94.800 26.496 94.824 26.520 ;
    END
  END w_mask_in[149]
  PIN w_mask_in[150]
    DIRECTION INPUT ;
    USE SIGNAL ;
    SHAPE ABUTMENT ;
    PORT
      LAYER M4 ;
      RECT 94.800 26.592 94.824 26.616 ;
    END
  END w_mask_in[150]
  PIN w_mask_in[151]
    DIRECTION INPUT ;
    USE SIGNAL ;
    SHAPE ABUTMENT ;
    PORT
      LAYER M4 ;
      RECT 94.800 26.688 94.824 26.712 ;
    END
  END w_mask_in[151]
  PIN w_mask_in[152]
    DIRECTION INPUT ;
    USE SIGNAL ;
    SHAPE ABUTMENT ;
    PORT
      LAYER M4 ;
      RECT 94.800 26.784 94.824 26.808 ;
    END
  END w_mask_in[152]
  PIN w_mask_in[153]
    DIRECTION INPUT ;
    USE SIGNAL ;
    SHAPE ABUTMENT ;
    PORT
      LAYER M4 ;
      RECT 94.800 26.880 94.824 26.904 ;
    END
  END w_mask_in[153]
  PIN w_mask_in[154]
    DIRECTION INPUT ;
    USE SIGNAL ;
    SHAPE ABUTMENT ;
    PORT
      LAYER M4 ;
      RECT 94.800 26.976 94.824 27.000 ;
    END
  END w_mask_in[154]
  PIN w_mask_in[155]
    DIRECTION INPUT ;
    USE SIGNAL ;
    SHAPE ABUTMENT ;
    PORT
      LAYER M4 ;
      RECT 94.800 27.072 94.824 27.096 ;
    END
  END w_mask_in[155]
  PIN w_mask_in[156]
    DIRECTION INPUT ;
    USE SIGNAL ;
    SHAPE ABUTMENT ;
    PORT
      LAYER M4 ;
      RECT 94.800 27.168 94.824 27.192 ;
    END
  END w_mask_in[156]
  PIN w_mask_in[157]
    DIRECTION INPUT ;
    USE SIGNAL ;
    SHAPE ABUTMENT ;
    PORT
      LAYER M4 ;
      RECT 94.800 27.264 94.824 27.288 ;
    END
  END w_mask_in[157]
  PIN w_mask_in[158]
    DIRECTION INPUT ;
    USE SIGNAL ;
    SHAPE ABUTMENT ;
    PORT
      LAYER M4 ;
      RECT 94.800 27.360 94.824 27.384 ;
    END
  END w_mask_in[158]
  PIN w_mask_in[159]
    DIRECTION INPUT ;
    USE SIGNAL ;
    SHAPE ABUTMENT ;
    PORT
      LAYER M4 ;
      RECT 94.800 27.456 94.824 27.480 ;
    END
  END w_mask_in[159]
  PIN w_mask_in[160]
    DIRECTION INPUT ;
    USE SIGNAL ;
    SHAPE ABUTMENT ;
    PORT
      LAYER M4 ;
      RECT 94.800 27.552 94.824 27.576 ;
    END
  END w_mask_in[160]
  PIN w_mask_in[161]
    DIRECTION INPUT ;
    USE SIGNAL ;
    SHAPE ABUTMENT ;
    PORT
      LAYER M4 ;
      RECT 94.800 27.648 94.824 27.672 ;
    END
  END w_mask_in[161]
  PIN w_mask_in[162]
    DIRECTION INPUT ;
    USE SIGNAL ;
    SHAPE ABUTMENT ;
    PORT
      LAYER M4 ;
      RECT 94.800 27.744 94.824 27.768 ;
    END
  END w_mask_in[162]
  PIN w_mask_in[163]
    DIRECTION INPUT ;
    USE SIGNAL ;
    SHAPE ABUTMENT ;
    PORT
      LAYER M4 ;
      RECT 94.800 27.840 94.824 27.864 ;
    END
  END w_mask_in[163]
  PIN w_mask_in[164]
    DIRECTION INPUT ;
    USE SIGNAL ;
    SHAPE ABUTMENT ;
    PORT
      LAYER M4 ;
      RECT 94.800 27.936 94.824 27.960 ;
    END
  END w_mask_in[164]
  PIN w_mask_in[165]
    DIRECTION INPUT ;
    USE SIGNAL ;
    SHAPE ABUTMENT ;
    PORT
      LAYER M4 ;
      RECT 94.800 28.032 94.824 28.056 ;
    END
  END w_mask_in[165]
  PIN w_mask_in[166]
    DIRECTION INPUT ;
    USE SIGNAL ;
    SHAPE ABUTMENT ;
    PORT
      LAYER M4 ;
      RECT 94.800 28.128 94.824 28.152 ;
    END
  END w_mask_in[166]
  PIN w_mask_in[167]
    DIRECTION INPUT ;
    USE SIGNAL ;
    SHAPE ABUTMENT ;
    PORT
      LAYER M4 ;
      RECT 94.800 28.224 94.824 28.248 ;
    END
  END w_mask_in[167]
  PIN w_mask_in[168]
    DIRECTION INPUT ;
    USE SIGNAL ;
    SHAPE ABUTMENT ;
    PORT
      LAYER M4 ;
      RECT 94.800 28.320 94.824 28.344 ;
    END
  END w_mask_in[168]
  PIN w_mask_in[169]
    DIRECTION INPUT ;
    USE SIGNAL ;
    SHAPE ABUTMENT ;
    PORT
      LAYER M4 ;
      RECT 94.800 28.416 94.824 28.440 ;
    END
  END w_mask_in[169]
  PIN w_mask_in[170]
    DIRECTION INPUT ;
    USE SIGNAL ;
    SHAPE ABUTMENT ;
    PORT
      LAYER M4 ;
      RECT 94.800 28.512 94.824 28.536 ;
    END
  END w_mask_in[170]
  PIN w_mask_in[171]
    DIRECTION INPUT ;
    USE SIGNAL ;
    SHAPE ABUTMENT ;
    PORT
      LAYER M4 ;
      RECT 94.800 28.608 94.824 28.632 ;
    END
  END w_mask_in[171]
  PIN w_mask_in[172]
    DIRECTION INPUT ;
    USE SIGNAL ;
    SHAPE ABUTMENT ;
    PORT
      LAYER M4 ;
      RECT 94.800 28.704 94.824 28.728 ;
    END
  END w_mask_in[172]
  PIN w_mask_in[173]
    DIRECTION INPUT ;
    USE SIGNAL ;
    SHAPE ABUTMENT ;
    PORT
      LAYER M4 ;
      RECT 94.800 28.800 94.824 28.824 ;
    END
  END w_mask_in[173]
  PIN w_mask_in[174]
    DIRECTION INPUT ;
    USE SIGNAL ;
    SHAPE ABUTMENT ;
    PORT
      LAYER M4 ;
      RECT 94.800 28.896 94.824 28.920 ;
    END
  END w_mask_in[174]
  PIN w_mask_in[175]
    DIRECTION INPUT ;
    USE SIGNAL ;
    SHAPE ABUTMENT ;
    PORT
      LAYER M4 ;
      RECT 94.800 28.992 94.824 29.016 ;
    END
  END w_mask_in[175]
  PIN w_mask_in[176]
    DIRECTION INPUT ;
    USE SIGNAL ;
    SHAPE ABUTMENT ;
    PORT
      LAYER M4 ;
      RECT 94.800 29.088 94.824 29.112 ;
    END
  END w_mask_in[176]
  PIN w_mask_in[177]
    DIRECTION INPUT ;
    USE SIGNAL ;
    SHAPE ABUTMENT ;
    PORT
      LAYER M4 ;
      RECT 94.800 29.184 94.824 29.208 ;
    END
  END w_mask_in[177]
  PIN w_mask_in[178]
    DIRECTION INPUT ;
    USE SIGNAL ;
    SHAPE ABUTMENT ;
    PORT
      LAYER M4 ;
      RECT 94.800 29.280 94.824 29.304 ;
    END
  END w_mask_in[178]
  PIN w_mask_in[179]
    DIRECTION INPUT ;
    USE SIGNAL ;
    SHAPE ABUTMENT ;
    PORT
      LAYER M4 ;
      RECT 94.800 29.376 94.824 29.400 ;
    END
  END w_mask_in[179]
  PIN w_mask_in[180]
    DIRECTION INPUT ;
    USE SIGNAL ;
    SHAPE ABUTMENT ;
    PORT
      LAYER M4 ;
      RECT 94.800 29.472 94.824 29.496 ;
    END
  END w_mask_in[180]
  PIN w_mask_in[181]
    DIRECTION INPUT ;
    USE SIGNAL ;
    SHAPE ABUTMENT ;
    PORT
      LAYER M4 ;
      RECT 94.800 29.568 94.824 29.592 ;
    END
  END w_mask_in[181]
  PIN w_mask_in[182]
    DIRECTION INPUT ;
    USE SIGNAL ;
    SHAPE ABUTMENT ;
    PORT
      LAYER M4 ;
      RECT 94.800 29.664 94.824 29.688 ;
    END
  END w_mask_in[182]
  PIN w_mask_in[183]
    DIRECTION INPUT ;
    USE SIGNAL ;
    SHAPE ABUTMENT ;
    PORT
      LAYER M4 ;
      RECT 94.800 29.760 94.824 29.784 ;
    END
  END w_mask_in[183]
  PIN w_mask_in[184]
    DIRECTION INPUT ;
    USE SIGNAL ;
    SHAPE ABUTMENT ;
    PORT
      LAYER M4 ;
      RECT 94.800 29.856 94.824 29.880 ;
    END
  END w_mask_in[184]
  PIN w_mask_in[185]
    DIRECTION INPUT ;
    USE SIGNAL ;
    SHAPE ABUTMENT ;
    PORT
      LAYER M4 ;
      RECT 94.800 29.952 94.824 29.976 ;
    END
  END w_mask_in[185]
  PIN w_mask_in[186]
    DIRECTION INPUT ;
    USE SIGNAL ;
    SHAPE ABUTMENT ;
    PORT
      LAYER M4 ;
      RECT 94.800 30.048 94.824 30.072 ;
    END
  END w_mask_in[186]
  PIN w_mask_in[187]
    DIRECTION INPUT ;
    USE SIGNAL ;
    SHAPE ABUTMENT ;
    PORT
      LAYER M4 ;
      RECT 94.800 30.144 94.824 30.168 ;
    END
  END w_mask_in[187]
  PIN w_mask_in[188]
    DIRECTION INPUT ;
    USE SIGNAL ;
    SHAPE ABUTMENT ;
    PORT
      LAYER M4 ;
      RECT 94.800 30.240 94.824 30.264 ;
    END
  END w_mask_in[188]
  PIN w_mask_in[189]
    DIRECTION INPUT ;
    USE SIGNAL ;
    SHAPE ABUTMENT ;
    PORT
      LAYER M4 ;
      RECT 94.800 30.336 94.824 30.360 ;
    END
  END w_mask_in[189]
  PIN w_mask_in[190]
    DIRECTION INPUT ;
    USE SIGNAL ;
    SHAPE ABUTMENT ;
    PORT
      LAYER M4 ;
      RECT 94.800 30.432 94.824 30.456 ;
    END
  END w_mask_in[190]
  PIN w_mask_in[191]
    DIRECTION INPUT ;
    USE SIGNAL ;
    SHAPE ABUTMENT ;
    PORT
      LAYER M4 ;
      RECT 94.800 30.528 94.824 30.552 ;
    END
  END w_mask_in[191]
  PIN w_mask_in[192]
    DIRECTION INPUT ;
    USE SIGNAL ;
    SHAPE ABUTMENT ;
    PORT
      LAYER M4 ;
      RECT 94.800 30.624 94.824 30.648 ;
    END
  END w_mask_in[192]
  PIN w_mask_in[193]
    DIRECTION INPUT ;
    USE SIGNAL ;
    SHAPE ABUTMENT ;
    PORT
      LAYER M4 ;
      RECT 94.800 30.720 94.824 30.744 ;
    END
  END w_mask_in[193]
  PIN w_mask_in[194]
    DIRECTION INPUT ;
    USE SIGNAL ;
    SHAPE ABUTMENT ;
    PORT
      LAYER M4 ;
      RECT 94.800 30.816 94.824 30.840 ;
    END
  END w_mask_in[194]
  PIN w_mask_in[195]
    DIRECTION INPUT ;
    USE SIGNAL ;
    SHAPE ABUTMENT ;
    PORT
      LAYER M4 ;
      RECT 94.800 30.912 94.824 30.936 ;
    END
  END w_mask_in[195]
  PIN w_mask_in[196]
    DIRECTION INPUT ;
    USE SIGNAL ;
    SHAPE ABUTMENT ;
    PORT
      LAYER M4 ;
      RECT 94.800 31.008 94.824 31.032 ;
    END
  END w_mask_in[196]
  PIN w_mask_in[197]
    DIRECTION INPUT ;
    USE SIGNAL ;
    SHAPE ABUTMENT ;
    PORT
      LAYER M4 ;
      RECT 94.800 31.104 94.824 31.128 ;
    END
  END w_mask_in[197]
  PIN w_mask_in[198]
    DIRECTION INPUT ;
    USE SIGNAL ;
    SHAPE ABUTMENT ;
    PORT
      LAYER M4 ;
      RECT 94.800 31.200 94.824 31.224 ;
    END
  END w_mask_in[198]
  PIN w_mask_in[199]
    DIRECTION INPUT ;
    USE SIGNAL ;
    SHAPE ABUTMENT ;
    PORT
      LAYER M4 ;
      RECT 94.800 31.296 94.824 31.320 ;
    END
  END w_mask_in[199]
  PIN w_mask_in[200]
    DIRECTION INPUT ;
    USE SIGNAL ;
    SHAPE ABUTMENT ;
    PORT
      LAYER M4 ;
      RECT 94.800 31.392 94.824 31.416 ;
    END
  END w_mask_in[200]
  PIN w_mask_in[201]
    DIRECTION INPUT ;
    USE SIGNAL ;
    SHAPE ABUTMENT ;
    PORT
      LAYER M4 ;
      RECT 94.800 31.488 94.824 31.512 ;
    END
  END w_mask_in[201]
  PIN w_mask_in[202]
    DIRECTION INPUT ;
    USE SIGNAL ;
    SHAPE ABUTMENT ;
    PORT
      LAYER M4 ;
      RECT 94.800 31.584 94.824 31.608 ;
    END
  END w_mask_in[202]
  PIN w_mask_in[203]
    DIRECTION INPUT ;
    USE SIGNAL ;
    SHAPE ABUTMENT ;
    PORT
      LAYER M4 ;
      RECT 94.800 31.680 94.824 31.704 ;
    END
  END w_mask_in[203]
  PIN w_mask_in[204]
    DIRECTION INPUT ;
    USE SIGNAL ;
    SHAPE ABUTMENT ;
    PORT
      LAYER M4 ;
      RECT 94.800 31.776 94.824 31.800 ;
    END
  END w_mask_in[204]
  PIN w_mask_in[205]
    DIRECTION INPUT ;
    USE SIGNAL ;
    SHAPE ABUTMENT ;
    PORT
      LAYER M4 ;
      RECT 94.800 31.872 94.824 31.896 ;
    END
  END w_mask_in[205]
  PIN w_mask_in[206]
    DIRECTION INPUT ;
    USE SIGNAL ;
    SHAPE ABUTMENT ;
    PORT
      LAYER M4 ;
      RECT 94.800 31.968 94.824 31.992 ;
    END
  END w_mask_in[206]
  PIN w_mask_in[207]
    DIRECTION INPUT ;
    USE SIGNAL ;
    SHAPE ABUTMENT ;
    PORT
      LAYER M4 ;
      RECT 94.800 32.064 94.824 32.088 ;
    END
  END w_mask_in[207]
  PIN w_mask_in[208]
    DIRECTION INPUT ;
    USE SIGNAL ;
    SHAPE ABUTMENT ;
    PORT
      LAYER M4 ;
      RECT 94.800 32.160 94.824 32.184 ;
    END
  END w_mask_in[208]
  PIN w_mask_in[209]
    DIRECTION INPUT ;
    USE SIGNAL ;
    SHAPE ABUTMENT ;
    PORT
      LAYER M4 ;
      RECT 94.800 32.256 94.824 32.280 ;
    END
  END w_mask_in[209]
  PIN w_mask_in[210]
    DIRECTION INPUT ;
    USE SIGNAL ;
    SHAPE ABUTMENT ;
    PORT
      LAYER M4 ;
      RECT 94.800 32.352 94.824 32.376 ;
    END
  END w_mask_in[210]
  PIN w_mask_in[211]
    DIRECTION INPUT ;
    USE SIGNAL ;
    SHAPE ABUTMENT ;
    PORT
      LAYER M4 ;
      RECT 94.800 32.448 94.824 32.472 ;
    END
  END w_mask_in[211]
  PIN w_mask_in[212]
    DIRECTION INPUT ;
    USE SIGNAL ;
    SHAPE ABUTMENT ;
    PORT
      LAYER M4 ;
      RECT 94.800 32.544 94.824 32.568 ;
    END
  END w_mask_in[212]
  PIN w_mask_in[213]
    DIRECTION INPUT ;
    USE SIGNAL ;
    SHAPE ABUTMENT ;
    PORT
      LAYER M4 ;
      RECT 94.800 32.640 94.824 32.664 ;
    END
  END w_mask_in[213]
  PIN w_mask_in[214]
    DIRECTION INPUT ;
    USE SIGNAL ;
    SHAPE ABUTMENT ;
    PORT
      LAYER M4 ;
      RECT 94.800 32.736 94.824 32.760 ;
    END
  END w_mask_in[214]
  PIN w_mask_in[215]
    DIRECTION INPUT ;
    USE SIGNAL ;
    SHAPE ABUTMENT ;
    PORT
      LAYER M4 ;
      RECT 94.800 32.832 94.824 32.856 ;
    END
  END w_mask_in[215]
  PIN w_mask_in[216]
    DIRECTION INPUT ;
    USE SIGNAL ;
    SHAPE ABUTMENT ;
    PORT
      LAYER M4 ;
      RECT 94.800 32.928 94.824 32.952 ;
    END
  END w_mask_in[216]
  PIN w_mask_in[217]
    DIRECTION INPUT ;
    USE SIGNAL ;
    SHAPE ABUTMENT ;
    PORT
      LAYER M4 ;
      RECT 94.800 33.024 94.824 33.048 ;
    END
  END w_mask_in[217]
  PIN w_mask_in[218]
    DIRECTION INPUT ;
    USE SIGNAL ;
    SHAPE ABUTMENT ;
    PORT
      LAYER M4 ;
      RECT 94.800 33.120 94.824 33.144 ;
    END
  END w_mask_in[218]
  PIN w_mask_in[219]
    DIRECTION INPUT ;
    USE SIGNAL ;
    SHAPE ABUTMENT ;
    PORT
      LAYER M4 ;
      RECT 94.800 33.216 94.824 33.240 ;
    END
  END w_mask_in[219]
  PIN w_mask_in[220]
    DIRECTION INPUT ;
    USE SIGNAL ;
    SHAPE ABUTMENT ;
    PORT
      LAYER M4 ;
      RECT 94.800 33.312 94.824 33.336 ;
    END
  END w_mask_in[220]
  PIN w_mask_in[221]
    DIRECTION INPUT ;
    USE SIGNAL ;
    SHAPE ABUTMENT ;
    PORT
      LAYER M4 ;
      RECT 94.800 33.408 94.824 33.432 ;
    END
  END w_mask_in[221]
  PIN w_mask_in[222]
    DIRECTION INPUT ;
    USE SIGNAL ;
    SHAPE ABUTMENT ;
    PORT
      LAYER M4 ;
      RECT 94.800 33.504 94.824 33.528 ;
    END
  END w_mask_in[222]
  PIN w_mask_in[223]
    DIRECTION INPUT ;
    USE SIGNAL ;
    SHAPE ABUTMENT ;
    PORT
      LAYER M4 ;
      RECT 94.800 33.600 94.824 33.624 ;
    END
  END w_mask_in[223]
  PIN w_mask_in[224]
    DIRECTION INPUT ;
    USE SIGNAL ;
    SHAPE ABUTMENT ;
    PORT
      LAYER M4 ;
      RECT 94.800 33.696 94.824 33.720 ;
    END
  END w_mask_in[224]
  PIN w_mask_in[225]
    DIRECTION INPUT ;
    USE SIGNAL ;
    SHAPE ABUTMENT ;
    PORT
      LAYER M4 ;
      RECT 94.800 33.792 94.824 33.816 ;
    END
  END w_mask_in[225]
  PIN w_mask_in[226]
    DIRECTION INPUT ;
    USE SIGNAL ;
    SHAPE ABUTMENT ;
    PORT
      LAYER M4 ;
      RECT 94.800 33.888 94.824 33.912 ;
    END
  END w_mask_in[226]
  PIN w_mask_in[227]
    DIRECTION INPUT ;
    USE SIGNAL ;
    SHAPE ABUTMENT ;
    PORT
      LAYER M4 ;
      RECT 94.800 33.984 94.824 34.008 ;
    END
  END w_mask_in[227]
  PIN w_mask_in[228]
    DIRECTION INPUT ;
    USE SIGNAL ;
    SHAPE ABUTMENT ;
    PORT
      LAYER M4 ;
      RECT 94.800 34.080 94.824 34.104 ;
    END
  END w_mask_in[228]
  PIN w_mask_in[229]
    DIRECTION INPUT ;
    USE SIGNAL ;
    SHAPE ABUTMENT ;
    PORT
      LAYER M4 ;
      RECT 94.800 34.176 94.824 34.200 ;
    END
  END w_mask_in[229]
  PIN w_mask_in[230]
    DIRECTION INPUT ;
    USE SIGNAL ;
    SHAPE ABUTMENT ;
    PORT
      LAYER M4 ;
      RECT 94.800 34.272 94.824 34.296 ;
    END
  END w_mask_in[230]
  PIN w_mask_in[231]
    DIRECTION INPUT ;
    USE SIGNAL ;
    SHAPE ABUTMENT ;
    PORT
      LAYER M4 ;
      RECT 94.800 34.368 94.824 34.392 ;
    END
  END w_mask_in[231]
  PIN w_mask_in[232]
    DIRECTION INPUT ;
    USE SIGNAL ;
    SHAPE ABUTMENT ;
    PORT
      LAYER M4 ;
      RECT 94.800 34.464 94.824 34.488 ;
    END
  END w_mask_in[232]
  PIN w_mask_in[233]
    DIRECTION INPUT ;
    USE SIGNAL ;
    SHAPE ABUTMENT ;
    PORT
      LAYER M4 ;
      RECT 94.800 34.560 94.824 34.584 ;
    END
  END w_mask_in[233]
  PIN w_mask_in[234]
    DIRECTION INPUT ;
    USE SIGNAL ;
    SHAPE ABUTMENT ;
    PORT
      LAYER M4 ;
      RECT 94.800 34.656 94.824 34.680 ;
    END
  END w_mask_in[234]
  PIN w_mask_in[235]
    DIRECTION INPUT ;
    USE SIGNAL ;
    SHAPE ABUTMENT ;
    PORT
      LAYER M4 ;
      RECT 94.800 34.752 94.824 34.776 ;
    END
  END w_mask_in[235]
  PIN w_mask_in[236]
    DIRECTION INPUT ;
    USE SIGNAL ;
    SHAPE ABUTMENT ;
    PORT
      LAYER M4 ;
      RECT 94.800 34.848 94.824 34.872 ;
    END
  END w_mask_in[236]
  PIN w_mask_in[237]
    DIRECTION INPUT ;
    USE SIGNAL ;
    SHAPE ABUTMENT ;
    PORT
      LAYER M4 ;
      RECT 94.800 34.944 94.824 34.968 ;
    END
  END w_mask_in[237]
  PIN w_mask_in[238]
    DIRECTION INPUT ;
    USE SIGNAL ;
    SHAPE ABUTMENT ;
    PORT
      LAYER M4 ;
      RECT 94.800 35.040 94.824 35.064 ;
    END
  END w_mask_in[238]
  PIN w_mask_in[239]
    DIRECTION INPUT ;
    USE SIGNAL ;
    SHAPE ABUTMENT ;
    PORT
      LAYER M4 ;
      RECT 94.800 35.136 94.824 35.160 ;
    END
  END w_mask_in[239]
  PIN w_mask_in[240]
    DIRECTION INPUT ;
    USE SIGNAL ;
    SHAPE ABUTMENT ;
    PORT
      LAYER M4 ;
      RECT 94.800 35.232 94.824 35.256 ;
    END
  END w_mask_in[240]
  PIN w_mask_in[241]
    DIRECTION INPUT ;
    USE SIGNAL ;
    SHAPE ABUTMENT ;
    PORT
      LAYER M4 ;
      RECT 94.800 35.328 94.824 35.352 ;
    END
  END w_mask_in[241]
  PIN w_mask_in[242]
    DIRECTION INPUT ;
    USE SIGNAL ;
    SHAPE ABUTMENT ;
    PORT
      LAYER M4 ;
      RECT 94.800 35.424 94.824 35.448 ;
    END
  END w_mask_in[242]
  PIN w_mask_in[243]
    DIRECTION INPUT ;
    USE SIGNAL ;
    SHAPE ABUTMENT ;
    PORT
      LAYER M4 ;
      RECT 94.800 35.520 94.824 35.544 ;
    END
  END w_mask_in[243]
  PIN w_mask_in[244]
    DIRECTION INPUT ;
    USE SIGNAL ;
    SHAPE ABUTMENT ;
    PORT
      LAYER M4 ;
      RECT 94.800 35.616 94.824 35.640 ;
    END
  END w_mask_in[244]
  PIN w_mask_in[245]
    DIRECTION INPUT ;
    USE SIGNAL ;
    SHAPE ABUTMENT ;
    PORT
      LAYER M4 ;
      RECT 94.800 35.712 94.824 35.736 ;
    END
  END w_mask_in[245]
  PIN w_mask_in[246]
    DIRECTION INPUT ;
    USE SIGNAL ;
    SHAPE ABUTMENT ;
    PORT
      LAYER M4 ;
      RECT 94.800 35.808 94.824 35.832 ;
    END
  END w_mask_in[246]
  PIN w_mask_in[247]
    DIRECTION INPUT ;
    USE SIGNAL ;
    SHAPE ABUTMENT ;
    PORT
      LAYER M4 ;
      RECT 94.800 35.904 94.824 35.928 ;
    END
  END w_mask_in[247]
  PIN w_mask_in[248]
    DIRECTION INPUT ;
    USE SIGNAL ;
    SHAPE ABUTMENT ;
    PORT
      LAYER M4 ;
      RECT 94.800 36.000 94.824 36.024 ;
    END
  END w_mask_in[248]
  PIN w_mask_in[249]
    DIRECTION INPUT ;
    USE SIGNAL ;
    SHAPE ABUTMENT ;
    PORT
      LAYER M4 ;
      RECT 94.800 36.096 94.824 36.120 ;
    END
  END w_mask_in[249]
  PIN w_mask_in[250]
    DIRECTION INPUT ;
    USE SIGNAL ;
    SHAPE ABUTMENT ;
    PORT
      LAYER M4 ;
      RECT 94.800 36.192 94.824 36.216 ;
    END
  END w_mask_in[250]
  PIN w_mask_in[251]
    DIRECTION INPUT ;
    USE SIGNAL ;
    SHAPE ABUTMENT ;
    PORT
      LAYER M4 ;
      RECT 94.800 36.288 94.824 36.312 ;
    END
  END w_mask_in[251]
  PIN w_mask_in[252]
    DIRECTION INPUT ;
    USE SIGNAL ;
    SHAPE ABUTMENT ;
    PORT
      LAYER M4 ;
      RECT 94.800 36.384 94.824 36.408 ;
    END
  END w_mask_in[252]
  PIN w_mask_in[253]
    DIRECTION INPUT ;
    USE SIGNAL ;
    SHAPE ABUTMENT ;
    PORT
      LAYER M4 ;
      RECT 94.800 36.480 94.824 36.504 ;
    END
  END w_mask_in[253]
  PIN w_mask_in[254]
    DIRECTION INPUT ;
    USE SIGNAL ;
    SHAPE ABUTMENT ;
    PORT
      LAYER M4 ;
      RECT 94.800 36.576 94.824 36.600 ;
    END
  END w_mask_in[254]
  PIN w_mask_in[255]
    DIRECTION INPUT ;
    USE SIGNAL ;
    SHAPE ABUTMENT ;
    PORT
      LAYER M4 ;
      RECT 94.800 36.672 94.824 36.696 ;
    END
  END w_mask_in[255]
  PIN rr_en[0]
    DIRECTION INPUT ;
    USE SIGNAL ;
    SHAPE ABUTMENT ;
    PORT
      LAYER M4 ;
      RECT 94.800 36.768 94.824 36.792 ;
    END
  END rr_en[0]
  PIN rr_en[1]
    DIRECTION INPUT ;
    USE SIGNAL ;
    SHAPE ABUTMENT ;
    PORT
      LAYER M4 ;
      RECT 94.800 36.864 94.824 36.888 ;
    END
  END rr_en[1]
  PIN rr_addr[0]
    DIRECTION INPUT ;
    USE SIGNAL ;
    SHAPE ABUTMENT ;
    PORT
      LAYER M4 ;
      RECT 94.800 36.960 94.824 36.984 ;
    END
  END rr_addr[0]
  PIN rr_addr[1]
    DIRECTION INPUT ;
    USE SIGNAL ;
    SHAPE ABUTMENT ;
    PORT
      LAYER M4 ;
      RECT 94.800 37.056 94.824 37.080 ;
    END
  END rr_addr[1]
  PIN rr_addr[2]
    DIRECTION INPUT ;
    USE SIGNAL ;
    SHAPE ABUTMENT ;
    PORT
      LAYER M4 ;
      RECT 94.800 37.152 94.824 37.176 ;
    END
  END rr_addr[2]
  PIN rr_addr[3]
    DIRECTION INPUT ;
    USE SIGNAL ;
    SHAPE ABUTMENT ;
    PORT
      LAYER M4 ;
      RECT 94.800 37.248 94.824 37.272 ;
    END
  END rr_addr[3]
  PIN rr_addr[4]
    DIRECTION INPUT ;
    USE SIGNAL ;
    SHAPE ABUTMENT ;
    PORT
      LAYER M4 ;
      RECT 94.800 37.344 94.824 37.368 ;
    END
  END rr_addr[4]
  PIN rr_addr[5]
    DIRECTION INPUT ;
    USE SIGNAL ;
    SHAPE ABUTMENT ;
    PORT
      LAYER M4 ;
      RECT 94.800 37.440 94.824 37.464 ;
    END
  END rr_addr[5]
  PIN rr_addr[6]
    DIRECTION INPUT ;
    USE SIGNAL ;
    SHAPE ABUTMENT ;
    PORT
      LAYER M4 ;
      RECT 94.800 37.536 94.824 37.560 ;
    END
  END rr_addr[6]
  PIN rr_addr[7]
    DIRECTION INPUT ;
    USE SIGNAL ;
    SHAPE ABUTMENT ;
    PORT
      LAYER M4 ;
      RECT 94.800 37.632 94.824 37.656 ;
    END
  END rr_addr[7]
  PIN rr_addr[8]
    DIRECTION INPUT ;
    USE SIGNAL ;
    SHAPE ABUTMENT ;
    PORT
      LAYER M4 ;
      RECT 94.800 37.728 94.824 37.752 ;
    END
  END rr_addr[8]
  PIN rr_addr[9]
    DIRECTION INPUT ;
    USE SIGNAL ;
    SHAPE ABUTMENT ;
    PORT
      LAYER M4 ;
      RECT 94.800 37.824 94.824 37.848 ;
    END
  END rr_addr[9]
  PIN rr_addr[10]
    DIRECTION INPUT ;
    USE SIGNAL ;
    SHAPE ABUTMENT ;
    PORT
      LAYER M4 ;
      RECT 94.800 37.920 94.824 37.944 ;
    END
  END rr_addr[10]
  PIN rr_addr[11]
    DIRECTION INPUT ;
    USE SIGNAL ;
    SHAPE ABUTMENT ;
    PORT
      LAYER M4 ;
      RECT 94.800 38.016 94.824 38.040 ;
    END
  END rr_addr[11]
  PIN rr_addr[12]
    DIRECTION INPUT ;
    USE SIGNAL ;
    SHAPE ABUTMENT ;
    PORT
      LAYER M4 ;
      RECT 94.800 38.112 94.824 38.136 ;
    END
  END rr_addr[12]
  PIN rr_addr[13]
    DIRECTION INPUT ;
    USE SIGNAL ;
    SHAPE ABUTMENT ;
    PORT
      LAYER M4 ;
      RECT 94.800 38.208 94.824 38.232 ;
    END
  END rr_addr[13]
  PIN cr_en[0]
    DIRECTION INPUT ;
    USE SIGNAL ;
    SHAPE ABUTMENT ;
    PORT
      LAYER M4 ;
      RECT 94.800 38.304 94.824 38.328 ;
    END
  END cr_en[0]
  PIN cr_en[1]
    DIRECTION INPUT ;
    USE SIGNAL ;
    SHAPE ABUTMENT ;
    PORT
      LAYER M4 ;
      RECT 94.800 38.400 94.824 38.424 ;
    END
  END cr_en[1]
  PIN cr_sel[0]
    DIRECTION INPUT ;
    USE SIGNAL ;
    SHAPE ABUTMENT ;
    PORT
      LAYER M4 ;
      RECT 94.800 38.496 94.824 38.520 ;
    END
  END cr_sel[0]
  PIN cr_sel[1]
    DIRECTION INPUT ;
    USE SIGNAL ;
    SHAPE ABUTMENT ;
    PORT
      LAYER M4 ;
      RECT 94.800 38.592 94.824 38.616 ;
    END
  END cr_sel[1]
  PIN cr_sel[2]
    DIRECTION INPUT ;
    USE SIGNAL ;
    SHAPE ABUTMENT ;
    PORT
      LAYER M4 ;
      RECT 94.800 38.688 94.824 38.712 ;
    END
  END cr_sel[2]
  PIN cr_sel[3]
    DIRECTION INPUT ;
    USE SIGNAL ;
    SHAPE ABUTMENT ;
    PORT
      LAYER M4 ;
      RECT 94.800 38.784 94.824 38.808 ;
    END
  END cr_sel[3]
  PIN cr_sel[4]
    DIRECTION INPUT ;
    USE SIGNAL ;
    SHAPE ABUTMENT ;
    PORT
      LAYER M4 ;
      RECT 94.800 38.880 94.824 38.904 ;
    END
  END cr_sel[4]
  PIN cr_sel[5]
    DIRECTION INPUT ;
    USE SIGNAL ;
    SHAPE ABUTMENT ;
    PORT
      LAYER M4 ;
      RECT 94.800 38.976 94.824 39.000 ;
    END
  END cr_sel[5]
  PIN cr_sel[6]
    DIRECTION INPUT ;
    USE SIGNAL ;
    SHAPE ABUTMENT ;
    PORT
      LAYER M4 ;
      RECT 94.800 39.072 94.824 39.096 ;
    END
  END cr_sel[6]
  PIN cr_sel[7]
    DIRECTION INPUT ;
    USE SIGNAL ;
    SHAPE ABUTMENT ;
    PORT
      LAYER M4 ;
      RECT 94.800 39.168 94.824 39.192 ;
    END
  END cr_sel[7]
  PIN cr_sel[8]
    DIRECTION INPUT ;
    USE SIGNAL ;
    SHAPE ABUTMENT ;
    PORT
      LAYER M4 ;
      RECT 94.800 39.264 94.824 39.288 ;
    END
  END cr_sel[8]
  PIN cr_sel[9]
    DIRECTION INPUT ;
    USE SIGNAL ;
    SHAPE ABUTMENT ;
    PORT
      LAYER M4 ;
      RECT 94.800 39.360 94.824 39.384 ;
    END
  END cr_sel[9]
  PIN cr_sel[10]
    DIRECTION INPUT ;
    USE SIGNAL ;
    SHAPE ABUTMENT ;
    PORT
      LAYER M4 ;
      RECT 94.800 39.456 94.824 39.480 ;
    END
  END cr_sel[10]
  PIN cr_sel[11]
    DIRECTION INPUT ;
    USE SIGNAL ;
    SHAPE ABUTMENT ;
    PORT
      LAYER M4 ;
      RECT 94.800 39.552 94.824 39.576 ;
    END
  END cr_sel[11]
  PIN cr_sel[12]
    DIRECTION INPUT ;
    USE SIGNAL ;
    SHAPE ABUTMENT ;
    PORT
      LAYER M4 ;
      RECT 94.800 39.648 94.824 39.672 ;
    END
  END cr_sel[12]
  PIN cr_sel[13]
    DIRECTION INPUT ;
    USE SIGNAL ;
    SHAPE ABUTMENT ;
    PORT
      LAYER M4 ;
      RECT 94.800 39.744 94.824 39.768 ;
    END
  END cr_sel[13]
  PIN cr_sel[14]
    DIRECTION INPUT ;
    USE SIGNAL ;
    SHAPE ABUTMENT ;
    PORT
      LAYER M4 ;
      RECT 94.800 39.840 94.824 39.864 ;
    END
  END cr_sel[14]
  PIN cr_sel[15]
    DIRECTION INPUT ;
    USE SIGNAL ;
    SHAPE ABUTMENT ;
    PORT
      LAYER M4 ;
      RECT 94.800 39.936 94.824 39.960 ;
    END
  END cr_sel[15]
  PIN VDD
    DIRECTION INOUT ;
    USE POWER ;
    PORT
      LAYER M4 ;
      RECT 0.300 0.384 94.524 0.480 ;
      RECT 0.300 1.152 94.524 1.248 ;
      RECT 0.300 1.920 94.524 2.016 ;
      RECT 0.300 2.688 94.524 2.784 ;
      RECT 0.300 3.456 94.524 3.552 ;
      RECT 0.300 4.224 94.524 4.320 ;
      RECT 0.300 4.992 94.524 5.088 ;
      RECT 0.300 5.760 94.524 5.856 ;
      RECT 0.300 6.528 94.524 6.624 ;
      RECT 0.300 7.296 94.524 7.392 ;
      RECT 0.300 8.064 94.524 8.160 ;
      RECT 0.300 8.832 94.524 8.928 ;
      RECT 0.300 9.600 94.524 9.696 ;
      RECT 0.300 10.368 94.524 10.464 ;
      RECT 0.300 11.136 94.524 11.232 ;
      RECT 0.300 11.904 94.524 12.000 ;
      RECT 0.300 12.672 94.524 12.768 ;
      RECT 0.300 13.440 94.524 13.536 ;
      RECT 0.300 14.208 94.524 14.304 ;
      RECT 0.300 14.976 94.524 15.072 ;
      RECT 0.300 15.744 94.524 15.840 ;
      RECT 0.300 16.512 94.524 16.608 ;
      RECT 0.300 17.280 94.524 17.376 ;
      RECT 0.300 18.048 94.524 18.144 ;
      RECT 0.300 18.816 94.524 18.912 ;
      RECT 0.300 19.584 94.524 19.680 ;
      RECT 0.300 20.352 94.524 20.448 ;
      RECT 0.300 21.120 94.524 21.216 ;
      RECT 0.300 21.888 94.524 21.984 ;
      RECT 0.300 22.656 94.524 22.752 ;
      RECT 0.300 23.424 94.524 23.520 ;
      RECT 0.300 24.192 94.524 24.288 ;
      RECT 0.300 24.960 94.524 25.056 ;
      RECT 0.300 25.728 94.524 25.824 ;
      RECT 0.300 26.496 94.524 26.592 ;
      RECT 0.300 27.264 94.524 27.360 ;
      RECT 0.300 28.032 94.524 28.128 ;
      RECT 0.300 28.800 94.524 28.896 ;
      RECT 0.300 29.568 94.524 29.664 ;
      RECT 0.300 30.336 94.524 30.432 ;
      RECT 0.300 31.104 94.524 31.200 ;
      RECT 0.300 31.872 94.524 31.968 ;
      RECT 0.300 32.640 94.524 32.736 ;
      RECT 0.300 33.408 94.524 33.504 ;
      RECT 0.300 34.176 94.524 34.272 ;
      RECT 0.300 34.944 94.524 35.040 ;
      RECT 0.300 35.712 94.524 35.808 ;
      RECT 0.300 36.480 94.524 36.576 ;
      RECT 0.300 37.248 94.524 37.344 ;
      RECT 0.300 38.016 94.524 38.112 ;
      RECT 0.300 38.784 94.524 38.880 ;
      RECT 0.300 39.552 94.524 39.648 ;
      RECT 0.300 40.320 94.524 40.416 ;
    END
  END VDD
  PIN VSS
    DIRECTION INOUT ;
    USE GROUND ;
    PORT
      LAYER M4 ;
      RECT 0.300 0.768 94.524 0.864 ;
      RECT 0.300 1.536 94.524 1.632 ;
      RECT 0.300 2.304 94.524 2.400 ;
      RECT 0.300 3.072 94.524 3.168 ;
      RECT 0.300 3.840 94.524 3.936 ;
      RECT 0.300 4.608 94.524 4.704 ;
      RECT 0.300 5.376 94.524 5.472 ;
      RECT 0.300 6.144 94.524 6.240 ;
      RECT 0.300 6.912 94.524 7.008 ;
      RECT 0.300 7.680 94.524 7.776 ;
      RECT 0.300 8.448 94.524 8.544 ;
      RECT 0.300 9.216 94.524 9.312 ;
      RECT 0.300 9.984 94.524 10.080 ;
      RECT 0.300 10.752 94.524 10.848 ;
      RECT 0.300 11.520 94.524 11.616 ;
      RECT 0.300 12.288 94.524 12.384 ;
      RECT 0.300 13.056 94.524 13.152 ;
      RECT 0.300 13.824 94.524 13.920 ;
      RECT 0.300 14.592 94.524 14.688 ;
      RECT 0.300 15.360 94.524 15.456 ;
      RECT 0.300 16.128 94.524 16.224 ;
      RECT 0.300 16.896 94.524 16.992 ;
      RECT 0.300 17.664 94.524 17.760 ;
      RECT 0.300 18.432 94.524 18.528 ;
      RECT 0.300 19.200 94.524 19.296 ;
      RECT 0.300 19.968 94.524 20.064 ;
      RECT 0.300 20.736 94.524 20.832 ;
      RECT 0.300 21.504 94.524 21.600 ;
      RECT 0.300 22.272 94.524 22.368 ;
      RECT 0.300 23.040 94.524 23.136 ;
      RECT 0.300 23.808 94.524 23.904 ;
      RECT 0.300 24.576 94.524 24.672 ;
      RECT 0.300 25.344 94.524 25.440 ;
      RECT 0.300 26.112 94.524 26.208 ;
      RECT 0.300 26.880 94.524 26.976 ;
      RECT 0.300 27.648 94.524 27.744 ;
      RECT 0.300 28.416 94.524 28.512 ;
      RECT 0.300 29.184 94.524 29.280 ;
      RECT 0.300 29.952 94.524 30.048 ;
      RECT 0.300 30.720 94.524 30.816 ;
      RECT 0.300 31.488 94.524 31.584 ;
      RECT 0.300 32.256 94.524 32.352 ;
      RECT 0.300 33.024 94.524 33.120 ;
      RECT 0.300 33.792 94.524 33.888 ;
      RECT 0.300 34.560 94.524 34.656 ;
      RECT 0.300 35.328 94.524 35.424 ;
      RECT 0.300 36.096 94.524 36.192 ;
      RECT 0.300 36.864 94.524 36.960 ;
      RECT 0.300 37.632 94.524 37.728 ;
      RECT 0.300 38.400 94.524 38.496 ;
      RECT 0.300 39.168 94.524 39.264 ;
      RECT 0.300 39.936 94.524 40.032 ;
      RECT 0.300 40.704 94.524 40.800 ;
    END
  END VSS
  OBS
    LAYER M1 ;
    RECT 0 0 94.824 41.040 ;
    LAYER M2 ;
    RECT 0 0 94.824 41.040 ;
    LAYER M3 ;
    RECT 0 0 94.824 41.040 ;
    LAYER M4 ;
    RECT 0.072 0 94.752 41.040 ;
  END
END ot_sram_1r1w_128x256_m1_r2c2

END LIBRARY
